# OpenTallas tools/mem_compiler/ucie_pma_gen.py: HBM host UCIe analog PMA ABSTRACT ot_ucie_pma_txm (assumed footprint/timing)
VERSION 5.7 ;
BUSBITCHARS "[]" ;
DIVIDERCHAR "/" ;
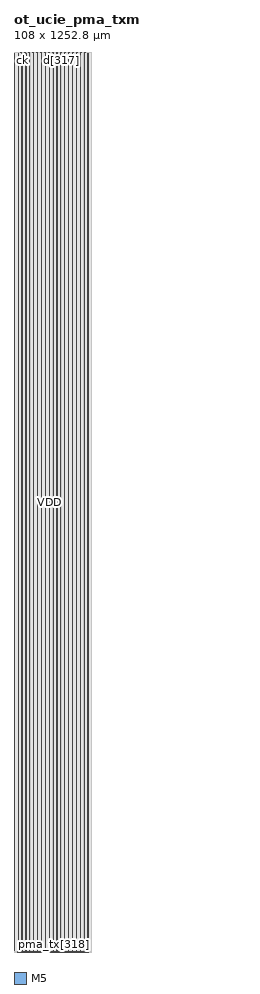
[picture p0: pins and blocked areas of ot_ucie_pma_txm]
MACRO ot_ucie_pma_txm
  FOREIGN ot_ucie_pma_txm 0 0 ;
  SYMMETRY X Y ;
  SIZE 108.000 BY 1252.800 ;
  CLASS BLOCK ;
  PIN ck
    DIRECTION INPUT ;
    USE CLOCK ;
    SHAPE ABUTMENT ;
    PORT
      LAYER M5 ;
      RECT 4.740 1252.608 4.764 1252.800 ;
    END
  END ck
  PIN d[0]
    DIRECTION INPUT ;
    USE SIGNAL ;
    SHAPE ABUTMENT ;
    PORT
      LAYER M5 ;
      RECT 4.932 1252.608 4.956 1252.800 ;
    END
  END d[0]
  PIN d[1]
    DIRECTION INPUT ;
    USE SIGNAL ;
    SHAPE ABUTMENT ;
    PORT
      LAYER M5 ;
      RECT 5.124 1252.608 5.148 1252.800 ;
    END
  END d[1]
  PIN d[2]
    DIRECTION INPUT ;
    USE SIGNAL ;
    SHAPE ABUTMENT ;
    PORT
      LAYER M5 ;
      RECT 5.316 1252.608 5.340 1252.800 ;
    END
  END d[2]
  PIN d[3]
    DIRECTION INPUT ;
    USE SIGNAL ;
    SHAPE ABUTMENT ;
    PORT
      LAYER M5 ;
      RECT 5.508 1252.608 5.532 1252.800 ;
    END
  END d[3]
  PIN d[4]
    DIRECTION INPUT ;
    USE SIGNAL ;
    SHAPE ABUTMENT ;
    PORT
      LAYER M5 ;
      RECT 5.700 1252.608 5.724 1252.800 ;
    END
  END d[4]
  PIN d[5]
    DIRECTION INPUT ;
    USE SIGNAL ;
    SHAPE ABUTMENT ;
    PORT
      LAYER M5 ;
      RECT 5.892 1252.608 5.916 1252.800 ;
    END
  END d[5]
  PIN d[6]
    DIRECTION INPUT ;
    USE SIGNAL ;
    SHAPE ABUTMENT ;
    PORT
      LAYER M5 ;
      RECT 6.084 1252.608 6.108 1252.800 ;
    END
  END d[6]
  PIN d[7]
    DIRECTION INPUT ;
    USE SIGNAL ;
    SHAPE ABUTMENT ;
    PORT
      LAYER M5 ;
      RECT 6.276 1252.608 6.300 1252.800 ;
    END
  END d[7]
  PIN d[8]
    DIRECTION INPUT ;
    USE SIGNAL ;
    SHAPE ABUTMENT ;
    PORT
      LAYER M5 ;
      RECT 6.468 1252.608 6.492 1252.800 ;
    END
  END d[8]
  PIN d[9]
    DIRECTION INPUT ;
    USE SIGNAL ;
    SHAPE ABUTMENT ;
    PORT
      LAYER M5 ;
      RECT 6.660 1252.608 6.684 1252.800 ;
    END
  END d[9]
  PIN d[10]
    DIRECTION INPUT ;
    USE SIGNAL ;
    SHAPE ABUTMENT ;
    PORT
      LAYER M5 ;
      RECT 6.852 1252.608 6.876 1252.800 ;
    END
  END d[10]
  PIN d[11]
    DIRECTION INPUT ;
    USE SIGNAL ;
    SHAPE ABUTMENT ;
    PORT
      LAYER M5 ;
      RECT 7.044 1252.608 7.068 1252.800 ;
    END
  END d[11]
  PIN d[12]
    DIRECTION INPUT ;
    USE SIGNAL ;
    SHAPE ABUTMENT ;
    PORT
      LAYER M5 ;
      RECT 7.236 1252.608 7.260 1252.800 ;
    END
  END d[12]
  PIN d[13]
    DIRECTION INPUT ;
    USE SIGNAL ;
    SHAPE ABUTMENT ;
    PORT
      LAYER M5 ;
      RECT 7.428 1252.608 7.452 1252.800 ;
    END
  END d[13]
  PIN d[14]
    DIRECTION INPUT ;
    USE SIGNAL ;
    SHAPE ABUTMENT ;
    PORT
      LAYER M5 ;
      RECT 7.620 1252.608 7.644 1252.800 ;
    END
  END d[14]
  PIN d[15]
    DIRECTION INPUT ;
    USE SIGNAL ;
    SHAPE ABUTMENT ;
    PORT
      LAYER M5 ;
      RECT 7.812 1252.608 7.836 1252.800 ;
    END
  END d[15]
  PIN d[16]
    DIRECTION INPUT ;
    USE SIGNAL ;
    SHAPE ABUTMENT ;
    PORT
      LAYER M5 ;
      RECT 8.004 1252.608 8.028 1252.800 ;
    END
  END d[16]
  PIN d[17]
    DIRECTION INPUT ;
    USE SIGNAL ;
    SHAPE ABUTMENT ;
    PORT
      LAYER M5 ;
      RECT 8.196 1252.608 8.220 1252.800 ;
    END
  END d[17]
  PIN d[18]
    DIRECTION INPUT ;
    USE SIGNAL ;
    SHAPE ABUTMENT ;
    PORT
      LAYER M5 ;
      RECT 8.388 1252.608 8.412 1252.800 ;
    END
  END d[18]
  PIN d[19]
    DIRECTION INPUT ;
    USE SIGNAL ;
    SHAPE ABUTMENT ;
    PORT
      LAYER M5 ;
      RECT 8.580 1252.608 8.604 1252.800 ;
    END
  END d[19]
  PIN d[20]
    DIRECTION INPUT ;
    USE SIGNAL ;
    SHAPE ABUTMENT ;
    PORT
      LAYER M5 ;
      RECT 8.772 1252.608 8.796 1252.800 ;
    END
  END d[20]
  PIN d[21]
    DIRECTION INPUT ;
    USE SIGNAL ;
    SHAPE ABUTMENT ;
    PORT
      LAYER M5 ;
      RECT 8.964 1252.608 8.988 1252.800 ;
    END
  END d[21]
  PIN d[22]
    DIRECTION INPUT ;
    USE SIGNAL ;
    SHAPE ABUTMENT ;
    PORT
      LAYER M5 ;
      RECT 9.156 1252.608 9.180 1252.800 ;
    END
  END d[22]
  PIN d[23]
    DIRECTION INPUT ;
    USE SIGNAL ;
    SHAPE ABUTMENT ;
    PORT
      LAYER M5 ;
      RECT 9.348 1252.608 9.372 1252.800 ;
    END
  END d[23]
  PIN d[24]
    DIRECTION INPUT ;
    USE SIGNAL ;
    SHAPE ABUTMENT ;
    PORT
      LAYER M5 ;
      RECT 9.540 1252.608 9.564 1252.800 ;
    END
  END d[24]
  PIN d[25]
    DIRECTION INPUT ;
    USE SIGNAL ;
    SHAPE ABUTMENT ;
    PORT
      LAYER M5 ;
      RECT 9.732 1252.608 9.756 1252.800 ;
    END
  END d[25]
  PIN d[26]
    DIRECTION INPUT ;
    USE SIGNAL ;
    SHAPE ABUTMENT ;
    PORT
      LAYER M5 ;
      RECT 9.924 1252.608 9.948 1252.800 ;
    END
  END d[26]
  PIN d[27]
    DIRECTION INPUT ;
    USE SIGNAL ;
    SHAPE ABUTMENT ;
    PORT
      LAYER M5 ;
      RECT 10.116 1252.608 10.140 1252.800 ;
    END
  END d[27]
  PIN d[28]
    DIRECTION INPUT ;
    USE SIGNAL ;
    SHAPE ABUTMENT ;
    PORT
      LAYER M5 ;
      RECT 10.308 1252.608 10.332 1252.800 ;
    END
  END d[28]
  PIN d[29]
    DIRECTION INPUT ;
    USE SIGNAL ;
    SHAPE ABUTMENT ;
    PORT
      LAYER M5 ;
      RECT 10.500 1252.608 10.524 1252.800 ;
    END
  END d[29]
  PIN d[30]
    DIRECTION INPUT ;
    USE SIGNAL ;
    SHAPE ABUTMENT ;
    PORT
      LAYER M5 ;
      RECT 10.692 1252.608 10.716 1252.800 ;
    END
  END d[30]
  PIN d[31]
    DIRECTION INPUT ;
    USE SIGNAL ;
    SHAPE ABUTMENT ;
    PORT
      LAYER M5 ;
      RECT 10.884 1252.608 10.908 1252.800 ;
    END
  END d[31]
  PIN d[32]
    DIRECTION INPUT ;
    USE SIGNAL ;
    SHAPE ABUTMENT ;
    PORT
      LAYER M5 ;
      RECT 11.076 1252.608 11.100 1252.800 ;
    END
  END d[32]
  PIN d[33]
    DIRECTION INPUT ;
    USE SIGNAL ;
    SHAPE ABUTMENT ;
    PORT
      LAYER M5 ;
      RECT 11.268 1252.608 11.292 1252.800 ;
    END
  END d[33]
  PIN d[34]
    DIRECTION INPUT ;
    USE SIGNAL ;
    SHAPE ABUTMENT ;
    PORT
      LAYER M5 ;
      RECT 11.460 1252.608 11.484 1252.800 ;
    END
  END d[34]
  PIN d[35]
    DIRECTION INPUT ;
    USE SIGNAL ;
    SHAPE ABUTMENT ;
    PORT
      LAYER M5 ;
      RECT 11.652 1252.608 11.676 1252.800 ;
    END
  END d[35]
  PIN d[36]
    DIRECTION INPUT ;
    USE SIGNAL ;
    SHAPE ABUTMENT ;
    PORT
      LAYER M5 ;
      RECT 11.844 1252.608 11.868 1252.800 ;
    END
  END d[36]
  PIN d[37]
    DIRECTION INPUT ;
    USE SIGNAL ;
    SHAPE ABUTMENT ;
    PORT
      LAYER M5 ;
      RECT 12.036 1252.608 12.060 1252.800 ;
    END
  END d[37]
  PIN d[38]
    DIRECTION INPUT ;
    USE SIGNAL ;
    SHAPE ABUTMENT ;
    PORT
      LAYER M5 ;
      RECT 12.228 1252.608 12.252 1252.800 ;
    END
  END d[38]
  PIN d[39]
    DIRECTION INPUT ;
    USE SIGNAL ;
    SHAPE ABUTMENT ;
    PORT
      LAYER M5 ;
      RECT 12.420 1252.608 12.444 1252.800 ;
    END
  END d[39]
  PIN d[40]
    DIRECTION INPUT ;
    USE SIGNAL ;
    SHAPE ABUTMENT ;
    PORT
      LAYER M5 ;
      RECT 12.612 1252.608 12.636 1252.800 ;
    END
  END d[40]
  PIN d[41]
    DIRECTION INPUT ;
    USE SIGNAL ;
    SHAPE ABUTMENT ;
    PORT
      LAYER M5 ;
      RECT 12.804 1252.608 12.828 1252.800 ;
    END
  END d[41]
  PIN d[42]
    DIRECTION INPUT ;
    USE SIGNAL ;
    SHAPE ABUTMENT ;
    PORT
      LAYER M5 ;
      RECT 12.996 1252.608 13.020 1252.800 ;
    END
  END d[42]
  PIN d[43]
    DIRECTION INPUT ;
    USE SIGNAL ;
    SHAPE ABUTMENT ;
    PORT
      LAYER M5 ;
      RECT 13.188 1252.608 13.212 1252.800 ;
    END
  END d[43]
  PIN d[44]
    DIRECTION INPUT ;
    USE SIGNAL ;
    SHAPE ABUTMENT ;
    PORT
      LAYER M5 ;
      RECT 13.380 1252.608 13.404 1252.800 ;
    END
  END d[44]
  PIN d[45]
    DIRECTION INPUT ;
    USE SIGNAL ;
    SHAPE ABUTMENT ;
    PORT
      LAYER M5 ;
      RECT 13.572 1252.608 13.596 1252.800 ;
    END
  END d[45]
  PIN d[46]
    DIRECTION INPUT ;
    USE SIGNAL ;
    SHAPE ABUTMENT ;
    PORT
      LAYER M5 ;
      RECT 13.764 1252.608 13.788 1252.800 ;
    END
  END d[46]
  PIN d[47]
    DIRECTION INPUT ;
    USE SIGNAL ;
    SHAPE ABUTMENT ;
    PORT
      LAYER M5 ;
      RECT 13.956 1252.608 13.980 1252.800 ;
    END
  END d[47]
  PIN d[48]
    DIRECTION INPUT ;
    USE SIGNAL ;
    SHAPE ABUTMENT ;
    PORT
      LAYER M5 ;
      RECT 14.148 1252.608 14.172 1252.800 ;
    END
  END d[48]
  PIN d[49]
    DIRECTION INPUT ;
    USE SIGNAL ;
    SHAPE ABUTMENT ;
    PORT
      LAYER M5 ;
      RECT 14.340 1252.608 14.364 1252.800 ;
    END
  END d[49]
  PIN d[50]
    DIRECTION INPUT ;
    USE SIGNAL ;
    SHAPE ABUTMENT ;
    PORT
      LAYER M5 ;
      RECT 14.532 1252.608 14.556 1252.800 ;
    END
  END d[50]
  PIN d[51]
    DIRECTION INPUT ;
    USE SIGNAL ;
    SHAPE ABUTMENT ;
    PORT
      LAYER M5 ;
      RECT 14.724 1252.608 14.748 1252.800 ;
    END
  END d[51]
  PIN d[52]
    DIRECTION INPUT ;
    USE SIGNAL ;
    SHAPE ABUTMENT ;
    PORT
      LAYER M5 ;
      RECT 14.916 1252.608 14.940 1252.800 ;
    END
  END d[52]
  PIN d[53]
    DIRECTION INPUT ;
    USE SIGNAL ;
    SHAPE ABUTMENT ;
    PORT
      LAYER M5 ;
      RECT 15.108 1252.608 15.132 1252.800 ;
    END
  END d[53]
  PIN d[54]
    DIRECTION INPUT ;
    USE SIGNAL ;
    SHAPE ABUTMENT ;
    PORT
      LAYER M5 ;
      RECT 15.300 1252.608 15.324 1252.800 ;
    END
  END d[54]
  PIN d[55]
    DIRECTION INPUT ;
    USE SIGNAL ;
    SHAPE ABUTMENT ;
    PORT
      LAYER M5 ;
      RECT 15.492 1252.608 15.516 1252.800 ;
    END
  END d[55]
  PIN d[56]
    DIRECTION INPUT ;
    USE SIGNAL ;
    SHAPE ABUTMENT ;
    PORT
      LAYER M5 ;
      RECT 15.684 1252.608 15.708 1252.800 ;
    END
  END d[56]
  PIN d[57]
    DIRECTION INPUT ;
    USE SIGNAL ;
    SHAPE ABUTMENT ;
    PORT
      LAYER M5 ;
      RECT 15.876 1252.608 15.900 1252.800 ;
    END
  END d[57]
  PIN d[58]
    DIRECTION INPUT ;
    USE SIGNAL ;
    SHAPE ABUTMENT ;
    PORT
      LAYER M5 ;
      RECT 16.068 1252.608 16.092 1252.800 ;
    END
  END d[58]
  PIN d[59]
    DIRECTION INPUT ;
    USE SIGNAL ;
    SHAPE ABUTMENT ;
    PORT
      LAYER M5 ;
      RECT 16.260 1252.608 16.284 1252.800 ;
    END
  END d[59]
  PIN d[60]
    DIRECTION INPUT ;
    USE SIGNAL ;
    SHAPE ABUTMENT ;
    PORT
      LAYER M5 ;
      RECT 16.452 1252.608 16.476 1252.800 ;
    END
  END d[60]
  PIN d[61]
    DIRECTION INPUT ;
    USE SIGNAL ;
    SHAPE ABUTMENT ;
    PORT
      LAYER M5 ;
      RECT 16.644 1252.608 16.668 1252.800 ;
    END
  END d[61]
  PIN d[62]
    DIRECTION INPUT ;
    USE SIGNAL ;
    SHAPE ABUTMENT ;
    PORT
      LAYER M5 ;
      RECT 16.836 1252.608 16.860 1252.800 ;
    END
  END d[62]
  PIN d[63]
    DIRECTION INPUT ;
    USE SIGNAL ;
    SHAPE ABUTMENT ;
    PORT
      LAYER M5 ;
      RECT 17.028 1252.608 17.052 1252.800 ;
    END
  END d[63]
  PIN d[64]
    DIRECTION INPUT ;
    USE SIGNAL ;
    SHAPE ABUTMENT ;
    PORT
      LAYER M5 ;
      RECT 17.220 1252.608 17.244 1252.800 ;
    END
  END d[64]
  PIN d[65]
    DIRECTION INPUT ;
    USE SIGNAL ;
    SHAPE ABUTMENT ;
    PORT
      LAYER M5 ;
      RECT 17.412 1252.608 17.436 1252.800 ;
    END
  END d[65]
  PIN d[66]
    DIRECTION INPUT ;
    USE SIGNAL ;
    SHAPE ABUTMENT ;
    PORT
      LAYER M5 ;
      RECT 17.604 1252.608 17.628 1252.800 ;
    END
  END d[66]
  PIN d[67]
    DIRECTION INPUT ;
    USE SIGNAL ;
    SHAPE ABUTMENT ;
    PORT
      LAYER M5 ;
      RECT 17.796 1252.608 17.820 1252.800 ;
    END
  END d[67]
  PIN d[68]
    DIRECTION INPUT ;
    USE SIGNAL ;
    SHAPE ABUTMENT ;
    PORT
      LAYER M5 ;
      RECT 17.988 1252.608 18.012 1252.800 ;
    END
  END d[68]
  PIN d[69]
    DIRECTION INPUT ;
    USE SIGNAL ;
    SHAPE ABUTMENT ;
    PORT
      LAYER M5 ;
      RECT 18.180 1252.608 18.204 1252.800 ;
    END
  END d[69]
  PIN d[70]
    DIRECTION INPUT ;
    USE SIGNAL ;
    SHAPE ABUTMENT ;
    PORT
      LAYER M5 ;
      RECT 18.372 1252.608 18.396 1252.800 ;
    END
  END d[70]
  PIN d[71]
    DIRECTION INPUT ;
    USE SIGNAL ;
    SHAPE ABUTMENT ;
    PORT
      LAYER M5 ;
      RECT 18.564 1252.608 18.588 1252.800 ;
    END
  END d[71]
  PIN d[72]
    DIRECTION INPUT ;
    USE SIGNAL ;
    SHAPE ABUTMENT ;
    PORT
      LAYER M5 ;
      RECT 18.756 1252.608 18.780 1252.800 ;
    END
  END d[72]
  PIN d[73]
    DIRECTION INPUT ;
    USE SIGNAL ;
    SHAPE ABUTMENT ;
    PORT
      LAYER M5 ;
      RECT 18.948 1252.608 18.972 1252.800 ;
    END
  END d[73]
  PIN d[74]
    DIRECTION INPUT ;
    USE SIGNAL ;
    SHAPE ABUTMENT ;
    PORT
      LAYER M5 ;
      RECT 19.140 1252.608 19.164 1252.800 ;
    END
  END d[74]
  PIN d[75]
    DIRECTION INPUT ;
    USE SIGNAL ;
    SHAPE ABUTMENT ;
    PORT
      LAYER M5 ;
      RECT 19.332 1252.608 19.356 1252.800 ;
    END
  END d[75]
  PIN d[76]
    DIRECTION INPUT ;
    USE SIGNAL ;
    SHAPE ABUTMENT ;
    PORT
      LAYER M5 ;
      RECT 19.524 1252.608 19.548 1252.800 ;
    END
  END d[76]
  PIN d[77]
    DIRECTION INPUT ;
    USE SIGNAL ;
    SHAPE ABUTMENT ;
    PORT
      LAYER M5 ;
      RECT 19.716 1252.608 19.740 1252.800 ;
    END
  END d[77]
  PIN d[78]
    DIRECTION INPUT ;
    USE SIGNAL ;
    SHAPE ABUTMENT ;
    PORT
      LAYER M5 ;
      RECT 19.908 1252.608 19.932 1252.800 ;
    END
  END d[78]
  PIN d[79]
    DIRECTION INPUT ;
    USE SIGNAL ;
    SHAPE ABUTMENT ;
    PORT
      LAYER M5 ;
      RECT 20.100 1252.608 20.124 1252.800 ;
    END
  END d[79]
  PIN d[80]
    DIRECTION INPUT ;
    USE SIGNAL ;
    SHAPE ABUTMENT ;
    PORT
      LAYER M5 ;
      RECT 20.292 1252.608 20.316 1252.800 ;
    END
  END d[80]
  PIN d[81]
    DIRECTION INPUT ;
    USE SIGNAL ;
    SHAPE ABUTMENT ;
    PORT
      LAYER M5 ;
      RECT 20.484 1252.608 20.508 1252.800 ;
    END
  END d[81]
  PIN d[82]
    DIRECTION INPUT ;
    USE SIGNAL ;
    SHAPE ABUTMENT ;
    PORT
      LAYER M5 ;
      RECT 20.676 1252.608 20.700 1252.800 ;
    END
  END d[82]
  PIN d[83]
    DIRECTION INPUT ;
    USE SIGNAL ;
    SHAPE ABUTMENT ;
    PORT
      LAYER M5 ;
      RECT 20.868 1252.608 20.892 1252.800 ;
    END
  END d[83]
  PIN d[84]
    DIRECTION INPUT ;
    USE SIGNAL ;
    SHAPE ABUTMENT ;
    PORT
      LAYER M5 ;
      RECT 21.060 1252.608 21.084 1252.800 ;
    END
  END d[84]
  PIN d[85]
    DIRECTION INPUT ;
    USE SIGNAL ;
    SHAPE ABUTMENT ;
    PORT
      LAYER M5 ;
      RECT 21.252 1252.608 21.276 1252.800 ;
    END
  END d[85]
  PIN d[86]
    DIRECTION INPUT ;
    USE SIGNAL ;
    SHAPE ABUTMENT ;
    PORT
      LAYER M5 ;
      RECT 21.444 1252.608 21.468 1252.800 ;
    END
  END d[86]
  PIN d[87]
    DIRECTION INPUT ;
    USE SIGNAL ;
    SHAPE ABUTMENT ;
    PORT
      LAYER M5 ;
      RECT 21.636 1252.608 21.660 1252.800 ;
    END
  END d[87]
  PIN d[88]
    DIRECTION INPUT ;
    USE SIGNAL ;
    SHAPE ABUTMENT ;
    PORT
      LAYER M5 ;
      RECT 21.828 1252.608 21.852 1252.800 ;
    END
  END d[88]
  PIN d[89]
    DIRECTION INPUT ;
    USE SIGNAL ;
    SHAPE ABUTMENT ;
    PORT
      LAYER M5 ;
      RECT 22.020 1252.608 22.044 1252.800 ;
    END
  END d[89]
  PIN d[90]
    DIRECTION INPUT ;
    USE SIGNAL ;
    SHAPE ABUTMENT ;
    PORT
      LAYER M5 ;
      RECT 22.212 1252.608 22.236 1252.800 ;
    END
  END d[90]
  PIN d[91]
    DIRECTION INPUT ;
    USE SIGNAL ;
    SHAPE ABUTMENT ;
    PORT
      LAYER M5 ;
      RECT 22.404 1252.608 22.428 1252.800 ;
    END
  END d[91]
  PIN d[92]
    DIRECTION INPUT ;
    USE SIGNAL ;
    SHAPE ABUTMENT ;
    PORT
      LAYER M5 ;
      RECT 22.596 1252.608 22.620 1252.800 ;
    END
  END d[92]
  PIN d[93]
    DIRECTION INPUT ;
    USE SIGNAL ;
    SHAPE ABUTMENT ;
    PORT
      LAYER M5 ;
      RECT 22.788 1252.608 22.812 1252.800 ;
    END
  END d[93]
  PIN d[94]
    DIRECTION INPUT ;
    USE SIGNAL ;
    SHAPE ABUTMENT ;
    PORT
      LAYER M5 ;
      RECT 22.980 1252.608 23.004 1252.800 ;
    END
  END d[94]
  PIN d[95]
    DIRECTION INPUT ;
    USE SIGNAL ;
    SHAPE ABUTMENT ;
    PORT
      LAYER M5 ;
      RECT 23.172 1252.608 23.196 1252.800 ;
    END
  END d[95]
  PIN d[96]
    DIRECTION INPUT ;
    USE SIGNAL ;
    SHAPE ABUTMENT ;
    PORT
      LAYER M5 ;
      RECT 23.364 1252.608 23.388 1252.800 ;
    END
  END d[96]
  PIN d[97]
    DIRECTION INPUT ;
    USE SIGNAL ;
    SHAPE ABUTMENT ;
    PORT
      LAYER M5 ;
      RECT 23.556 1252.608 23.580 1252.800 ;
    END
  END d[97]
  PIN d[98]
    DIRECTION INPUT ;
    USE SIGNAL ;
    SHAPE ABUTMENT ;
    PORT
      LAYER M5 ;
      RECT 23.748 1252.608 23.772 1252.800 ;
    END
  END d[98]
  PIN d[99]
    DIRECTION INPUT ;
    USE SIGNAL ;
    SHAPE ABUTMENT ;
    PORT
      LAYER M5 ;
      RECT 23.940 1252.608 23.964 1252.800 ;
    END
  END d[99]
  PIN d[100]
    DIRECTION INPUT ;
    USE SIGNAL ;
    SHAPE ABUTMENT ;
    PORT
      LAYER M5 ;
      RECT 24.132 1252.608 24.156 1252.800 ;
    END
  END d[100]
  PIN d[101]
    DIRECTION INPUT ;
    USE SIGNAL ;
    SHAPE ABUTMENT ;
    PORT
      LAYER M5 ;
      RECT 24.324 1252.608 24.348 1252.800 ;
    END
  END d[101]
  PIN d[102]
    DIRECTION INPUT ;
    USE SIGNAL ;
    SHAPE ABUTMENT ;
    PORT
      LAYER M5 ;
      RECT 24.516 1252.608 24.540 1252.800 ;
    END
  END d[102]
  PIN d[103]
    DIRECTION INPUT ;
    USE SIGNAL ;
    SHAPE ABUTMENT ;
    PORT
      LAYER M5 ;
      RECT 24.708 1252.608 24.732 1252.800 ;
    END
  END d[103]
  PIN d[104]
    DIRECTION INPUT ;
    USE SIGNAL ;
    SHAPE ABUTMENT ;
    PORT
      LAYER M5 ;
      RECT 24.900 1252.608 24.924 1252.800 ;
    END
  END d[104]
  PIN d[105]
    DIRECTION INPUT ;
    USE SIGNAL ;
    SHAPE ABUTMENT ;
    PORT
      LAYER M5 ;
      RECT 25.092 1252.608 25.116 1252.800 ;
    END
  END d[105]
  PIN d[106]
    DIRECTION INPUT ;
    USE SIGNAL ;
    SHAPE ABUTMENT ;
    PORT
      LAYER M5 ;
      RECT 25.284 1252.608 25.308 1252.800 ;
    END
  END d[106]
  PIN d[107]
    DIRECTION INPUT ;
    USE SIGNAL ;
    SHAPE ABUTMENT ;
    PORT
      LAYER M5 ;
      RECT 25.476 1252.608 25.500 1252.800 ;
    END
  END d[107]
  PIN d[108]
    DIRECTION INPUT ;
    USE SIGNAL ;
    SHAPE ABUTMENT ;
    PORT
      LAYER M5 ;
      RECT 25.668 1252.608 25.692 1252.800 ;
    END
  END d[108]
  PIN d[109]
    DIRECTION INPUT ;
    USE SIGNAL ;
    SHAPE ABUTMENT ;
    PORT
      LAYER M5 ;
      RECT 25.860 1252.608 25.884 1252.800 ;
    END
  END d[109]
  PIN d[110]
    DIRECTION INPUT ;
    USE SIGNAL ;
    SHAPE ABUTMENT ;
    PORT
      LAYER M5 ;
      RECT 26.052 1252.608 26.076 1252.800 ;
    END
  END d[110]
  PIN d[111]
    DIRECTION INPUT ;
    USE SIGNAL ;
    SHAPE ABUTMENT ;
    PORT
      LAYER M5 ;
      RECT 26.244 1252.608 26.268 1252.800 ;
    END
  END d[111]
  PIN d[112]
    DIRECTION INPUT ;
    USE SIGNAL ;
    SHAPE ABUTMENT ;
    PORT
      LAYER M5 ;
      RECT 26.436 1252.608 26.460 1252.800 ;
    END
  END d[112]
  PIN d[113]
    DIRECTION INPUT ;
    USE SIGNAL ;
    SHAPE ABUTMENT ;
    PORT
      LAYER M5 ;
      RECT 26.628 1252.608 26.652 1252.800 ;
    END
  END d[113]
  PIN d[114]
    DIRECTION INPUT ;
    USE SIGNAL ;
    SHAPE ABUTMENT ;
    PORT
      LAYER M5 ;
      RECT 26.820 1252.608 26.844 1252.800 ;
    END
  END d[114]
  PIN d[115]
    DIRECTION INPUT ;
    USE SIGNAL ;
    SHAPE ABUTMENT ;
    PORT
      LAYER M5 ;
      RECT 27.012 1252.608 27.036 1252.800 ;
    END
  END d[115]
  PIN d[116]
    DIRECTION INPUT ;
    USE SIGNAL ;
    SHAPE ABUTMENT ;
    PORT
      LAYER M5 ;
      RECT 27.204 1252.608 27.228 1252.800 ;
    END
  END d[116]
  PIN d[117]
    DIRECTION INPUT ;
    USE SIGNAL ;
    SHAPE ABUTMENT ;
    PORT
      LAYER M5 ;
      RECT 27.396 1252.608 27.420 1252.800 ;
    END
  END d[117]
  PIN d[118]
    DIRECTION INPUT ;
    USE SIGNAL ;
    SHAPE ABUTMENT ;
    PORT
      LAYER M5 ;
      RECT 27.588 1252.608 27.612 1252.800 ;
    END
  END d[118]
  PIN d[119]
    DIRECTION INPUT ;
    USE SIGNAL ;
    SHAPE ABUTMENT ;
    PORT
      LAYER M5 ;
      RECT 27.780 1252.608 27.804 1252.800 ;
    END
  END d[119]
  PIN d[120]
    DIRECTION INPUT ;
    USE SIGNAL ;
    SHAPE ABUTMENT ;
    PORT
      LAYER M5 ;
      RECT 27.972 1252.608 27.996 1252.800 ;
    END
  END d[120]
  PIN d[121]
    DIRECTION INPUT ;
    USE SIGNAL ;
    SHAPE ABUTMENT ;
    PORT
      LAYER M5 ;
      RECT 28.164 1252.608 28.188 1252.800 ;
    END
  END d[121]
  PIN d[122]
    DIRECTION INPUT ;
    USE SIGNAL ;
    SHAPE ABUTMENT ;
    PORT
      LAYER M5 ;
      RECT 28.356 1252.608 28.380 1252.800 ;
    END
  END d[122]
  PIN d[123]
    DIRECTION INPUT ;
    USE SIGNAL ;
    SHAPE ABUTMENT ;
    PORT
      LAYER M5 ;
      RECT 28.548 1252.608 28.572 1252.800 ;
    END
  END d[123]
  PIN d[124]
    DIRECTION INPUT ;
    USE SIGNAL ;
    SHAPE ABUTMENT ;
    PORT
      LAYER M5 ;
      RECT 28.740 1252.608 28.764 1252.800 ;
    END
  END d[124]
  PIN d[125]
    DIRECTION INPUT ;
    USE SIGNAL ;
    SHAPE ABUTMENT ;
    PORT
      LAYER M5 ;
      RECT 28.932 1252.608 28.956 1252.800 ;
    END
  END d[125]
  PIN d[126]
    DIRECTION INPUT ;
    USE SIGNAL ;
    SHAPE ABUTMENT ;
    PORT
      LAYER M5 ;
      RECT 29.124 1252.608 29.148 1252.800 ;
    END
  END d[126]
  PIN d[127]
    DIRECTION INPUT ;
    USE SIGNAL ;
    SHAPE ABUTMENT ;
    PORT
      LAYER M5 ;
      RECT 29.316 1252.608 29.340 1252.800 ;
    END
  END d[127]
  PIN d[128]
    DIRECTION INPUT ;
    USE SIGNAL ;
    SHAPE ABUTMENT ;
    PORT
      LAYER M5 ;
      RECT 29.508 1252.608 29.532 1252.800 ;
    END
  END d[128]
  PIN d[129]
    DIRECTION INPUT ;
    USE SIGNAL ;
    SHAPE ABUTMENT ;
    PORT
      LAYER M5 ;
      RECT 29.700 1252.608 29.724 1252.800 ;
    END
  END d[129]
  PIN d[130]
    DIRECTION INPUT ;
    USE SIGNAL ;
    SHAPE ABUTMENT ;
    PORT
      LAYER M5 ;
      RECT 29.892 1252.608 29.916 1252.800 ;
    END
  END d[130]
  PIN d[131]
    DIRECTION INPUT ;
    USE SIGNAL ;
    SHAPE ABUTMENT ;
    PORT
      LAYER M5 ;
      RECT 30.084 1252.608 30.108 1252.800 ;
    END
  END d[131]
  PIN d[132]
    DIRECTION INPUT ;
    USE SIGNAL ;
    SHAPE ABUTMENT ;
    PORT
      LAYER M5 ;
      RECT 30.276 1252.608 30.300 1252.800 ;
    END
  END d[132]
  PIN d[133]
    DIRECTION INPUT ;
    USE SIGNAL ;
    SHAPE ABUTMENT ;
    PORT
      LAYER M5 ;
      RECT 30.468 1252.608 30.492 1252.800 ;
    END
  END d[133]
  PIN d[134]
    DIRECTION INPUT ;
    USE SIGNAL ;
    SHAPE ABUTMENT ;
    PORT
      LAYER M5 ;
      RECT 30.660 1252.608 30.684 1252.800 ;
    END
  END d[134]
  PIN d[135]
    DIRECTION INPUT ;
    USE SIGNAL ;
    SHAPE ABUTMENT ;
    PORT
      LAYER M5 ;
      RECT 30.852 1252.608 30.876 1252.800 ;
    END
  END d[135]
  PIN d[136]
    DIRECTION INPUT ;
    USE SIGNAL ;
    SHAPE ABUTMENT ;
    PORT
      LAYER M5 ;
      RECT 31.044 1252.608 31.068 1252.800 ;
    END
  END d[136]
  PIN d[137]
    DIRECTION INPUT ;
    USE SIGNAL ;
    SHAPE ABUTMENT ;
    PORT
      LAYER M5 ;
      RECT 31.236 1252.608 31.260 1252.800 ;
    END
  END d[137]
  PIN d[138]
    DIRECTION INPUT ;
    USE SIGNAL ;
    SHAPE ABUTMENT ;
    PORT
      LAYER M5 ;
      RECT 31.428 1252.608 31.452 1252.800 ;
    END
  END d[138]
  PIN d[139]
    DIRECTION INPUT ;
    USE SIGNAL ;
    SHAPE ABUTMENT ;
    PORT
      LAYER M5 ;
      RECT 31.620 1252.608 31.644 1252.800 ;
    END
  END d[139]
  PIN d[140]
    DIRECTION INPUT ;
    USE SIGNAL ;
    SHAPE ABUTMENT ;
    PORT
      LAYER M5 ;
      RECT 31.812 1252.608 31.836 1252.800 ;
    END
  END d[140]
  PIN d[141]
    DIRECTION INPUT ;
    USE SIGNAL ;
    SHAPE ABUTMENT ;
    PORT
      LAYER M5 ;
      RECT 32.004 1252.608 32.028 1252.800 ;
    END
  END d[141]
  PIN d[142]
    DIRECTION INPUT ;
    USE SIGNAL ;
    SHAPE ABUTMENT ;
    PORT
      LAYER M5 ;
      RECT 32.196 1252.608 32.220 1252.800 ;
    END
  END d[142]
  PIN d[143]
    DIRECTION INPUT ;
    USE SIGNAL ;
    SHAPE ABUTMENT ;
    PORT
      LAYER M5 ;
      RECT 32.388 1252.608 32.412 1252.800 ;
    END
  END d[143]
  PIN d[144]
    DIRECTION INPUT ;
    USE SIGNAL ;
    SHAPE ABUTMENT ;
    PORT
      LAYER M5 ;
      RECT 32.580 1252.608 32.604 1252.800 ;
    END
  END d[144]
  PIN d[145]
    DIRECTION INPUT ;
    USE SIGNAL ;
    SHAPE ABUTMENT ;
    PORT
      LAYER M5 ;
      RECT 32.772 1252.608 32.796 1252.800 ;
    END
  END d[145]
  PIN d[146]
    DIRECTION INPUT ;
    USE SIGNAL ;
    SHAPE ABUTMENT ;
    PORT
      LAYER M5 ;
      RECT 32.964 1252.608 32.988 1252.800 ;
    END
  END d[146]
  PIN d[147]
    DIRECTION INPUT ;
    USE SIGNAL ;
    SHAPE ABUTMENT ;
    PORT
      LAYER M5 ;
      RECT 33.156 1252.608 33.180 1252.800 ;
    END
  END d[147]
  PIN d[148]
    DIRECTION INPUT ;
    USE SIGNAL ;
    SHAPE ABUTMENT ;
    PORT
      LAYER M5 ;
      RECT 33.348 1252.608 33.372 1252.800 ;
    END
  END d[148]
  PIN d[149]
    DIRECTION INPUT ;
    USE SIGNAL ;
    SHAPE ABUTMENT ;
    PORT
      LAYER M5 ;
      RECT 33.540 1252.608 33.564 1252.800 ;
    END
  END d[149]
  PIN d[150]
    DIRECTION INPUT ;
    USE SIGNAL ;
    SHAPE ABUTMENT ;
    PORT
      LAYER M5 ;
      RECT 33.732 1252.608 33.756 1252.800 ;
    END
  END d[150]
  PIN d[151]
    DIRECTION INPUT ;
    USE SIGNAL ;
    SHAPE ABUTMENT ;
    PORT
      LAYER M5 ;
      RECT 33.924 1252.608 33.948 1252.800 ;
    END
  END d[151]
  PIN d[152]
    DIRECTION INPUT ;
    USE SIGNAL ;
    SHAPE ABUTMENT ;
    PORT
      LAYER M5 ;
      RECT 34.116 1252.608 34.140 1252.800 ;
    END
  END d[152]
  PIN d[153]
    DIRECTION INPUT ;
    USE SIGNAL ;
    SHAPE ABUTMENT ;
    PORT
      LAYER M5 ;
      RECT 34.308 1252.608 34.332 1252.800 ;
    END
  END d[153]
  PIN d[154]
    DIRECTION INPUT ;
    USE SIGNAL ;
    SHAPE ABUTMENT ;
    PORT
      LAYER M5 ;
      RECT 34.500 1252.608 34.524 1252.800 ;
    END
  END d[154]
  PIN d[155]
    DIRECTION INPUT ;
    USE SIGNAL ;
    SHAPE ABUTMENT ;
    PORT
      LAYER M5 ;
      RECT 34.692 1252.608 34.716 1252.800 ;
    END
  END d[155]
  PIN d[156]
    DIRECTION INPUT ;
    USE SIGNAL ;
    SHAPE ABUTMENT ;
    PORT
      LAYER M5 ;
      RECT 34.884 1252.608 34.908 1252.800 ;
    END
  END d[156]
  PIN d[157]
    DIRECTION INPUT ;
    USE SIGNAL ;
    SHAPE ABUTMENT ;
    PORT
      LAYER M5 ;
      RECT 35.076 1252.608 35.100 1252.800 ;
    END
  END d[157]
  PIN d[158]
    DIRECTION INPUT ;
    USE SIGNAL ;
    SHAPE ABUTMENT ;
    PORT
      LAYER M5 ;
      RECT 35.268 1252.608 35.292 1252.800 ;
    END
  END d[158]
  PIN d[159]
    DIRECTION INPUT ;
    USE SIGNAL ;
    SHAPE ABUTMENT ;
    PORT
      LAYER M5 ;
      RECT 35.460 1252.608 35.484 1252.800 ;
    END
  END d[159]
  PIN d[160]
    DIRECTION INPUT ;
    USE SIGNAL ;
    SHAPE ABUTMENT ;
    PORT
      LAYER M5 ;
      RECT 35.652 1252.608 35.676 1252.800 ;
    END
  END d[160]
  PIN d[161]
    DIRECTION INPUT ;
    USE SIGNAL ;
    SHAPE ABUTMENT ;
    PORT
      LAYER M5 ;
      RECT 35.844 1252.608 35.868 1252.800 ;
    END
  END d[161]
  PIN d[162]
    DIRECTION INPUT ;
    USE SIGNAL ;
    SHAPE ABUTMENT ;
    PORT
      LAYER M5 ;
      RECT 36.036 1252.608 36.060 1252.800 ;
    END
  END d[162]
  PIN d[163]
    DIRECTION INPUT ;
    USE SIGNAL ;
    SHAPE ABUTMENT ;
    PORT
      LAYER M5 ;
      RECT 36.228 1252.608 36.252 1252.800 ;
    END
  END d[163]
  PIN d[164]
    DIRECTION INPUT ;
    USE SIGNAL ;
    SHAPE ABUTMENT ;
    PORT
      LAYER M5 ;
      RECT 36.420 1252.608 36.444 1252.800 ;
    END
  END d[164]
  PIN d[165]
    DIRECTION INPUT ;
    USE SIGNAL ;
    SHAPE ABUTMENT ;
    PORT
      LAYER M5 ;
      RECT 36.612 1252.608 36.636 1252.800 ;
    END
  END d[165]
  PIN d[166]
    DIRECTION INPUT ;
    USE SIGNAL ;
    SHAPE ABUTMENT ;
    PORT
      LAYER M5 ;
      RECT 36.804 1252.608 36.828 1252.800 ;
    END
  END d[166]
  PIN d[167]
    DIRECTION INPUT ;
    USE SIGNAL ;
    SHAPE ABUTMENT ;
    PORT
      LAYER M5 ;
      RECT 36.996 1252.608 37.020 1252.800 ;
    END
  END d[167]
  PIN d[168]
    DIRECTION INPUT ;
    USE SIGNAL ;
    SHAPE ABUTMENT ;
    PORT
      LAYER M5 ;
      RECT 37.188 1252.608 37.212 1252.800 ;
    END
  END d[168]
  PIN d[169]
    DIRECTION INPUT ;
    USE SIGNAL ;
    SHAPE ABUTMENT ;
    PORT
      LAYER M5 ;
      RECT 37.380 1252.608 37.404 1252.800 ;
    END
  END d[169]
  PIN d[170]
    DIRECTION INPUT ;
    USE SIGNAL ;
    SHAPE ABUTMENT ;
    PORT
      LAYER M5 ;
      RECT 37.572 1252.608 37.596 1252.800 ;
    END
  END d[170]
  PIN d[171]
    DIRECTION INPUT ;
    USE SIGNAL ;
    SHAPE ABUTMENT ;
    PORT
      LAYER M5 ;
      RECT 37.764 1252.608 37.788 1252.800 ;
    END
  END d[171]
  PIN d[172]
    DIRECTION INPUT ;
    USE SIGNAL ;
    SHAPE ABUTMENT ;
    PORT
      LAYER M5 ;
      RECT 37.956 1252.608 37.980 1252.800 ;
    END
  END d[172]
  PIN d[173]
    DIRECTION INPUT ;
    USE SIGNAL ;
    SHAPE ABUTMENT ;
    PORT
      LAYER M5 ;
      RECT 38.148 1252.608 38.172 1252.800 ;
    END
  END d[173]
  PIN d[174]
    DIRECTION INPUT ;
    USE SIGNAL ;
    SHAPE ABUTMENT ;
    PORT
      LAYER M5 ;
      RECT 38.340 1252.608 38.364 1252.800 ;
    END
  END d[174]
  PIN d[175]
    DIRECTION INPUT ;
    USE SIGNAL ;
    SHAPE ABUTMENT ;
    PORT
      LAYER M5 ;
      RECT 38.532 1252.608 38.556 1252.800 ;
    END
  END d[175]
  PIN d[176]
    DIRECTION INPUT ;
    USE SIGNAL ;
    SHAPE ABUTMENT ;
    PORT
      LAYER M5 ;
      RECT 38.724 1252.608 38.748 1252.800 ;
    END
  END d[176]
  PIN d[177]
    DIRECTION INPUT ;
    USE SIGNAL ;
    SHAPE ABUTMENT ;
    PORT
      LAYER M5 ;
      RECT 38.916 1252.608 38.940 1252.800 ;
    END
  END d[177]
  PIN d[178]
    DIRECTION INPUT ;
    USE SIGNAL ;
    SHAPE ABUTMENT ;
    PORT
      LAYER M5 ;
      RECT 39.108 1252.608 39.132 1252.800 ;
    END
  END d[178]
  PIN d[179]
    DIRECTION INPUT ;
    USE SIGNAL ;
    SHAPE ABUTMENT ;
    PORT
      LAYER M5 ;
      RECT 39.300 1252.608 39.324 1252.800 ;
    END
  END d[179]
  PIN d[180]
    DIRECTION INPUT ;
    USE SIGNAL ;
    SHAPE ABUTMENT ;
    PORT
      LAYER M5 ;
      RECT 39.492 1252.608 39.516 1252.800 ;
    END
  END d[180]
  PIN d[181]
    DIRECTION INPUT ;
    USE SIGNAL ;
    SHAPE ABUTMENT ;
    PORT
      LAYER M5 ;
      RECT 39.684 1252.608 39.708 1252.800 ;
    END
  END d[181]
  PIN d[182]
    DIRECTION INPUT ;
    USE SIGNAL ;
    SHAPE ABUTMENT ;
    PORT
      LAYER M5 ;
      RECT 39.876 1252.608 39.900 1252.800 ;
    END
  END d[182]
  PIN d[183]
    DIRECTION INPUT ;
    USE SIGNAL ;
    SHAPE ABUTMENT ;
    PORT
      LAYER M5 ;
      RECT 40.068 1252.608 40.092 1252.800 ;
    END
  END d[183]
  PIN d[184]
    DIRECTION INPUT ;
    USE SIGNAL ;
    SHAPE ABUTMENT ;
    PORT
      LAYER M5 ;
      RECT 40.260 1252.608 40.284 1252.800 ;
    END
  END d[184]
  PIN d[185]
    DIRECTION INPUT ;
    USE SIGNAL ;
    SHAPE ABUTMENT ;
    PORT
      LAYER M5 ;
      RECT 40.452 1252.608 40.476 1252.800 ;
    END
  END d[185]
  PIN d[186]
    DIRECTION INPUT ;
    USE SIGNAL ;
    SHAPE ABUTMENT ;
    PORT
      LAYER M5 ;
      RECT 40.644 1252.608 40.668 1252.800 ;
    END
  END d[186]
  PIN d[187]
    DIRECTION INPUT ;
    USE SIGNAL ;
    SHAPE ABUTMENT ;
    PORT
      LAYER M5 ;
      RECT 40.836 1252.608 40.860 1252.800 ;
    END
  END d[187]
  PIN d[188]
    DIRECTION INPUT ;
    USE SIGNAL ;
    SHAPE ABUTMENT ;
    PORT
      LAYER M5 ;
      RECT 41.028 1252.608 41.052 1252.800 ;
    END
  END d[188]
  PIN d[189]
    DIRECTION INPUT ;
    USE SIGNAL ;
    SHAPE ABUTMENT ;
    PORT
      LAYER M5 ;
      RECT 41.220 1252.608 41.244 1252.800 ;
    END
  END d[189]
  PIN d[190]
    DIRECTION INPUT ;
    USE SIGNAL ;
    SHAPE ABUTMENT ;
    PORT
      LAYER M5 ;
      RECT 41.412 1252.608 41.436 1252.800 ;
    END
  END d[190]
  PIN d[191]
    DIRECTION INPUT ;
    USE SIGNAL ;
    SHAPE ABUTMENT ;
    PORT
      LAYER M5 ;
      RECT 41.604 1252.608 41.628 1252.800 ;
    END
  END d[191]
  PIN d[192]
    DIRECTION INPUT ;
    USE SIGNAL ;
    SHAPE ABUTMENT ;
    PORT
      LAYER M5 ;
      RECT 41.796 1252.608 41.820 1252.800 ;
    END
  END d[192]
  PIN d[193]
    DIRECTION INPUT ;
    USE SIGNAL ;
    SHAPE ABUTMENT ;
    PORT
      LAYER M5 ;
      RECT 41.988 1252.608 42.012 1252.800 ;
    END
  END d[193]
  PIN d[194]
    DIRECTION INPUT ;
    USE SIGNAL ;
    SHAPE ABUTMENT ;
    PORT
      LAYER M5 ;
      RECT 42.180 1252.608 42.204 1252.800 ;
    END
  END d[194]
  PIN d[195]
    DIRECTION INPUT ;
    USE SIGNAL ;
    SHAPE ABUTMENT ;
    PORT
      LAYER M5 ;
      RECT 42.372 1252.608 42.396 1252.800 ;
    END
  END d[195]
  PIN d[196]
    DIRECTION INPUT ;
    USE SIGNAL ;
    SHAPE ABUTMENT ;
    PORT
      LAYER M5 ;
      RECT 42.564 1252.608 42.588 1252.800 ;
    END
  END d[196]
  PIN d[197]
    DIRECTION INPUT ;
    USE SIGNAL ;
    SHAPE ABUTMENT ;
    PORT
      LAYER M5 ;
      RECT 42.756 1252.608 42.780 1252.800 ;
    END
  END d[197]
  PIN d[198]
    DIRECTION INPUT ;
    USE SIGNAL ;
    SHAPE ABUTMENT ;
    PORT
      LAYER M5 ;
      RECT 42.948 1252.608 42.972 1252.800 ;
    END
  END d[198]
  PIN d[199]
    DIRECTION INPUT ;
    USE SIGNAL ;
    SHAPE ABUTMENT ;
    PORT
      LAYER M5 ;
      RECT 43.140 1252.608 43.164 1252.800 ;
    END
  END d[199]
  PIN d[200]
    DIRECTION INPUT ;
    USE SIGNAL ;
    SHAPE ABUTMENT ;
    PORT
      LAYER M5 ;
      RECT 43.332 1252.608 43.356 1252.800 ;
    END
  END d[200]
  PIN d[201]
    DIRECTION INPUT ;
    USE SIGNAL ;
    SHAPE ABUTMENT ;
    PORT
      LAYER M5 ;
      RECT 43.524 1252.608 43.548 1252.800 ;
    END
  END d[201]
  PIN d[202]
    DIRECTION INPUT ;
    USE SIGNAL ;
    SHAPE ABUTMENT ;
    PORT
      LAYER M5 ;
      RECT 43.716 1252.608 43.740 1252.800 ;
    END
  END d[202]
  PIN d[203]
    DIRECTION INPUT ;
    USE SIGNAL ;
    SHAPE ABUTMENT ;
    PORT
      LAYER M5 ;
      RECT 43.908 1252.608 43.932 1252.800 ;
    END
  END d[203]
  PIN d[204]
    DIRECTION INPUT ;
    USE SIGNAL ;
    SHAPE ABUTMENT ;
    PORT
      LAYER M5 ;
      RECT 44.100 1252.608 44.124 1252.800 ;
    END
  END d[204]
  PIN d[205]
    DIRECTION INPUT ;
    USE SIGNAL ;
    SHAPE ABUTMENT ;
    PORT
      LAYER M5 ;
      RECT 44.292 1252.608 44.316 1252.800 ;
    END
  END d[205]
  PIN d[206]
    DIRECTION INPUT ;
    USE SIGNAL ;
    SHAPE ABUTMENT ;
    PORT
      LAYER M5 ;
      RECT 44.484 1252.608 44.508 1252.800 ;
    END
  END d[206]
  PIN d[207]
    DIRECTION INPUT ;
    USE SIGNAL ;
    SHAPE ABUTMENT ;
    PORT
      LAYER M5 ;
      RECT 44.676 1252.608 44.700 1252.800 ;
    END
  END d[207]
  PIN d[208]
    DIRECTION INPUT ;
    USE SIGNAL ;
    SHAPE ABUTMENT ;
    PORT
      LAYER M5 ;
      RECT 44.868 1252.608 44.892 1252.800 ;
    END
  END d[208]
  PIN d[209]
    DIRECTION INPUT ;
    USE SIGNAL ;
    SHAPE ABUTMENT ;
    PORT
      LAYER M5 ;
      RECT 45.060 1252.608 45.084 1252.800 ;
    END
  END d[209]
  PIN d[210]
    DIRECTION INPUT ;
    USE SIGNAL ;
    SHAPE ABUTMENT ;
    PORT
      LAYER M5 ;
      RECT 45.252 1252.608 45.276 1252.800 ;
    END
  END d[210]
  PIN d[211]
    DIRECTION INPUT ;
    USE SIGNAL ;
    SHAPE ABUTMENT ;
    PORT
      LAYER M5 ;
      RECT 45.444 1252.608 45.468 1252.800 ;
    END
  END d[211]
  PIN d[212]
    DIRECTION INPUT ;
    USE SIGNAL ;
    SHAPE ABUTMENT ;
    PORT
      LAYER M5 ;
      RECT 45.636 1252.608 45.660 1252.800 ;
    END
  END d[212]
  PIN d[213]
    DIRECTION INPUT ;
    USE SIGNAL ;
    SHAPE ABUTMENT ;
    PORT
      LAYER M5 ;
      RECT 45.828 1252.608 45.852 1252.800 ;
    END
  END d[213]
  PIN d[214]
    DIRECTION INPUT ;
    USE SIGNAL ;
    SHAPE ABUTMENT ;
    PORT
      LAYER M5 ;
      RECT 46.020 1252.608 46.044 1252.800 ;
    END
  END d[214]
  PIN d[215]
    DIRECTION INPUT ;
    USE SIGNAL ;
    SHAPE ABUTMENT ;
    PORT
      LAYER M5 ;
      RECT 46.212 1252.608 46.236 1252.800 ;
    END
  END d[215]
  PIN d[216]
    DIRECTION INPUT ;
    USE SIGNAL ;
    SHAPE ABUTMENT ;
    PORT
      LAYER M5 ;
      RECT 46.404 1252.608 46.428 1252.800 ;
    END
  END d[216]
  PIN d[217]
    DIRECTION INPUT ;
    USE SIGNAL ;
    SHAPE ABUTMENT ;
    PORT
      LAYER M5 ;
      RECT 46.596 1252.608 46.620 1252.800 ;
    END
  END d[217]
  PIN d[218]
    DIRECTION INPUT ;
    USE SIGNAL ;
    SHAPE ABUTMENT ;
    PORT
      LAYER M5 ;
      RECT 46.788 1252.608 46.812 1252.800 ;
    END
  END d[218]
  PIN d[219]
    DIRECTION INPUT ;
    USE SIGNAL ;
    SHAPE ABUTMENT ;
    PORT
      LAYER M5 ;
      RECT 46.980 1252.608 47.004 1252.800 ;
    END
  END d[219]
  PIN d[220]
    DIRECTION INPUT ;
    USE SIGNAL ;
    SHAPE ABUTMENT ;
    PORT
      LAYER M5 ;
      RECT 47.172 1252.608 47.196 1252.800 ;
    END
  END d[220]
  PIN d[221]
    DIRECTION INPUT ;
    USE SIGNAL ;
    SHAPE ABUTMENT ;
    PORT
      LAYER M5 ;
      RECT 47.364 1252.608 47.388 1252.800 ;
    END
  END d[221]
  PIN d[222]
    DIRECTION INPUT ;
    USE SIGNAL ;
    SHAPE ABUTMENT ;
    PORT
      LAYER M5 ;
      RECT 47.556 1252.608 47.580 1252.800 ;
    END
  END d[222]
  PIN d[223]
    DIRECTION INPUT ;
    USE SIGNAL ;
    SHAPE ABUTMENT ;
    PORT
      LAYER M5 ;
      RECT 47.748 1252.608 47.772 1252.800 ;
    END
  END d[223]
  PIN d[224]
    DIRECTION INPUT ;
    USE SIGNAL ;
    SHAPE ABUTMENT ;
    PORT
      LAYER M5 ;
      RECT 47.940 1252.608 47.964 1252.800 ;
    END
  END d[224]
  PIN d[225]
    DIRECTION INPUT ;
    USE SIGNAL ;
    SHAPE ABUTMENT ;
    PORT
      LAYER M5 ;
      RECT 48.132 1252.608 48.156 1252.800 ;
    END
  END d[225]
  PIN d[226]
    DIRECTION INPUT ;
    USE SIGNAL ;
    SHAPE ABUTMENT ;
    PORT
      LAYER M5 ;
      RECT 48.324 1252.608 48.348 1252.800 ;
    END
  END d[226]
  PIN d[227]
    DIRECTION INPUT ;
    USE SIGNAL ;
    SHAPE ABUTMENT ;
    PORT
      LAYER M5 ;
      RECT 48.516 1252.608 48.540 1252.800 ;
    END
  END d[227]
  PIN d[228]
    DIRECTION INPUT ;
    USE SIGNAL ;
    SHAPE ABUTMENT ;
    PORT
      LAYER M5 ;
      RECT 48.708 1252.608 48.732 1252.800 ;
    END
  END d[228]
  PIN d[229]
    DIRECTION INPUT ;
    USE SIGNAL ;
    SHAPE ABUTMENT ;
    PORT
      LAYER M5 ;
      RECT 48.900 1252.608 48.924 1252.800 ;
    END
  END d[229]
  PIN d[230]
    DIRECTION INPUT ;
    USE SIGNAL ;
    SHAPE ABUTMENT ;
    PORT
      LAYER M5 ;
      RECT 49.092 1252.608 49.116 1252.800 ;
    END
  END d[230]
  PIN d[231]
    DIRECTION INPUT ;
    USE SIGNAL ;
    SHAPE ABUTMENT ;
    PORT
      LAYER M5 ;
      RECT 49.284 1252.608 49.308 1252.800 ;
    END
  END d[231]
  PIN d[232]
    DIRECTION INPUT ;
    USE SIGNAL ;
    SHAPE ABUTMENT ;
    PORT
      LAYER M5 ;
      RECT 49.476 1252.608 49.500 1252.800 ;
    END
  END d[232]
  PIN d[233]
    DIRECTION INPUT ;
    USE SIGNAL ;
    SHAPE ABUTMENT ;
    PORT
      LAYER M5 ;
      RECT 49.668 1252.608 49.692 1252.800 ;
    END
  END d[233]
  PIN d[234]
    DIRECTION INPUT ;
    USE SIGNAL ;
    SHAPE ABUTMENT ;
    PORT
      LAYER M5 ;
      RECT 49.860 1252.608 49.884 1252.800 ;
    END
  END d[234]
  PIN d[235]
    DIRECTION INPUT ;
    USE SIGNAL ;
    SHAPE ABUTMENT ;
    PORT
      LAYER M5 ;
      RECT 50.052 1252.608 50.076 1252.800 ;
    END
  END d[235]
  PIN d[236]
    DIRECTION INPUT ;
    USE SIGNAL ;
    SHAPE ABUTMENT ;
    PORT
      LAYER M5 ;
      RECT 50.244 1252.608 50.268 1252.800 ;
    END
  END d[236]
  PIN d[237]
    DIRECTION INPUT ;
    USE SIGNAL ;
    SHAPE ABUTMENT ;
    PORT
      LAYER M5 ;
      RECT 50.436 1252.608 50.460 1252.800 ;
    END
  END d[237]
  PIN d[238]
    DIRECTION INPUT ;
    USE SIGNAL ;
    SHAPE ABUTMENT ;
    PORT
      LAYER M5 ;
      RECT 50.628 1252.608 50.652 1252.800 ;
    END
  END d[238]
  PIN d[239]
    DIRECTION INPUT ;
    USE SIGNAL ;
    SHAPE ABUTMENT ;
    PORT
      LAYER M5 ;
      RECT 50.820 1252.608 50.844 1252.800 ;
    END
  END d[239]
  PIN d[240]
    DIRECTION INPUT ;
    USE SIGNAL ;
    SHAPE ABUTMENT ;
    PORT
      LAYER M5 ;
      RECT 51.012 1252.608 51.036 1252.800 ;
    END
  END d[240]
  PIN d[241]
    DIRECTION INPUT ;
    USE SIGNAL ;
    SHAPE ABUTMENT ;
    PORT
      LAYER M5 ;
      RECT 51.204 1252.608 51.228 1252.800 ;
    END
  END d[241]
  PIN d[242]
    DIRECTION INPUT ;
    USE SIGNAL ;
    SHAPE ABUTMENT ;
    PORT
      LAYER M5 ;
      RECT 51.396 1252.608 51.420 1252.800 ;
    END
  END d[242]
  PIN d[243]
    DIRECTION INPUT ;
    USE SIGNAL ;
    SHAPE ABUTMENT ;
    PORT
      LAYER M5 ;
      RECT 51.588 1252.608 51.612 1252.800 ;
    END
  END d[243]
  PIN d[244]
    DIRECTION INPUT ;
    USE SIGNAL ;
    SHAPE ABUTMENT ;
    PORT
      LAYER M5 ;
      RECT 51.780 1252.608 51.804 1252.800 ;
    END
  END d[244]
  PIN d[245]
    DIRECTION INPUT ;
    USE SIGNAL ;
    SHAPE ABUTMENT ;
    PORT
      LAYER M5 ;
      RECT 51.972 1252.608 51.996 1252.800 ;
    END
  END d[245]
  PIN d[246]
    DIRECTION INPUT ;
    USE SIGNAL ;
    SHAPE ABUTMENT ;
    PORT
      LAYER M5 ;
      RECT 52.164 1252.608 52.188 1252.800 ;
    END
  END d[246]
  PIN d[247]
    DIRECTION INPUT ;
    USE SIGNAL ;
    SHAPE ABUTMENT ;
    PORT
      LAYER M5 ;
      RECT 52.356 1252.608 52.380 1252.800 ;
    END
  END d[247]
  PIN d[248]
    DIRECTION INPUT ;
    USE SIGNAL ;
    SHAPE ABUTMENT ;
    PORT
      LAYER M5 ;
      RECT 52.548 1252.608 52.572 1252.800 ;
    END
  END d[248]
  PIN d[249]
    DIRECTION INPUT ;
    USE SIGNAL ;
    SHAPE ABUTMENT ;
    PORT
      LAYER M5 ;
      RECT 52.740 1252.608 52.764 1252.800 ;
    END
  END d[249]
  PIN d[250]
    DIRECTION INPUT ;
    USE SIGNAL ;
    SHAPE ABUTMENT ;
    PORT
      LAYER M5 ;
      RECT 52.932 1252.608 52.956 1252.800 ;
    END
  END d[250]
  PIN d[251]
    DIRECTION INPUT ;
    USE SIGNAL ;
    SHAPE ABUTMENT ;
    PORT
      LAYER M5 ;
      RECT 53.124 1252.608 53.148 1252.800 ;
    END
  END d[251]
  PIN d[252]
    DIRECTION INPUT ;
    USE SIGNAL ;
    SHAPE ABUTMENT ;
    PORT
      LAYER M5 ;
      RECT 53.316 1252.608 53.340 1252.800 ;
    END
  END d[252]
  PIN d[253]
    DIRECTION INPUT ;
    USE SIGNAL ;
    SHAPE ABUTMENT ;
    PORT
      LAYER M5 ;
      RECT 53.508 1252.608 53.532 1252.800 ;
    END
  END d[253]
  PIN d[254]
    DIRECTION INPUT ;
    USE SIGNAL ;
    SHAPE ABUTMENT ;
    PORT
      LAYER M5 ;
      RECT 53.700 1252.608 53.724 1252.800 ;
    END
  END d[254]
  PIN d[255]
    DIRECTION INPUT ;
    USE SIGNAL ;
    SHAPE ABUTMENT ;
    PORT
      LAYER M5 ;
      RECT 53.892 1252.608 53.916 1252.800 ;
    END
  END d[255]
  PIN d[256]
    DIRECTION INPUT ;
    USE SIGNAL ;
    SHAPE ABUTMENT ;
    PORT
      LAYER M5 ;
      RECT 54.084 1252.608 54.108 1252.800 ;
    END
  END d[256]
  PIN d[257]
    DIRECTION INPUT ;
    USE SIGNAL ;
    SHAPE ABUTMENT ;
    PORT
      LAYER M5 ;
      RECT 54.276 1252.608 54.300 1252.800 ;
    END
  END d[257]
  PIN d[258]
    DIRECTION INPUT ;
    USE SIGNAL ;
    SHAPE ABUTMENT ;
    PORT
      LAYER M5 ;
      RECT 54.468 1252.608 54.492 1252.800 ;
    END
  END d[258]
  PIN d[259]
    DIRECTION INPUT ;
    USE SIGNAL ;
    SHAPE ABUTMENT ;
    PORT
      LAYER M5 ;
      RECT 54.660 1252.608 54.684 1252.800 ;
    END
  END d[259]
  PIN d[260]
    DIRECTION INPUT ;
    USE SIGNAL ;
    SHAPE ABUTMENT ;
    PORT
      LAYER M5 ;
      RECT 54.852 1252.608 54.876 1252.800 ;
    END
  END d[260]
  PIN d[261]
    DIRECTION INPUT ;
    USE SIGNAL ;
    SHAPE ABUTMENT ;
    PORT
      LAYER M5 ;
      RECT 55.044 1252.608 55.068 1252.800 ;
    END
  END d[261]
  PIN d[262]
    DIRECTION INPUT ;
    USE SIGNAL ;
    SHAPE ABUTMENT ;
    PORT
      LAYER M5 ;
      RECT 55.236 1252.608 55.260 1252.800 ;
    END
  END d[262]
  PIN d[263]
    DIRECTION INPUT ;
    USE SIGNAL ;
    SHAPE ABUTMENT ;
    PORT
      LAYER M5 ;
      RECT 55.428 1252.608 55.452 1252.800 ;
    END
  END d[263]
  PIN d[264]
    DIRECTION INPUT ;
    USE SIGNAL ;
    SHAPE ABUTMENT ;
    PORT
      LAYER M5 ;
      RECT 55.620 1252.608 55.644 1252.800 ;
    END
  END d[264]
  PIN d[265]
    DIRECTION INPUT ;
    USE SIGNAL ;
    SHAPE ABUTMENT ;
    PORT
      LAYER M5 ;
      RECT 55.812 1252.608 55.836 1252.800 ;
    END
  END d[265]
  PIN d[266]
    DIRECTION INPUT ;
    USE SIGNAL ;
    SHAPE ABUTMENT ;
    PORT
      LAYER M5 ;
      RECT 56.004 1252.608 56.028 1252.800 ;
    END
  END d[266]
  PIN d[267]
    DIRECTION INPUT ;
    USE SIGNAL ;
    SHAPE ABUTMENT ;
    PORT
      LAYER M5 ;
      RECT 56.196 1252.608 56.220 1252.800 ;
    END
  END d[267]
  PIN d[268]
    DIRECTION INPUT ;
    USE SIGNAL ;
    SHAPE ABUTMENT ;
    PORT
      LAYER M5 ;
      RECT 56.388 1252.608 56.412 1252.800 ;
    END
  END d[268]
  PIN d[269]
    DIRECTION INPUT ;
    USE SIGNAL ;
    SHAPE ABUTMENT ;
    PORT
      LAYER M5 ;
      RECT 56.580 1252.608 56.604 1252.800 ;
    END
  END d[269]
  PIN d[270]
    DIRECTION INPUT ;
    USE SIGNAL ;
    SHAPE ABUTMENT ;
    PORT
      LAYER M5 ;
      RECT 56.772 1252.608 56.796 1252.800 ;
    END
  END d[270]
  PIN d[271]
    DIRECTION INPUT ;
    USE SIGNAL ;
    SHAPE ABUTMENT ;
    PORT
      LAYER M5 ;
      RECT 56.964 1252.608 56.988 1252.800 ;
    END
  END d[271]
  PIN d[272]
    DIRECTION INPUT ;
    USE SIGNAL ;
    SHAPE ABUTMENT ;
    PORT
      LAYER M5 ;
      RECT 57.156 1252.608 57.180 1252.800 ;
    END
  END d[272]
  PIN d[273]
    DIRECTION INPUT ;
    USE SIGNAL ;
    SHAPE ABUTMENT ;
    PORT
      LAYER M5 ;
      RECT 57.348 1252.608 57.372 1252.800 ;
    END
  END d[273]
  PIN d[274]
    DIRECTION INPUT ;
    USE SIGNAL ;
    SHAPE ABUTMENT ;
    PORT
      LAYER M5 ;
      RECT 57.540 1252.608 57.564 1252.800 ;
    END
  END d[274]
  PIN d[275]
    DIRECTION INPUT ;
    USE SIGNAL ;
    SHAPE ABUTMENT ;
    PORT
      LAYER M5 ;
      RECT 57.732 1252.608 57.756 1252.800 ;
    END
  END d[275]
  PIN d[276]
    DIRECTION INPUT ;
    USE SIGNAL ;
    SHAPE ABUTMENT ;
    PORT
      LAYER M5 ;
      RECT 57.924 1252.608 57.948 1252.800 ;
    END
  END d[276]
  PIN d[277]
    DIRECTION INPUT ;
    USE SIGNAL ;
    SHAPE ABUTMENT ;
    PORT
      LAYER M5 ;
      RECT 58.116 1252.608 58.140 1252.800 ;
    END
  END d[277]
  PIN d[278]
    DIRECTION INPUT ;
    USE SIGNAL ;
    SHAPE ABUTMENT ;
    PORT
      LAYER M5 ;
      RECT 58.308 1252.608 58.332 1252.800 ;
    END
  END d[278]
  PIN d[279]
    DIRECTION INPUT ;
    USE SIGNAL ;
    SHAPE ABUTMENT ;
    PORT
      LAYER M5 ;
      RECT 58.500 1252.608 58.524 1252.800 ;
    END
  END d[279]
  PIN d[280]
    DIRECTION INPUT ;
    USE SIGNAL ;
    SHAPE ABUTMENT ;
    PORT
      LAYER M5 ;
      RECT 58.692 1252.608 58.716 1252.800 ;
    END
  END d[280]
  PIN d[281]
    DIRECTION INPUT ;
    USE SIGNAL ;
    SHAPE ABUTMENT ;
    PORT
      LAYER M5 ;
      RECT 58.884 1252.608 58.908 1252.800 ;
    END
  END d[281]
  PIN d[282]
    DIRECTION INPUT ;
    USE SIGNAL ;
    SHAPE ABUTMENT ;
    PORT
      LAYER M5 ;
      RECT 59.076 1252.608 59.100 1252.800 ;
    END
  END d[282]
  PIN d[283]
    DIRECTION INPUT ;
    USE SIGNAL ;
    SHAPE ABUTMENT ;
    PORT
      LAYER M5 ;
      RECT 59.268 1252.608 59.292 1252.800 ;
    END
  END d[283]
  PIN d[284]
    DIRECTION INPUT ;
    USE SIGNAL ;
    SHAPE ABUTMENT ;
    PORT
      LAYER M5 ;
      RECT 59.460 1252.608 59.484 1252.800 ;
    END
  END d[284]
  PIN d[285]
    DIRECTION INPUT ;
    USE SIGNAL ;
    SHAPE ABUTMENT ;
    PORT
      LAYER M5 ;
      RECT 59.652 1252.608 59.676 1252.800 ;
    END
  END d[285]
  PIN d[286]
    DIRECTION INPUT ;
    USE SIGNAL ;
    SHAPE ABUTMENT ;
    PORT
      LAYER M5 ;
      RECT 59.844 1252.608 59.868 1252.800 ;
    END
  END d[286]
  PIN d[287]
    DIRECTION INPUT ;
    USE SIGNAL ;
    SHAPE ABUTMENT ;
    PORT
      LAYER M5 ;
      RECT 60.036 1252.608 60.060 1252.800 ;
    END
  END d[287]
  PIN d[288]
    DIRECTION INPUT ;
    USE SIGNAL ;
    SHAPE ABUTMENT ;
    PORT
      LAYER M5 ;
      RECT 60.228 1252.608 60.252 1252.800 ;
    END
  END d[288]
  PIN d[289]
    DIRECTION INPUT ;
    USE SIGNAL ;
    SHAPE ABUTMENT ;
    PORT
      LAYER M5 ;
      RECT 60.420 1252.608 60.444 1252.800 ;
    END
  END d[289]
  PIN d[290]
    DIRECTION INPUT ;
    USE SIGNAL ;
    SHAPE ABUTMENT ;
    PORT
      LAYER M5 ;
      RECT 60.612 1252.608 60.636 1252.800 ;
    END
  END d[290]
  PIN d[291]
    DIRECTION INPUT ;
    USE SIGNAL ;
    SHAPE ABUTMENT ;
    PORT
      LAYER M5 ;
      RECT 60.804 1252.608 60.828 1252.800 ;
    END
  END d[291]
  PIN d[292]
    DIRECTION INPUT ;
    USE SIGNAL ;
    SHAPE ABUTMENT ;
    PORT
      LAYER M5 ;
      RECT 60.996 1252.608 61.020 1252.800 ;
    END
  END d[292]
  PIN d[293]
    DIRECTION INPUT ;
    USE SIGNAL ;
    SHAPE ABUTMENT ;
    PORT
      LAYER M5 ;
      RECT 61.188 1252.608 61.212 1252.800 ;
    END
  END d[293]
  PIN d[294]
    DIRECTION INPUT ;
    USE SIGNAL ;
    SHAPE ABUTMENT ;
    PORT
      LAYER M5 ;
      RECT 61.380 1252.608 61.404 1252.800 ;
    END
  END d[294]
  PIN d[295]
    DIRECTION INPUT ;
    USE SIGNAL ;
    SHAPE ABUTMENT ;
    PORT
      LAYER M5 ;
      RECT 61.572 1252.608 61.596 1252.800 ;
    END
  END d[295]
  PIN d[296]
    DIRECTION INPUT ;
    USE SIGNAL ;
    SHAPE ABUTMENT ;
    PORT
      LAYER M5 ;
      RECT 61.764 1252.608 61.788 1252.800 ;
    END
  END d[296]
  PIN d[297]
    DIRECTION INPUT ;
    USE SIGNAL ;
    SHAPE ABUTMENT ;
    PORT
      LAYER M5 ;
      RECT 61.956 1252.608 61.980 1252.800 ;
    END
  END d[297]
  PIN d[298]
    DIRECTION INPUT ;
    USE SIGNAL ;
    SHAPE ABUTMENT ;
    PORT
      LAYER M5 ;
      RECT 62.148 1252.608 62.172 1252.800 ;
    END
  END d[298]
  PIN d[299]
    DIRECTION INPUT ;
    USE SIGNAL ;
    SHAPE ABUTMENT ;
    PORT
      LAYER M5 ;
      RECT 62.340 1252.608 62.364 1252.800 ;
    END
  END d[299]
  PIN d[300]
    DIRECTION INPUT ;
    USE SIGNAL ;
    SHAPE ABUTMENT ;
    PORT
      LAYER M5 ;
      RECT 62.532 1252.608 62.556 1252.800 ;
    END
  END d[300]
  PIN d[301]
    DIRECTION INPUT ;
    USE SIGNAL ;
    SHAPE ABUTMENT ;
    PORT
      LAYER M5 ;
      RECT 62.724 1252.608 62.748 1252.800 ;
    END
  END d[301]
  PIN d[302]
    DIRECTION INPUT ;
    USE SIGNAL ;
    SHAPE ABUTMENT ;
    PORT
      LAYER M5 ;
      RECT 62.916 1252.608 62.940 1252.800 ;
    END
  END d[302]
  PIN d[303]
    DIRECTION INPUT ;
    USE SIGNAL ;
    SHAPE ABUTMENT ;
    PORT
      LAYER M5 ;
      RECT 63.108 1252.608 63.132 1252.800 ;
    END
  END d[303]
  PIN d[304]
    DIRECTION INPUT ;
    USE SIGNAL ;
    SHAPE ABUTMENT ;
    PORT
      LAYER M5 ;
      RECT 63.300 1252.608 63.324 1252.800 ;
    END
  END d[304]
  PIN d[305]
    DIRECTION INPUT ;
    USE SIGNAL ;
    SHAPE ABUTMENT ;
    PORT
      LAYER M5 ;
      RECT 63.492 1252.608 63.516 1252.800 ;
    END
  END d[305]
  PIN d[306]
    DIRECTION INPUT ;
    USE SIGNAL ;
    SHAPE ABUTMENT ;
    PORT
      LAYER M5 ;
      RECT 63.684 1252.608 63.708 1252.800 ;
    END
  END d[306]
  PIN d[307]
    DIRECTION INPUT ;
    USE SIGNAL ;
    SHAPE ABUTMENT ;
    PORT
      LAYER M5 ;
      RECT 63.876 1252.608 63.900 1252.800 ;
    END
  END d[307]
  PIN d[308]
    DIRECTION INPUT ;
    USE SIGNAL ;
    SHAPE ABUTMENT ;
    PORT
      LAYER M5 ;
      RECT 64.068 1252.608 64.092 1252.800 ;
    END
  END d[308]
  PIN d[309]
    DIRECTION INPUT ;
    USE SIGNAL ;
    SHAPE ABUTMENT ;
    PORT
      LAYER M5 ;
      RECT 64.260 1252.608 64.284 1252.800 ;
    END
  END d[309]
  PIN d[310]
    DIRECTION INPUT ;
    USE SIGNAL ;
    SHAPE ABUTMENT ;
    PORT
      LAYER M5 ;
      RECT 64.452 1252.608 64.476 1252.800 ;
    END
  END d[310]
  PIN d[311]
    DIRECTION INPUT ;
    USE SIGNAL ;
    SHAPE ABUTMENT ;
    PORT
      LAYER M5 ;
      RECT 64.644 1252.608 64.668 1252.800 ;
    END
  END d[311]
  PIN d[312]
    DIRECTION INPUT ;
    USE SIGNAL ;
    SHAPE ABUTMENT ;
    PORT
      LAYER M5 ;
      RECT 64.836 1252.608 64.860 1252.800 ;
    END
  END d[312]
  PIN d[313]
    DIRECTION INPUT ;
    USE SIGNAL ;
    SHAPE ABUTMENT ;
    PORT
      LAYER M5 ;
      RECT 65.028 1252.608 65.052 1252.800 ;
    END
  END d[313]
  PIN d[314]
    DIRECTION INPUT ;
    USE SIGNAL ;
    SHAPE ABUTMENT ;
    PORT
      LAYER M5 ;
      RECT 65.220 1252.608 65.244 1252.800 ;
    END
  END d[314]
  PIN d[315]
    DIRECTION INPUT ;
    USE SIGNAL ;
    SHAPE ABUTMENT ;
    PORT
      LAYER M5 ;
      RECT 65.412 1252.608 65.436 1252.800 ;
    END
  END d[315]
  PIN d[316]
    DIRECTION INPUT ;
    USE SIGNAL ;
    SHAPE ABUTMENT ;
    PORT
      LAYER M5 ;
      RECT 65.604 1252.608 65.628 1252.800 ;
    END
  END d[316]
  PIN d[317]
    DIRECTION INPUT ;
    USE SIGNAL ;
    SHAPE ABUTMENT ;
    PORT
      LAYER M5 ;
      RECT 65.796 1252.608 65.820 1252.800 ;
    END
  END d[317]
  PIN d[318]
    DIRECTION INPUT ;
    USE SIGNAL ;
    SHAPE ABUTMENT ;
    PORT
      LAYER M5 ;
      RECT 65.988 1252.608 66.012 1252.800 ;
    END
  END d[318]
  PIN d[319]
    DIRECTION INPUT ;
    USE SIGNAL ;
    SHAPE ABUTMENT ;
    PORT
      LAYER M5 ;
      RECT 66.180 1252.608 66.204 1252.800 ;
    END
  END d[319]
  PIN d[320]
    DIRECTION INPUT ;
    USE SIGNAL ;
    SHAPE ABUTMENT ;
    PORT
      LAYER M5 ;
      RECT 66.372 1252.608 66.396 1252.800 ;
    END
  END d[320]
  PIN d[321]
    DIRECTION INPUT ;
    USE SIGNAL ;
    SHAPE ABUTMENT ;
    PORT
      LAYER M5 ;
      RECT 66.564 1252.608 66.588 1252.800 ;
    END
  END d[321]
  PIN d[322]
    DIRECTION INPUT ;
    USE SIGNAL ;
    SHAPE ABUTMENT ;
    PORT
      LAYER M5 ;
      RECT 66.756 1252.608 66.780 1252.800 ;
    END
  END d[322]
  PIN d[323]
    DIRECTION INPUT ;
    USE SIGNAL ;
    SHAPE ABUTMENT ;
    PORT
      LAYER M5 ;
      RECT 66.948 1252.608 66.972 1252.800 ;
    END
  END d[323]
  PIN d[324]
    DIRECTION INPUT ;
    USE SIGNAL ;
    SHAPE ABUTMENT ;
    PORT
      LAYER M5 ;
      RECT 67.140 1252.608 67.164 1252.800 ;
    END
  END d[324]
  PIN d[325]
    DIRECTION INPUT ;
    USE SIGNAL ;
    SHAPE ABUTMENT ;
    PORT
      LAYER M5 ;
      RECT 67.332 1252.608 67.356 1252.800 ;
    END
  END d[325]
  PIN d[326]
    DIRECTION INPUT ;
    USE SIGNAL ;
    SHAPE ABUTMENT ;
    PORT
      LAYER M5 ;
      RECT 67.524 1252.608 67.548 1252.800 ;
    END
  END d[326]
  PIN d[327]
    DIRECTION INPUT ;
    USE SIGNAL ;
    SHAPE ABUTMENT ;
    PORT
      LAYER M5 ;
      RECT 67.716 1252.608 67.740 1252.800 ;
    END
  END d[327]
  PIN d[328]
    DIRECTION INPUT ;
    USE SIGNAL ;
    SHAPE ABUTMENT ;
    PORT
      LAYER M5 ;
      RECT 67.908 1252.608 67.932 1252.800 ;
    END
  END d[328]
  PIN d[329]
    DIRECTION INPUT ;
    USE SIGNAL ;
    SHAPE ABUTMENT ;
    PORT
      LAYER M5 ;
      RECT 68.100 1252.608 68.124 1252.800 ;
    END
  END d[329]
  PIN d[330]
    DIRECTION INPUT ;
    USE SIGNAL ;
    SHAPE ABUTMENT ;
    PORT
      LAYER M5 ;
      RECT 68.292 1252.608 68.316 1252.800 ;
    END
  END d[330]
  PIN d[331]
    DIRECTION INPUT ;
    USE SIGNAL ;
    SHAPE ABUTMENT ;
    PORT
      LAYER M5 ;
      RECT 68.484 1252.608 68.508 1252.800 ;
    END
  END d[331]
  PIN d[332]
    DIRECTION INPUT ;
    USE SIGNAL ;
    SHAPE ABUTMENT ;
    PORT
      LAYER M5 ;
      RECT 68.676 1252.608 68.700 1252.800 ;
    END
  END d[332]
  PIN d[333]
    DIRECTION INPUT ;
    USE SIGNAL ;
    SHAPE ABUTMENT ;
    PORT
      LAYER M5 ;
      RECT 68.868 1252.608 68.892 1252.800 ;
    END
  END d[333]
  PIN d[334]
    DIRECTION INPUT ;
    USE SIGNAL ;
    SHAPE ABUTMENT ;
    PORT
      LAYER M5 ;
      RECT 69.060 1252.608 69.084 1252.800 ;
    END
  END d[334]
  PIN d[335]
    DIRECTION INPUT ;
    USE SIGNAL ;
    SHAPE ABUTMENT ;
    PORT
      LAYER M5 ;
      RECT 69.252 1252.608 69.276 1252.800 ;
    END
  END d[335]
  PIN d[336]
    DIRECTION INPUT ;
    USE SIGNAL ;
    SHAPE ABUTMENT ;
    PORT
      LAYER M5 ;
      RECT 69.444 1252.608 69.468 1252.800 ;
    END
  END d[336]
  PIN d[337]
    DIRECTION INPUT ;
    USE SIGNAL ;
    SHAPE ABUTMENT ;
    PORT
      LAYER M5 ;
      RECT 69.636 1252.608 69.660 1252.800 ;
    END
  END d[337]
  PIN d[338]
    DIRECTION INPUT ;
    USE SIGNAL ;
    SHAPE ABUTMENT ;
    PORT
      LAYER M5 ;
      RECT 69.828 1252.608 69.852 1252.800 ;
    END
  END d[338]
  PIN d[339]
    DIRECTION INPUT ;
    USE SIGNAL ;
    SHAPE ABUTMENT ;
    PORT
      LAYER M5 ;
      RECT 70.020 1252.608 70.044 1252.800 ;
    END
  END d[339]
  PIN d[340]
    DIRECTION INPUT ;
    USE SIGNAL ;
    SHAPE ABUTMENT ;
    PORT
      LAYER M5 ;
      RECT 70.212 1252.608 70.236 1252.800 ;
    END
  END d[340]
  PIN d[341]
    DIRECTION INPUT ;
    USE SIGNAL ;
    SHAPE ABUTMENT ;
    PORT
      LAYER M5 ;
      RECT 70.404 1252.608 70.428 1252.800 ;
    END
  END d[341]
  PIN d[342]
    DIRECTION INPUT ;
    USE SIGNAL ;
    SHAPE ABUTMENT ;
    PORT
      LAYER M5 ;
      RECT 70.596 1252.608 70.620 1252.800 ;
    END
  END d[342]
  PIN d[343]
    DIRECTION INPUT ;
    USE SIGNAL ;
    SHAPE ABUTMENT ;
    PORT
      LAYER M5 ;
      RECT 70.788 1252.608 70.812 1252.800 ;
    END
  END d[343]
  PIN d[344]
    DIRECTION INPUT ;
    USE SIGNAL ;
    SHAPE ABUTMENT ;
    PORT
      LAYER M5 ;
      RECT 70.980 1252.608 71.004 1252.800 ;
    END
  END d[344]
  PIN d[345]
    DIRECTION INPUT ;
    USE SIGNAL ;
    SHAPE ABUTMENT ;
    PORT
      LAYER M5 ;
      RECT 71.172 1252.608 71.196 1252.800 ;
    END
  END d[345]
  PIN d[346]
    DIRECTION INPUT ;
    USE SIGNAL ;
    SHAPE ABUTMENT ;
    PORT
      LAYER M5 ;
      RECT 71.364 1252.608 71.388 1252.800 ;
    END
  END d[346]
  PIN d[347]
    DIRECTION INPUT ;
    USE SIGNAL ;
    SHAPE ABUTMENT ;
    PORT
      LAYER M5 ;
      RECT 71.556 1252.608 71.580 1252.800 ;
    END
  END d[347]
  PIN d[348]
    DIRECTION INPUT ;
    USE SIGNAL ;
    SHAPE ABUTMENT ;
    PORT
      LAYER M5 ;
      RECT 71.748 1252.608 71.772 1252.800 ;
    END
  END d[348]
  PIN d[349]
    DIRECTION INPUT ;
    USE SIGNAL ;
    SHAPE ABUTMENT ;
    PORT
      LAYER M5 ;
      RECT 71.940 1252.608 71.964 1252.800 ;
    END
  END d[349]
  PIN d[350]
    DIRECTION INPUT ;
    USE SIGNAL ;
    SHAPE ABUTMENT ;
    PORT
      LAYER M5 ;
      RECT 72.132 1252.608 72.156 1252.800 ;
    END
  END d[350]
  PIN d[351]
    DIRECTION INPUT ;
    USE SIGNAL ;
    SHAPE ABUTMENT ;
    PORT
      LAYER M5 ;
      RECT 72.324 1252.608 72.348 1252.800 ;
    END
  END d[351]
  PIN d[352]
    DIRECTION INPUT ;
    USE SIGNAL ;
    SHAPE ABUTMENT ;
    PORT
      LAYER M5 ;
      RECT 72.516 1252.608 72.540 1252.800 ;
    END
  END d[352]
  PIN d[353]
    DIRECTION INPUT ;
    USE SIGNAL ;
    SHAPE ABUTMENT ;
    PORT
      LAYER M5 ;
      RECT 72.708 1252.608 72.732 1252.800 ;
    END
  END d[353]
  PIN d[354]
    DIRECTION INPUT ;
    USE SIGNAL ;
    SHAPE ABUTMENT ;
    PORT
      LAYER M5 ;
      RECT 72.900 1252.608 72.924 1252.800 ;
    END
  END d[354]
  PIN d[355]
    DIRECTION INPUT ;
    USE SIGNAL ;
    SHAPE ABUTMENT ;
    PORT
      LAYER M5 ;
      RECT 73.092 1252.608 73.116 1252.800 ;
    END
  END d[355]
  PIN d[356]
    DIRECTION INPUT ;
    USE SIGNAL ;
    SHAPE ABUTMENT ;
    PORT
      LAYER M5 ;
      RECT 73.284 1252.608 73.308 1252.800 ;
    END
  END d[356]
  PIN d[357]
    DIRECTION INPUT ;
    USE SIGNAL ;
    SHAPE ABUTMENT ;
    PORT
      LAYER M5 ;
      RECT 73.476 1252.608 73.500 1252.800 ;
    END
  END d[357]
  PIN d[358]
    DIRECTION INPUT ;
    USE SIGNAL ;
    SHAPE ABUTMENT ;
    PORT
      LAYER M5 ;
      RECT 73.668 1252.608 73.692 1252.800 ;
    END
  END d[358]
  PIN d[359]
    DIRECTION INPUT ;
    USE SIGNAL ;
    SHAPE ABUTMENT ;
    PORT
      LAYER M5 ;
      RECT 73.860 1252.608 73.884 1252.800 ;
    END
  END d[359]
  PIN d[360]
    DIRECTION INPUT ;
    USE SIGNAL ;
    SHAPE ABUTMENT ;
    PORT
      LAYER M5 ;
      RECT 74.052 1252.608 74.076 1252.800 ;
    END
  END d[360]
  PIN d[361]
    DIRECTION INPUT ;
    USE SIGNAL ;
    SHAPE ABUTMENT ;
    PORT
      LAYER M5 ;
      RECT 74.244 1252.608 74.268 1252.800 ;
    END
  END d[361]
  PIN d[362]
    DIRECTION INPUT ;
    USE SIGNAL ;
    SHAPE ABUTMENT ;
    PORT
      LAYER M5 ;
      RECT 74.436 1252.608 74.460 1252.800 ;
    END
  END d[362]
  PIN d[363]
    DIRECTION INPUT ;
    USE SIGNAL ;
    SHAPE ABUTMENT ;
    PORT
      LAYER M5 ;
      RECT 74.628 1252.608 74.652 1252.800 ;
    END
  END d[363]
  PIN d[364]
    DIRECTION INPUT ;
    USE SIGNAL ;
    SHAPE ABUTMENT ;
    PORT
      LAYER M5 ;
      RECT 74.820 1252.608 74.844 1252.800 ;
    END
  END d[364]
  PIN d[365]
    DIRECTION INPUT ;
    USE SIGNAL ;
    SHAPE ABUTMENT ;
    PORT
      LAYER M5 ;
      RECT 75.012 1252.608 75.036 1252.800 ;
    END
  END d[365]
  PIN d[366]
    DIRECTION INPUT ;
    USE SIGNAL ;
    SHAPE ABUTMENT ;
    PORT
      LAYER M5 ;
      RECT 75.204 1252.608 75.228 1252.800 ;
    END
  END d[366]
  PIN d[367]
    DIRECTION INPUT ;
    USE SIGNAL ;
    SHAPE ABUTMENT ;
    PORT
      LAYER M5 ;
      RECT 75.396 1252.608 75.420 1252.800 ;
    END
  END d[367]
  PIN d[368]
    DIRECTION INPUT ;
    USE SIGNAL ;
    SHAPE ABUTMENT ;
    PORT
      LAYER M5 ;
      RECT 75.588 1252.608 75.612 1252.800 ;
    END
  END d[368]
  PIN d[369]
    DIRECTION INPUT ;
    USE SIGNAL ;
    SHAPE ABUTMENT ;
    PORT
      LAYER M5 ;
      RECT 75.780 1252.608 75.804 1252.800 ;
    END
  END d[369]
  PIN d[370]
    DIRECTION INPUT ;
    USE SIGNAL ;
    SHAPE ABUTMENT ;
    PORT
      LAYER M5 ;
      RECT 75.972 1252.608 75.996 1252.800 ;
    END
  END d[370]
  PIN d[371]
    DIRECTION INPUT ;
    USE SIGNAL ;
    SHAPE ABUTMENT ;
    PORT
      LAYER M5 ;
      RECT 76.164 1252.608 76.188 1252.800 ;
    END
  END d[371]
  PIN d[372]
    DIRECTION INPUT ;
    USE SIGNAL ;
    SHAPE ABUTMENT ;
    PORT
      LAYER M5 ;
      RECT 76.356 1252.608 76.380 1252.800 ;
    END
  END d[372]
  PIN d[373]
    DIRECTION INPUT ;
    USE SIGNAL ;
    SHAPE ABUTMENT ;
    PORT
      LAYER M5 ;
      RECT 76.548 1252.608 76.572 1252.800 ;
    END
  END d[373]
  PIN d[374]
    DIRECTION INPUT ;
    USE SIGNAL ;
    SHAPE ABUTMENT ;
    PORT
      LAYER M5 ;
      RECT 76.740 1252.608 76.764 1252.800 ;
    END
  END d[374]
  PIN d[375]
    DIRECTION INPUT ;
    USE SIGNAL ;
    SHAPE ABUTMENT ;
    PORT
      LAYER M5 ;
      RECT 76.932 1252.608 76.956 1252.800 ;
    END
  END d[375]
  PIN d[376]
    DIRECTION INPUT ;
    USE SIGNAL ;
    SHAPE ABUTMENT ;
    PORT
      LAYER M5 ;
      RECT 77.124 1252.608 77.148 1252.800 ;
    END
  END d[376]
  PIN d[377]
    DIRECTION INPUT ;
    USE SIGNAL ;
    SHAPE ABUTMENT ;
    PORT
      LAYER M5 ;
      RECT 77.316 1252.608 77.340 1252.800 ;
    END
  END d[377]
  PIN d[378]
    DIRECTION INPUT ;
    USE SIGNAL ;
    SHAPE ABUTMENT ;
    PORT
      LAYER M5 ;
      RECT 77.508 1252.608 77.532 1252.800 ;
    END
  END d[378]
  PIN d[379]
    DIRECTION INPUT ;
    USE SIGNAL ;
    SHAPE ABUTMENT ;
    PORT
      LAYER M5 ;
      RECT 77.700 1252.608 77.724 1252.800 ;
    END
  END d[379]
  PIN d[380]
    DIRECTION INPUT ;
    USE SIGNAL ;
    SHAPE ABUTMENT ;
    PORT
      LAYER M5 ;
      RECT 77.892 1252.608 77.916 1252.800 ;
    END
  END d[380]
  PIN d[381]
    DIRECTION INPUT ;
    USE SIGNAL ;
    SHAPE ABUTMENT ;
    PORT
      LAYER M5 ;
      RECT 78.084 1252.608 78.108 1252.800 ;
    END
  END d[381]
  PIN d[382]
    DIRECTION INPUT ;
    USE SIGNAL ;
    SHAPE ABUTMENT ;
    PORT
      LAYER M5 ;
      RECT 78.276 1252.608 78.300 1252.800 ;
    END
  END d[382]
  PIN d[383]
    DIRECTION INPUT ;
    USE SIGNAL ;
    SHAPE ABUTMENT ;
    PORT
      LAYER M5 ;
      RECT 78.468 1252.608 78.492 1252.800 ;
    END
  END d[383]
  PIN d[384]
    DIRECTION INPUT ;
    USE SIGNAL ;
    SHAPE ABUTMENT ;
    PORT
      LAYER M5 ;
      RECT 78.660 1252.608 78.684 1252.800 ;
    END
  END d[384]
  PIN d[385]
    DIRECTION INPUT ;
    USE SIGNAL ;
    SHAPE ABUTMENT ;
    PORT
      LAYER M5 ;
      RECT 78.852 1252.608 78.876 1252.800 ;
    END
  END d[385]
  PIN d[386]
    DIRECTION INPUT ;
    USE SIGNAL ;
    SHAPE ABUTMENT ;
    PORT
      LAYER M5 ;
      RECT 79.044 1252.608 79.068 1252.800 ;
    END
  END d[386]
  PIN d[387]
    DIRECTION INPUT ;
    USE SIGNAL ;
    SHAPE ABUTMENT ;
    PORT
      LAYER M5 ;
      RECT 79.236 1252.608 79.260 1252.800 ;
    END
  END d[387]
  PIN d[388]
    DIRECTION INPUT ;
    USE SIGNAL ;
    SHAPE ABUTMENT ;
    PORT
      LAYER M5 ;
      RECT 79.428 1252.608 79.452 1252.800 ;
    END
  END d[388]
  PIN d[389]
    DIRECTION INPUT ;
    USE SIGNAL ;
    SHAPE ABUTMENT ;
    PORT
      LAYER M5 ;
      RECT 79.620 1252.608 79.644 1252.800 ;
    END
  END d[389]
  PIN d[390]
    DIRECTION INPUT ;
    USE SIGNAL ;
    SHAPE ABUTMENT ;
    PORT
      LAYER M5 ;
      RECT 79.812 1252.608 79.836 1252.800 ;
    END
  END d[390]
  PIN d[391]
    DIRECTION INPUT ;
    USE SIGNAL ;
    SHAPE ABUTMENT ;
    PORT
      LAYER M5 ;
      RECT 80.004 1252.608 80.028 1252.800 ;
    END
  END d[391]
  PIN d[392]
    DIRECTION INPUT ;
    USE SIGNAL ;
    SHAPE ABUTMENT ;
    PORT
      LAYER M5 ;
      RECT 80.196 1252.608 80.220 1252.800 ;
    END
  END d[392]
  PIN d[393]
    DIRECTION INPUT ;
    USE SIGNAL ;
    SHAPE ABUTMENT ;
    PORT
      LAYER M5 ;
      RECT 80.388 1252.608 80.412 1252.800 ;
    END
  END d[393]
  PIN d[394]
    DIRECTION INPUT ;
    USE SIGNAL ;
    SHAPE ABUTMENT ;
    PORT
      LAYER M5 ;
      RECT 80.580 1252.608 80.604 1252.800 ;
    END
  END d[394]
  PIN d[395]
    DIRECTION INPUT ;
    USE SIGNAL ;
    SHAPE ABUTMENT ;
    PORT
      LAYER M5 ;
      RECT 80.772 1252.608 80.796 1252.800 ;
    END
  END d[395]
  PIN d[396]
    DIRECTION INPUT ;
    USE SIGNAL ;
    SHAPE ABUTMENT ;
    PORT
      LAYER M5 ;
      RECT 80.964 1252.608 80.988 1252.800 ;
    END
  END d[396]
  PIN d[397]
    DIRECTION INPUT ;
    USE SIGNAL ;
    SHAPE ABUTMENT ;
    PORT
      LAYER M5 ;
      RECT 81.156 1252.608 81.180 1252.800 ;
    END
  END d[397]
  PIN d[398]
    DIRECTION INPUT ;
    USE SIGNAL ;
    SHAPE ABUTMENT ;
    PORT
      LAYER M5 ;
      RECT 81.348 1252.608 81.372 1252.800 ;
    END
  END d[398]
  PIN d[399]
    DIRECTION INPUT ;
    USE SIGNAL ;
    SHAPE ABUTMENT ;
    PORT
      LAYER M5 ;
      RECT 81.540 1252.608 81.564 1252.800 ;
    END
  END d[399]
  PIN d[400]
    DIRECTION INPUT ;
    USE SIGNAL ;
    SHAPE ABUTMENT ;
    PORT
      LAYER M5 ;
      RECT 81.732 1252.608 81.756 1252.800 ;
    END
  END d[400]
  PIN d[401]
    DIRECTION INPUT ;
    USE SIGNAL ;
    SHAPE ABUTMENT ;
    PORT
      LAYER M5 ;
      RECT 81.924 1252.608 81.948 1252.800 ;
    END
  END d[401]
  PIN d[402]
    DIRECTION INPUT ;
    USE SIGNAL ;
    SHAPE ABUTMENT ;
    PORT
      LAYER M5 ;
      RECT 82.116 1252.608 82.140 1252.800 ;
    END
  END d[402]
  PIN d[403]
    DIRECTION INPUT ;
    USE SIGNAL ;
    SHAPE ABUTMENT ;
    PORT
      LAYER M5 ;
      RECT 82.308 1252.608 82.332 1252.800 ;
    END
  END d[403]
  PIN d[404]
    DIRECTION INPUT ;
    USE SIGNAL ;
    SHAPE ABUTMENT ;
    PORT
      LAYER M5 ;
      RECT 82.500 1252.608 82.524 1252.800 ;
    END
  END d[404]
  PIN d[405]
    DIRECTION INPUT ;
    USE SIGNAL ;
    SHAPE ABUTMENT ;
    PORT
      LAYER M5 ;
      RECT 82.692 1252.608 82.716 1252.800 ;
    END
  END d[405]
  PIN d[406]
    DIRECTION INPUT ;
    USE SIGNAL ;
    SHAPE ABUTMENT ;
    PORT
      LAYER M5 ;
      RECT 82.884 1252.608 82.908 1252.800 ;
    END
  END d[406]
  PIN d[407]
    DIRECTION INPUT ;
    USE SIGNAL ;
    SHAPE ABUTMENT ;
    PORT
      LAYER M5 ;
      RECT 83.076 1252.608 83.100 1252.800 ;
    END
  END d[407]
  PIN d[408]
    DIRECTION INPUT ;
    USE SIGNAL ;
    SHAPE ABUTMENT ;
    PORT
      LAYER M5 ;
      RECT 83.268 1252.608 83.292 1252.800 ;
    END
  END d[408]
  PIN d[409]
    DIRECTION INPUT ;
    USE SIGNAL ;
    SHAPE ABUTMENT ;
    PORT
      LAYER M5 ;
      RECT 83.460 1252.608 83.484 1252.800 ;
    END
  END d[409]
  PIN d[410]
    DIRECTION INPUT ;
    USE SIGNAL ;
    SHAPE ABUTMENT ;
    PORT
      LAYER M5 ;
      RECT 83.652 1252.608 83.676 1252.800 ;
    END
  END d[410]
  PIN d[411]
    DIRECTION INPUT ;
    USE SIGNAL ;
    SHAPE ABUTMENT ;
    PORT
      LAYER M5 ;
      RECT 83.844 1252.608 83.868 1252.800 ;
    END
  END d[411]
  PIN d[412]
    DIRECTION INPUT ;
    USE SIGNAL ;
    SHAPE ABUTMENT ;
    PORT
      LAYER M5 ;
      RECT 84.036 1252.608 84.060 1252.800 ;
    END
  END d[412]
  PIN d[413]
    DIRECTION INPUT ;
    USE SIGNAL ;
    SHAPE ABUTMENT ;
    PORT
      LAYER M5 ;
      RECT 84.228 1252.608 84.252 1252.800 ;
    END
  END d[413]
  PIN d[414]
    DIRECTION INPUT ;
    USE SIGNAL ;
    SHAPE ABUTMENT ;
    PORT
      LAYER M5 ;
      RECT 84.420 1252.608 84.444 1252.800 ;
    END
  END d[414]
  PIN d[415]
    DIRECTION INPUT ;
    USE SIGNAL ;
    SHAPE ABUTMENT ;
    PORT
      LAYER M5 ;
      RECT 84.612 1252.608 84.636 1252.800 ;
    END
  END d[415]
  PIN d[416]
    DIRECTION INPUT ;
    USE SIGNAL ;
    SHAPE ABUTMENT ;
    PORT
      LAYER M5 ;
      RECT 84.804 1252.608 84.828 1252.800 ;
    END
  END d[416]
  PIN d[417]
    DIRECTION INPUT ;
    USE SIGNAL ;
    SHAPE ABUTMENT ;
    PORT
      LAYER M5 ;
      RECT 84.996 1252.608 85.020 1252.800 ;
    END
  END d[417]
  PIN d[418]
    DIRECTION INPUT ;
    USE SIGNAL ;
    SHAPE ABUTMENT ;
    PORT
      LAYER M5 ;
      RECT 85.188 1252.608 85.212 1252.800 ;
    END
  END d[418]
  PIN d[419]
    DIRECTION INPUT ;
    USE SIGNAL ;
    SHAPE ABUTMENT ;
    PORT
      LAYER M5 ;
      RECT 85.380 1252.608 85.404 1252.800 ;
    END
  END d[419]
  PIN d[420]
    DIRECTION INPUT ;
    USE SIGNAL ;
    SHAPE ABUTMENT ;
    PORT
      LAYER M5 ;
      RECT 85.572 1252.608 85.596 1252.800 ;
    END
  END d[420]
  PIN d[421]
    DIRECTION INPUT ;
    USE SIGNAL ;
    SHAPE ABUTMENT ;
    PORT
      LAYER M5 ;
      RECT 85.764 1252.608 85.788 1252.800 ;
    END
  END d[421]
  PIN d[422]
    DIRECTION INPUT ;
    USE SIGNAL ;
    SHAPE ABUTMENT ;
    PORT
      LAYER M5 ;
      RECT 85.956 1252.608 85.980 1252.800 ;
    END
  END d[422]
  PIN d[423]
    DIRECTION INPUT ;
    USE SIGNAL ;
    SHAPE ABUTMENT ;
    PORT
      LAYER M5 ;
      RECT 86.148 1252.608 86.172 1252.800 ;
    END
  END d[423]
  PIN d[424]
    DIRECTION INPUT ;
    USE SIGNAL ;
    SHAPE ABUTMENT ;
    PORT
      LAYER M5 ;
      RECT 86.340 1252.608 86.364 1252.800 ;
    END
  END d[424]
  PIN d[425]
    DIRECTION INPUT ;
    USE SIGNAL ;
    SHAPE ABUTMENT ;
    PORT
      LAYER M5 ;
      RECT 86.532 1252.608 86.556 1252.800 ;
    END
  END d[425]
  PIN d[426]
    DIRECTION INPUT ;
    USE SIGNAL ;
    SHAPE ABUTMENT ;
    PORT
      LAYER M5 ;
      RECT 86.724 1252.608 86.748 1252.800 ;
    END
  END d[426]
  PIN d[427]
    DIRECTION INPUT ;
    USE SIGNAL ;
    SHAPE ABUTMENT ;
    PORT
      LAYER M5 ;
      RECT 86.916 1252.608 86.940 1252.800 ;
    END
  END d[427]
  PIN d[428]
    DIRECTION INPUT ;
    USE SIGNAL ;
    SHAPE ABUTMENT ;
    PORT
      LAYER M5 ;
      RECT 87.108 1252.608 87.132 1252.800 ;
    END
  END d[428]
  PIN d[429]
    DIRECTION INPUT ;
    USE SIGNAL ;
    SHAPE ABUTMENT ;
    PORT
      LAYER M5 ;
      RECT 87.300 1252.608 87.324 1252.800 ;
    END
  END d[429]
  PIN d[430]
    DIRECTION INPUT ;
    USE SIGNAL ;
    SHAPE ABUTMENT ;
    PORT
      LAYER M5 ;
      RECT 87.492 1252.608 87.516 1252.800 ;
    END
  END d[430]
  PIN d[431]
    DIRECTION INPUT ;
    USE SIGNAL ;
    SHAPE ABUTMENT ;
    PORT
      LAYER M5 ;
      RECT 87.684 1252.608 87.708 1252.800 ;
    END
  END d[431]
  PIN d[432]
    DIRECTION INPUT ;
    USE SIGNAL ;
    SHAPE ABUTMENT ;
    PORT
      LAYER M5 ;
      RECT 87.876 1252.608 87.900 1252.800 ;
    END
  END d[432]
  PIN d[433]
    DIRECTION INPUT ;
    USE SIGNAL ;
    SHAPE ABUTMENT ;
    PORT
      LAYER M5 ;
      RECT 88.068 1252.608 88.092 1252.800 ;
    END
  END d[433]
  PIN d[434]
    DIRECTION INPUT ;
    USE SIGNAL ;
    SHAPE ABUTMENT ;
    PORT
      LAYER M5 ;
      RECT 88.260 1252.608 88.284 1252.800 ;
    END
  END d[434]
  PIN d[435]
    DIRECTION INPUT ;
    USE SIGNAL ;
    SHAPE ABUTMENT ;
    PORT
      LAYER M5 ;
      RECT 88.452 1252.608 88.476 1252.800 ;
    END
  END d[435]
  PIN d[436]
    DIRECTION INPUT ;
    USE SIGNAL ;
    SHAPE ABUTMENT ;
    PORT
      LAYER M5 ;
      RECT 88.644 1252.608 88.668 1252.800 ;
    END
  END d[436]
  PIN d[437]
    DIRECTION INPUT ;
    USE SIGNAL ;
    SHAPE ABUTMENT ;
    PORT
      LAYER M5 ;
      RECT 88.836 1252.608 88.860 1252.800 ;
    END
  END d[437]
  PIN d[438]
    DIRECTION INPUT ;
    USE SIGNAL ;
    SHAPE ABUTMENT ;
    PORT
      LAYER M5 ;
      RECT 89.028 1252.608 89.052 1252.800 ;
    END
  END d[438]
  PIN d[439]
    DIRECTION INPUT ;
    USE SIGNAL ;
    SHAPE ABUTMENT ;
    PORT
      LAYER M5 ;
      RECT 89.220 1252.608 89.244 1252.800 ;
    END
  END d[439]
  PIN d[440]
    DIRECTION INPUT ;
    USE SIGNAL ;
    SHAPE ABUTMENT ;
    PORT
      LAYER M5 ;
      RECT 89.412 1252.608 89.436 1252.800 ;
    END
  END d[440]
  PIN d[441]
    DIRECTION INPUT ;
    USE SIGNAL ;
    SHAPE ABUTMENT ;
    PORT
      LAYER M5 ;
      RECT 89.604 1252.608 89.628 1252.800 ;
    END
  END d[441]
  PIN d[442]
    DIRECTION INPUT ;
    USE SIGNAL ;
    SHAPE ABUTMENT ;
    PORT
      LAYER M5 ;
      RECT 89.796 1252.608 89.820 1252.800 ;
    END
  END d[442]
  PIN d[443]
    DIRECTION INPUT ;
    USE SIGNAL ;
    SHAPE ABUTMENT ;
    PORT
      LAYER M5 ;
      RECT 89.988 1252.608 90.012 1252.800 ;
    END
  END d[443]
  PIN d[444]
    DIRECTION INPUT ;
    USE SIGNAL ;
    SHAPE ABUTMENT ;
    PORT
      LAYER M5 ;
      RECT 90.180 1252.608 90.204 1252.800 ;
    END
  END d[444]
  PIN d[445]
    DIRECTION INPUT ;
    USE SIGNAL ;
    SHAPE ABUTMENT ;
    PORT
      LAYER M5 ;
      RECT 90.372 1252.608 90.396 1252.800 ;
    END
  END d[445]
  PIN d[446]
    DIRECTION INPUT ;
    USE SIGNAL ;
    SHAPE ABUTMENT ;
    PORT
      LAYER M5 ;
      RECT 90.564 1252.608 90.588 1252.800 ;
    END
  END d[446]
  PIN d[447]
    DIRECTION INPUT ;
    USE SIGNAL ;
    SHAPE ABUTMENT ;
    PORT
      LAYER M5 ;
      RECT 90.756 1252.608 90.780 1252.800 ;
    END
  END d[447]
  PIN d[448]
    DIRECTION INPUT ;
    USE SIGNAL ;
    SHAPE ABUTMENT ;
    PORT
      LAYER M5 ;
      RECT 90.948 1252.608 90.972 1252.800 ;
    END
  END d[448]
  PIN d[449]
    DIRECTION INPUT ;
    USE SIGNAL ;
    SHAPE ABUTMENT ;
    PORT
      LAYER M5 ;
      RECT 91.140 1252.608 91.164 1252.800 ;
    END
  END d[449]
  PIN d[450]
    DIRECTION INPUT ;
    USE SIGNAL ;
    SHAPE ABUTMENT ;
    PORT
      LAYER M5 ;
      RECT 91.332 1252.608 91.356 1252.800 ;
    END
  END d[450]
  PIN d[451]
    DIRECTION INPUT ;
    USE SIGNAL ;
    SHAPE ABUTMENT ;
    PORT
      LAYER M5 ;
      RECT 91.524 1252.608 91.548 1252.800 ;
    END
  END d[451]
  PIN d[452]
    DIRECTION INPUT ;
    USE SIGNAL ;
    SHAPE ABUTMENT ;
    PORT
      LAYER M5 ;
      RECT 91.716 1252.608 91.740 1252.800 ;
    END
  END d[452]
  PIN d[453]
    DIRECTION INPUT ;
    USE SIGNAL ;
    SHAPE ABUTMENT ;
    PORT
      LAYER M5 ;
      RECT 91.908 1252.608 91.932 1252.800 ;
    END
  END d[453]
  PIN d[454]
    DIRECTION INPUT ;
    USE SIGNAL ;
    SHAPE ABUTMENT ;
    PORT
      LAYER M5 ;
      RECT 92.100 1252.608 92.124 1252.800 ;
    END
  END d[454]
  PIN d[455]
    DIRECTION INPUT ;
    USE SIGNAL ;
    SHAPE ABUTMENT ;
    PORT
      LAYER M5 ;
      RECT 92.292 1252.608 92.316 1252.800 ;
    END
  END d[455]
  PIN d[456]
    DIRECTION INPUT ;
    USE SIGNAL ;
    SHAPE ABUTMENT ;
    PORT
      LAYER M5 ;
      RECT 92.484 1252.608 92.508 1252.800 ;
    END
  END d[456]
  PIN d[457]
    DIRECTION INPUT ;
    USE SIGNAL ;
    SHAPE ABUTMENT ;
    PORT
      LAYER M5 ;
      RECT 92.676 1252.608 92.700 1252.800 ;
    END
  END d[457]
  PIN d[458]
    DIRECTION INPUT ;
    USE SIGNAL ;
    SHAPE ABUTMENT ;
    PORT
      LAYER M5 ;
      RECT 92.868 1252.608 92.892 1252.800 ;
    END
  END d[458]
  PIN d[459]
    DIRECTION INPUT ;
    USE SIGNAL ;
    SHAPE ABUTMENT ;
    PORT
      LAYER M5 ;
      RECT 93.060 1252.608 93.084 1252.800 ;
    END
  END d[459]
  PIN d[460]
    DIRECTION INPUT ;
    USE SIGNAL ;
    SHAPE ABUTMENT ;
    PORT
      LAYER M5 ;
      RECT 93.252 1252.608 93.276 1252.800 ;
    END
  END d[460]
  PIN d[461]
    DIRECTION INPUT ;
    USE SIGNAL ;
    SHAPE ABUTMENT ;
    PORT
      LAYER M5 ;
      RECT 93.444 1252.608 93.468 1252.800 ;
    END
  END d[461]
  PIN d[462]
    DIRECTION INPUT ;
    USE SIGNAL ;
    SHAPE ABUTMENT ;
    PORT
      LAYER M5 ;
      RECT 93.636 1252.608 93.660 1252.800 ;
    END
  END d[462]
  PIN d[463]
    DIRECTION INPUT ;
    USE SIGNAL ;
    SHAPE ABUTMENT ;
    PORT
      LAYER M5 ;
      RECT 93.828 1252.608 93.852 1252.800 ;
    END
  END d[463]
  PIN d[464]
    DIRECTION INPUT ;
    USE SIGNAL ;
    SHAPE ABUTMENT ;
    PORT
      LAYER M5 ;
      RECT 94.020 1252.608 94.044 1252.800 ;
    END
  END d[464]
  PIN d[465]
    DIRECTION INPUT ;
    USE SIGNAL ;
    SHAPE ABUTMENT ;
    PORT
      LAYER M5 ;
      RECT 94.212 1252.608 94.236 1252.800 ;
    END
  END d[465]
  PIN d[466]
    DIRECTION INPUT ;
    USE SIGNAL ;
    SHAPE ABUTMENT ;
    PORT
      LAYER M5 ;
      RECT 94.404 1252.608 94.428 1252.800 ;
    END
  END d[466]
  PIN d[467]
    DIRECTION INPUT ;
    USE SIGNAL ;
    SHAPE ABUTMENT ;
    PORT
      LAYER M5 ;
      RECT 94.596 1252.608 94.620 1252.800 ;
    END
  END d[467]
  PIN d[468]
    DIRECTION INPUT ;
    USE SIGNAL ;
    SHAPE ABUTMENT ;
    PORT
      LAYER M5 ;
      RECT 94.788 1252.608 94.812 1252.800 ;
    END
  END d[468]
  PIN d[469]
    DIRECTION INPUT ;
    USE SIGNAL ;
    SHAPE ABUTMENT ;
    PORT
      LAYER M5 ;
      RECT 94.980 1252.608 95.004 1252.800 ;
    END
  END d[469]
  PIN d[470]
    DIRECTION INPUT ;
    USE SIGNAL ;
    SHAPE ABUTMENT ;
    PORT
      LAYER M5 ;
      RECT 95.172 1252.608 95.196 1252.800 ;
    END
  END d[470]
  PIN d[471]
    DIRECTION INPUT ;
    USE SIGNAL ;
    SHAPE ABUTMENT ;
    PORT
      LAYER M5 ;
      RECT 95.364 1252.608 95.388 1252.800 ;
    END
  END d[471]
  PIN d[472]
    DIRECTION INPUT ;
    USE SIGNAL ;
    SHAPE ABUTMENT ;
    PORT
      LAYER M5 ;
      RECT 95.556 1252.608 95.580 1252.800 ;
    END
  END d[472]
  PIN d[473]
    DIRECTION INPUT ;
    USE SIGNAL ;
    SHAPE ABUTMENT ;
    PORT
      LAYER M5 ;
      RECT 95.748 1252.608 95.772 1252.800 ;
    END
  END d[473]
  PIN d[474]
    DIRECTION INPUT ;
    USE SIGNAL ;
    SHAPE ABUTMENT ;
    PORT
      LAYER M5 ;
      RECT 95.940 1252.608 95.964 1252.800 ;
    END
  END d[474]
  PIN d[475]
    DIRECTION INPUT ;
    USE SIGNAL ;
    SHAPE ABUTMENT ;
    PORT
      LAYER M5 ;
      RECT 96.132 1252.608 96.156 1252.800 ;
    END
  END d[475]
  PIN d[476]
    DIRECTION INPUT ;
    USE SIGNAL ;
    SHAPE ABUTMENT ;
    PORT
      LAYER M5 ;
      RECT 96.324 1252.608 96.348 1252.800 ;
    END
  END d[476]
  PIN d[477]
    DIRECTION INPUT ;
    USE SIGNAL ;
    SHAPE ABUTMENT ;
    PORT
      LAYER M5 ;
      RECT 96.516 1252.608 96.540 1252.800 ;
    END
  END d[477]
  PIN d[478]
    DIRECTION INPUT ;
    USE SIGNAL ;
    SHAPE ABUTMENT ;
    PORT
      LAYER M5 ;
      RECT 96.708 1252.608 96.732 1252.800 ;
    END
  END d[478]
  PIN d[479]
    DIRECTION INPUT ;
    USE SIGNAL ;
    SHAPE ABUTMENT ;
    PORT
      LAYER M5 ;
      RECT 96.900 1252.608 96.924 1252.800 ;
    END
  END d[479]
  PIN d[480]
    DIRECTION INPUT ;
    USE SIGNAL ;
    SHAPE ABUTMENT ;
    PORT
      LAYER M5 ;
      RECT 97.092 1252.608 97.116 1252.800 ;
    END
  END d[480]
  PIN d[481]
    DIRECTION INPUT ;
    USE SIGNAL ;
    SHAPE ABUTMENT ;
    PORT
      LAYER M5 ;
      RECT 97.284 1252.608 97.308 1252.800 ;
    END
  END d[481]
  PIN d[482]
    DIRECTION INPUT ;
    USE SIGNAL ;
    SHAPE ABUTMENT ;
    PORT
      LAYER M5 ;
      RECT 97.476 1252.608 97.500 1252.800 ;
    END
  END d[482]
  PIN d[483]
    DIRECTION INPUT ;
    USE SIGNAL ;
    SHAPE ABUTMENT ;
    PORT
      LAYER M5 ;
      RECT 97.668 1252.608 97.692 1252.800 ;
    END
  END d[483]
  PIN d[484]
    DIRECTION INPUT ;
    USE SIGNAL ;
    SHAPE ABUTMENT ;
    PORT
      LAYER M5 ;
      RECT 97.860 1252.608 97.884 1252.800 ;
    END
  END d[484]
  PIN d[485]
    DIRECTION INPUT ;
    USE SIGNAL ;
    SHAPE ABUTMENT ;
    PORT
      LAYER M5 ;
      RECT 98.052 1252.608 98.076 1252.800 ;
    END
  END d[485]
  PIN d[486]
    DIRECTION INPUT ;
    USE SIGNAL ;
    SHAPE ABUTMENT ;
    PORT
      LAYER M5 ;
      RECT 98.244 1252.608 98.268 1252.800 ;
    END
  END d[486]
  PIN d[487]
    DIRECTION INPUT ;
    USE SIGNAL ;
    SHAPE ABUTMENT ;
    PORT
      LAYER M5 ;
      RECT 98.436 1252.608 98.460 1252.800 ;
    END
  END d[487]
  PIN d[488]
    DIRECTION INPUT ;
    USE SIGNAL ;
    SHAPE ABUTMENT ;
    PORT
      LAYER M5 ;
      RECT 98.628 1252.608 98.652 1252.800 ;
    END
  END d[488]
  PIN d[489]
    DIRECTION INPUT ;
    USE SIGNAL ;
    SHAPE ABUTMENT ;
    PORT
      LAYER M5 ;
      RECT 98.820 1252.608 98.844 1252.800 ;
    END
  END d[489]
  PIN d[490]
    DIRECTION INPUT ;
    USE SIGNAL ;
    SHAPE ABUTMENT ;
    PORT
      LAYER M5 ;
      RECT 99.012 1252.608 99.036 1252.800 ;
    END
  END d[490]
  PIN d[491]
    DIRECTION INPUT ;
    USE SIGNAL ;
    SHAPE ABUTMENT ;
    PORT
      LAYER M5 ;
      RECT 99.204 1252.608 99.228 1252.800 ;
    END
  END d[491]
  PIN d[492]
    DIRECTION INPUT ;
    USE SIGNAL ;
    SHAPE ABUTMENT ;
    PORT
      LAYER M5 ;
      RECT 99.396 1252.608 99.420 1252.800 ;
    END
  END d[492]
  PIN d[493]
    DIRECTION INPUT ;
    USE SIGNAL ;
    SHAPE ABUTMENT ;
    PORT
      LAYER M5 ;
      RECT 99.588 1252.608 99.612 1252.800 ;
    END
  END d[493]
  PIN d[494]
    DIRECTION INPUT ;
    USE SIGNAL ;
    SHAPE ABUTMENT ;
    PORT
      LAYER M5 ;
      RECT 99.780 1252.608 99.804 1252.800 ;
    END
  END d[494]
  PIN d[495]
    DIRECTION INPUT ;
    USE SIGNAL ;
    SHAPE ABUTMENT ;
    PORT
      LAYER M5 ;
      RECT 99.972 1252.608 99.996 1252.800 ;
    END
  END d[495]
  PIN d[496]
    DIRECTION INPUT ;
    USE SIGNAL ;
    SHAPE ABUTMENT ;
    PORT
      LAYER M5 ;
      RECT 100.164 1252.608 100.188 1252.800 ;
    END
  END d[496]
  PIN d[497]
    DIRECTION INPUT ;
    USE SIGNAL ;
    SHAPE ABUTMENT ;
    PORT
      LAYER M5 ;
      RECT 100.356 1252.608 100.380 1252.800 ;
    END
  END d[497]
  PIN d[498]
    DIRECTION INPUT ;
    USE SIGNAL ;
    SHAPE ABUTMENT ;
    PORT
      LAYER M5 ;
      RECT 100.548 1252.608 100.572 1252.800 ;
    END
  END d[498]
  PIN d[499]
    DIRECTION INPUT ;
    USE SIGNAL ;
    SHAPE ABUTMENT ;
    PORT
      LAYER M5 ;
      RECT 100.740 1252.608 100.764 1252.800 ;
    END
  END d[499]
  PIN d[500]
    DIRECTION INPUT ;
    USE SIGNAL ;
    SHAPE ABUTMENT ;
    PORT
      LAYER M5 ;
      RECT 100.932 1252.608 100.956 1252.800 ;
    END
  END d[500]
  PIN d[501]
    DIRECTION INPUT ;
    USE SIGNAL ;
    SHAPE ABUTMENT ;
    PORT
      LAYER M5 ;
      RECT 101.124 1252.608 101.148 1252.800 ;
    END
  END d[501]
  PIN d[502]
    DIRECTION INPUT ;
    USE SIGNAL ;
    SHAPE ABUTMENT ;
    PORT
      LAYER M5 ;
      RECT 101.316 1252.608 101.340 1252.800 ;
    END
  END d[502]
  PIN d[503]
    DIRECTION INPUT ;
    USE SIGNAL ;
    SHAPE ABUTMENT ;
    PORT
      LAYER M5 ;
      RECT 101.508 1252.608 101.532 1252.800 ;
    END
  END d[503]
  PIN d[504]
    DIRECTION INPUT ;
    USE SIGNAL ;
    SHAPE ABUTMENT ;
    PORT
      LAYER M5 ;
      RECT 101.700 1252.608 101.724 1252.800 ;
    END
  END d[504]
  PIN d[505]
    DIRECTION INPUT ;
    USE SIGNAL ;
    SHAPE ABUTMENT ;
    PORT
      LAYER M5 ;
      RECT 101.892 1252.608 101.916 1252.800 ;
    END
  END d[505]
  PIN d[506]
    DIRECTION INPUT ;
    USE SIGNAL ;
    SHAPE ABUTMENT ;
    PORT
      LAYER M5 ;
      RECT 102.084 1252.608 102.108 1252.800 ;
    END
  END d[506]
  PIN d[507]
    DIRECTION INPUT ;
    USE SIGNAL ;
    SHAPE ABUTMENT ;
    PORT
      LAYER M5 ;
      RECT 102.276 1252.608 102.300 1252.800 ;
    END
  END d[507]
  PIN d[508]
    DIRECTION INPUT ;
    USE SIGNAL ;
    SHAPE ABUTMENT ;
    PORT
      LAYER M5 ;
      RECT 102.468 1252.608 102.492 1252.800 ;
    END
  END d[508]
  PIN d[509]
    DIRECTION INPUT ;
    USE SIGNAL ;
    SHAPE ABUTMENT ;
    PORT
      LAYER M5 ;
      RECT 102.660 1252.608 102.684 1252.800 ;
    END
  END d[509]
  PIN d[510]
    DIRECTION INPUT ;
    USE SIGNAL ;
    SHAPE ABUTMENT ;
    PORT
      LAYER M5 ;
      RECT 102.852 1252.608 102.876 1252.800 ;
    END
  END d[510]
  PIN d[511]
    DIRECTION INPUT ;
    USE SIGNAL ;
    SHAPE ABUTMENT ;
    PORT
      LAYER M5 ;
      RECT 103.044 1252.608 103.068 1252.800 ;
    END
  END d[511]
  PIN d[512]
    DIRECTION INPUT ;
    USE SIGNAL ;
    SHAPE ABUTMENT ;
    PORT
      LAYER M5 ;
      RECT 103.236 1252.608 103.260 1252.800 ;
    END
  END d[512]
  PIN pma_tx[0]
    DIRECTION OUTPUT ;
    USE SIGNAL ;
    SHAPE ABUTMENT ;
    PORT
      LAYER M5 ;
      RECT 4.740 0.000 4.764 0.192 ;
    END
  END pma_tx[0]
  PIN pma_tx[1]
    DIRECTION OUTPUT ;
    USE SIGNAL ;
    SHAPE ABUTMENT ;
    PORT
      LAYER M5 ;
      RECT 4.932 0.000 4.956 0.192 ;
    END
  END pma_tx[1]
  PIN pma_tx[2]
    DIRECTION OUTPUT ;
    USE SIGNAL ;
    SHAPE ABUTMENT ;
    PORT
      LAYER M5 ;
      RECT 5.124 0.000 5.148 0.192 ;
    END
  END pma_tx[2]
  PIN pma_tx[3]
    DIRECTION OUTPUT ;
    USE SIGNAL ;
    SHAPE ABUTMENT ;
    PORT
      LAYER M5 ;
      RECT 5.316 0.000 5.340 0.192 ;
    END
  END pma_tx[3]
  PIN pma_tx[4]
    DIRECTION OUTPUT ;
    USE SIGNAL ;
    SHAPE ABUTMENT ;
    PORT
      LAYER M5 ;
      RECT 5.508 0.000 5.532 0.192 ;
    END
  END pma_tx[4]
  PIN pma_tx[5]
    DIRECTION OUTPUT ;
    USE SIGNAL ;
    SHAPE ABUTMENT ;
    PORT
      LAYER M5 ;
      RECT 5.700 0.000 5.724 0.192 ;
    END
  END pma_tx[5]
  PIN pma_tx[6]
    DIRECTION OUTPUT ;
    USE SIGNAL ;
    SHAPE ABUTMENT ;
    PORT
      LAYER M5 ;
      RECT 5.892 0.000 5.916 0.192 ;
    END
  END pma_tx[6]
  PIN pma_tx[7]
    DIRECTION OUTPUT ;
    USE SIGNAL ;
    SHAPE ABUTMENT ;
    PORT
      LAYER M5 ;
      RECT 6.084 0.000 6.108 0.192 ;
    END
  END pma_tx[7]
  PIN pma_tx[8]
    DIRECTION OUTPUT ;
    USE SIGNAL ;
    SHAPE ABUTMENT ;
    PORT
      LAYER M5 ;
      RECT 6.276 0.000 6.300 0.192 ;
    END
  END pma_tx[8]
  PIN pma_tx[9]
    DIRECTION OUTPUT ;
    USE SIGNAL ;
    SHAPE ABUTMENT ;
    PORT
      LAYER M5 ;
      RECT 6.468 0.000 6.492 0.192 ;
    END
  END pma_tx[9]
  PIN pma_tx[10]
    DIRECTION OUTPUT ;
    USE SIGNAL ;
    SHAPE ABUTMENT ;
    PORT
      LAYER M5 ;
      RECT 6.660 0.000 6.684 0.192 ;
    END
  END pma_tx[10]
  PIN pma_tx[11]
    DIRECTION OUTPUT ;
    USE SIGNAL ;
    SHAPE ABUTMENT ;
    PORT
      LAYER M5 ;
      RECT 6.852 0.000 6.876 0.192 ;
    END
  END pma_tx[11]
  PIN pma_tx[12]
    DIRECTION OUTPUT ;
    USE SIGNAL ;
    SHAPE ABUTMENT ;
    PORT
      LAYER M5 ;
      RECT 7.044 0.000 7.068 0.192 ;
    END
  END pma_tx[12]
  PIN pma_tx[13]
    DIRECTION OUTPUT ;
    USE SIGNAL ;
    SHAPE ABUTMENT ;
    PORT
      LAYER M5 ;
      RECT 7.236 0.000 7.260 0.192 ;
    END
  END pma_tx[13]
  PIN pma_tx[14]
    DIRECTION OUTPUT ;
    USE SIGNAL ;
    SHAPE ABUTMENT ;
    PORT
      LAYER M5 ;
      RECT 7.428 0.000 7.452 0.192 ;
    END
  END pma_tx[14]
  PIN pma_tx[15]
    DIRECTION OUTPUT ;
    USE SIGNAL ;
    SHAPE ABUTMENT ;
    PORT
      LAYER M5 ;
      RECT 7.620 0.000 7.644 0.192 ;
    END
  END pma_tx[15]
  PIN pma_tx[16]
    DIRECTION OUTPUT ;
    USE SIGNAL ;
    SHAPE ABUTMENT ;
    PORT
      LAYER M5 ;
      RECT 7.812 0.000 7.836 0.192 ;
    END
  END pma_tx[16]
  PIN pma_tx[17]
    DIRECTION OUTPUT ;
    USE SIGNAL ;
    SHAPE ABUTMENT ;
    PORT
      LAYER M5 ;
      RECT 8.004 0.000 8.028 0.192 ;
    END
  END pma_tx[17]
  PIN pma_tx[18]
    DIRECTION OUTPUT ;
    USE SIGNAL ;
    SHAPE ABUTMENT ;
    PORT
      LAYER M5 ;
      RECT 8.196 0.000 8.220 0.192 ;
    END
  END pma_tx[18]
  PIN pma_tx[19]
    DIRECTION OUTPUT ;
    USE SIGNAL ;
    SHAPE ABUTMENT ;
    PORT
      LAYER M5 ;
      RECT 8.388 0.000 8.412 0.192 ;
    END
  END pma_tx[19]
  PIN pma_tx[20]
    DIRECTION OUTPUT ;
    USE SIGNAL ;
    SHAPE ABUTMENT ;
    PORT
      LAYER M5 ;
      RECT 8.580 0.000 8.604 0.192 ;
    END
  END pma_tx[20]
  PIN pma_tx[21]
    DIRECTION OUTPUT ;
    USE SIGNAL ;
    SHAPE ABUTMENT ;
    PORT
      LAYER M5 ;
      RECT 8.772 0.000 8.796 0.192 ;
    END
  END pma_tx[21]
  PIN pma_tx[22]
    DIRECTION OUTPUT ;
    USE SIGNAL ;
    SHAPE ABUTMENT ;
    PORT
      LAYER M5 ;
      RECT 8.964 0.000 8.988 0.192 ;
    END
  END pma_tx[22]
  PIN pma_tx[23]
    DIRECTION OUTPUT ;
    USE SIGNAL ;
    SHAPE ABUTMENT ;
    PORT
      LAYER M5 ;
      RECT 9.156 0.000 9.180 0.192 ;
    END
  END pma_tx[23]
  PIN pma_tx[24]
    DIRECTION OUTPUT ;
    USE SIGNAL ;
    SHAPE ABUTMENT ;
    PORT
      LAYER M5 ;
      RECT 9.348 0.000 9.372 0.192 ;
    END
  END pma_tx[24]
  PIN pma_tx[25]
    DIRECTION OUTPUT ;
    USE SIGNAL ;
    SHAPE ABUTMENT ;
    PORT
      LAYER M5 ;
      RECT 9.540 0.000 9.564 0.192 ;
    END
  END pma_tx[25]
  PIN pma_tx[26]
    DIRECTION OUTPUT ;
    USE SIGNAL ;
    SHAPE ABUTMENT ;
    PORT
      LAYER M5 ;
      RECT 9.732 0.000 9.756 0.192 ;
    END
  END pma_tx[26]
  PIN pma_tx[27]
    DIRECTION OUTPUT ;
    USE SIGNAL ;
    SHAPE ABUTMENT ;
    PORT
      LAYER M5 ;
      RECT 9.924 0.000 9.948 0.192 ;
    END
  END pma_tx[27]
  PIN pma_tx[28]
    DIRECTION OUTPUT ;
    USE SIGNAL ;
    SHAPE ABUTMENT ;
    PORT
      LAYER M5 ;
      RECT 10.116 0.000 10.140 0.192 ;
    END
  END pma_tx[28]
  PIN pma_tx[29]
    DIRECTION OUTPUT ;
    USE SIGNAL ;
    SHAPE ABUTMENT ;
    PORT
      LAYER M5 ;
      RECT 10.308 0.000 10.332 0.192 ;
    END
  END pma_tx[29]
  PIN pma_tx[30]
    DIRECTION OUTPUT ;
    USE SIGNAL ;
    SHAPE ABUTMENT ;
    PORT
      LAYER M5 ;
      RECT 10.500 0.000 10.524 0.192 ;
    END
  END pma_tx[30]
  PIN pma_tx[31]
    DIRECTION OUTPUT ;
    USE SIGNAL ;
    SHAPE ABUTMENT ;
    PORT
      LAYER M5 ;
      RECT 10.692 0.000 10.716 0.192 ;
    END
  END pma_tx[31]
  PIN pma_tx[32]
    DIRECTION OUTPUT ;
    USE SIGNAL ;
    SHAPE ABUTMENT ;
    PORT
      LAYER M5 ;
      RECT 10.884 0.000 10.908 0.192 ;
    END
  END pma_tx[32]
  PIN pma_tx[33]
    DIRECTION OUTPUT ;
    USE SIGNAL ;
    SHAPE ABUTMENT ;
    PORT
      LAYER M5 ;
      RECT 11.076 0.000 11.100 0.192 ;
    END
  END pma_tx[33]
  PIN pma_tx[34]
    DIRECTION OUTPUT ;
    USE SIGNAL ;
    SHAPE ABUTMENT ;
    PORT
      LAYER M5 ;
      RECT 11.268 0.000 11.292 0.192 ;
    END
  END pma_tx[34]
  PIN pma_tx[35]
    DIRECTION OUTPUT ;
    USE SIGNAL ;
    SHAPE ABUTMENT ;
    PORT
      LAYER M5 ;
      RECT 11.460 0.000 11.484 0.192 ;
    END
  END pma_tx[35]
  PIN pma_tx[36]
    DIRECTION OUTPUT ;
    USE SIGNAL ;
    SHAPE ABUTMENT ;
    PORT
      LAYER M5 ;
      RECT 11.652 0.000 11.676 0.192 ;
    END
  END pma_tx[36]
  PIN pma_tx[37]
    DIRECTION OUTPUT ;
    USE SIGNAL ;
    SHAPE ABUTMENT ;
    PORT
      LAYER M5 ;
      RECT 11.844 0.000 11.868 0.192 ;
    END
  END pma_tx[37]
  PIN pma_tx[38]
    DIRECTION OUTPUT ;
    USE SIGNAL ;
    SHAPE ABUTMENT ;
    PORT
      LAYER M5 ;
      RECT 12.036 0.000 12.060 0.192 ;
    END
  END pma_tx[38]
  PIN pma_tx[39]
    DIRECTION OUTPUT ;
    USE SIGNAL ;
    SHAPE ABUTMENT ;
    PORT
      LAYER M5 ;
      RECT 12.228 0.000 12.252 0.192 ;
    END
  END pma_tx[39]
  PIN pma_tx[40]
    DIRECTION OUTPUT ;
    USE SIGNAL ;
    SHAPE ABUTMENT ;
    PORT
      LAYER M5 ;
      RECT 12.420 0.000 12.444 0.192 ;
    END
  END pma_tx[40]
  PIN pma_tx[41]
    DIRECTION OUTPUT ;
    USE SIGNAL ;
    SHAPE ABUTMENT ;
    PORT
      LAYER M5 ;
      RECT 12.612 0.000 12.636 0.192 ;
    END
  END pma_tx[41]
  PIN pma_tx[42]
    DIRECTION OUTPUT ;
    USE SIGNAL ;
    SHAPE ABUTMENT ;
    PORT
      LAYER M5 ;
      RECT 12.804 0.000 12.828 0.192 ;
    END
  END pma_tx[42]
  PIN pma_tx[43]
    DIRECTION OUTPUT ;
    USE SIGNAL ;
    SHAPE ABUTMENT ;
    PORT
      LAYER M5 ;
      RECT 12.996 0.000 13.020 0.192 ;
    END
  END pma_tx[43]
  PIN pma_tx[44]
    DIRECTION OUTPUT ;
    USE SIGNAL ;
    SHAPE ABUTMENT ;
    PORT
      LAYER M5 ;
      RECT 13.188 0.000 13.212 0.192 ;
    END
  END pma_tx[44]
  PIN pma_tx[45]
    DIRECTION OUTPUT ;
    USE SIGNAL ;
    SHAPE ABUTMENT ;
    PORT
      LAYER M5 ;
      RECT 13.380 0.000 13.404 0.192 ;
    END
  END pma_tx[45]
  PIN pma_tx[46]
    DIRECTION OUTPUT ;
    USE SIGNAL ;
    SHAPE ABUTMENT ;
    PORT
      LAYER M5 ;
      RECT 13.572 0.000 13.596 0.192 ;
    END
  END pma_tx[46]
  PIN pma_tx[47]
    DIRECTION OUTPUT ;
    USE SIGNAL ;
    SHAPE ABUTMENT ;
    PORT
      LAYER M5 ;
      RECT 13.764 0.000 13.788 0.192 ;
    END
  END pma_tx[47]
  PIN pma_tx[48]
    DIRECTION OUTPUT ;
    USE SIGNAL ;
    SHAPE ABUTMENT ;
    PORT
      LAYER M5 ;
      RECT 13.956 0.000 13.980 0.192 ;
    END
  END pma_tx[48]
  PIN pma_tx[49]
    DIRECTION OUTPUT ;
    USE SIGNAL ;
    SHAPE ABUTMENT ;
    PORT
      LAYER M5 ;
      RECT 14.148 0.000 14.172 0.192 ;
    END
  END pma_tx[49]
  PIN pma_tx[50]
    DIRECTION OUTPUT ;
    USE SIGNAL ;
    SHAPE ABUTMENT ;
    PORT
      LAYER M5 ;
      RECT 14.340 0.000 14.364 0.192 ;
    END
  END pma_tx[50]
  PIN pma_tx[51]
    DIRECTION OUTPUT ;
    USE SIGNAL ;
    SHAPE ABUTMENT ;
    PORT
      LAYER M5 ;
      RECT 14.532 0.000 14.556 0.192 ;
    END
  END pma_tx[51]
  PIN pma_tx[52]
    DIRECTION OUTPUT ;
    USE SIGNAL ;
    SHAPE ABUTMENT ;
    PORT
      LAYER M5 ;
      RECT 14.724 0.000 14.748 0.192 ;
    END
  END pma_tx[52]
  PIN pma_tx[53]
    DIRECTION OUTPUT ;
    USE SIGNAL ;
    SHAPE ABUTMENT ;
    PORT
      LAYER M5 ;
      RECT 14.916 0.000 14.940 0.192 ;
    END
  END pma_tx[53]
  PIN pma_tx[54]
    DIRECTION OUTPUT ;
    USE SIGNAL ;
    SHAPE ABUTMENT ;
    PORT
      LAYER M5 ;
      RECT 15.108 0.000 15.132 0.192 ;
    END
  END pma_tx[54]
  PIN pma_tx[55]
    DIRECTION OUTPUT ;
    USE SIGNAL ;
    SHAPE ABUTMENT ;
    PORT
      LAYER M5 ;
      RECT 15.300 0.000 15.324 0.192 ;
    END
  END pma_tx[55]
  PIN pma_tx[56]
    DIRECTION OUTPUT ;
    USE SIGNAL ;
    SHAPE ABUTMENT ;
    PORT
      LAYER M5 ;
      RECT 15.492 0.000 15.516 0.192 ;
    END
  END pma_tx[56]
  PIN pma_tx[57]
    DIRECTION OUTPUT ;
    USE SIGNAL ;
    SHAPE ABUTMENT ;
    PORT
      LAYER M5 ;
      RECT 15.684 0.000 15.708 0.192 ;
    END
  END pma_tx[57]
  PIN pma_tx[58]
    DIRECTION OUTPUT ;
    USE SIGNAL ;
    SHAPE ABUTMENT ;
    PORT
      LAYER M5 ;
      RECT 15.876 0.000 15.900 0.192 ;
    END
  END pma_tx[58]
  PIN pma_tx[59]
    DIRECTION OUTPUT ;
    USE SIGNAL ;
    SHAPE ABUTMENT ;
    PORT
      LAYER M5 ;
      RECT 16.068 0.000 16.092 0.192 ;
    END
  END pma_tx[59]
  PIN pma_tx[60]
    DIRECTION OUTPUT ;
    USE SIGNAL ;
    SHAPE ABUTMENT ;
    PORT
      LAYER M5 ;
      RECT 16.260 0.000 16.284 0.192 ;
    END
  END pma_tx[60]
  PIN pma_tx[61]
    DIRECTION OUTPUT ;
    USE SIGNAL ;
    SHAPE ABUTMENT ;
    PORT
      LAYER M5 ;
      RECT 16.452 0.000 16.476 0.192 ;
    END
  END pma_tx[61]
  PIN pma_tx[62]
    DIRECTION OUTPUT ;
    USE SIGNAL ;
    SHAPE ABUTMENT ;
    PORT
      LAYER M5 ;
      RECT 16.644 0.000 16.668 0.192 ;
    END
  END pma_tx[62]
  PIN pma_tx[63]
    DIRECTION OUTPUT ;
    USE SIGNAL ;
    SHAPE ABUTMENT ;
    PORT
      LAYER M5 ;
      RECT 16.836 0.000 16.860 0.192 ;
    END
  END pma_tx[63]
  PIN pma_tx[64]
    DIRECTION OUTPUT ;
    USE SIGNAL ;
    SHAPE ABUTMENT ;
    PORT
      LAYER M5 ;
      RECT 17.028 0.000 17.052 0.192 ;
    END
  END pma_tx[64]
  PIN pma_tx[65]
    DIRECTION OUTPUT ;
    USE SIGNAL ;
    SHAPE ABUTMENT ;
    PORT
      LAYER M5 ;
      RECT 17.220 0.000 17.244 0.192 ;
    END
  END pma_tx[65]
  PIN pma_tx[66]
    DIRECTION OUTPUT ;
    USE SIGNAL ;
    SHAPE ABUTMENT ;
    PORT
      LAYER M5 ;
      RECT 17.412 0.000 17.436 0.192 ;
    END
  END pma_tx[66]
  PIN pma_tx[67]
    DIRECTION OUTPUT ;
    USE SIGNAL ;
    SHAPE ABUTMENT ;
    PORT
      LAYER M5 ;
      RECT 17.604 0.000 17.628 0.192 ;
    END
  END pma_tx[67]
  PIN pma_tx[68]
    DIRECTION OUTPUT ;
    USE SIGNAL ;
    SHAPE ABUTMENT ;
    PORT
      LAYER M5 ;
      RECT 17.796 0.000 17.820 0.192 ;
    END
  END pma_tx[68]
  PIN pma_tx[69]
    DIRECTION OUTPUT ;
    USE SIGNAL ;
    SHAPE ABUTMENT ;
    PORT
      LAYER M5 ;
      RECT 17.988 0.000 18.012 0.192 ;
    END
  END pma_tx[69]
  PIN pma_tx[70]
    DIRECTION OUTPUT ;
    USE SIGNAL ;
    SHAPE ABUTMENT ;
    PORT
      LAYER M5 ;
      RECT 18.180 0.000 18.204 0.192 ;
    END
  END pma_tx[70]
  PIN pma_tx[71]
    DIRECTION OUTPUT ;
    USE SIGNAL ;
    SHAPE ABUTMENT ;
    PORT
      LAYER M5 ;
      RECT 18.372 0.000 18.396 0.192 ;
    END
  END pma_tx[71]
  PIN pma_tx[72]
    DIRECTION OUTPUT ;
    USE SIGNAL ;
    SHAPE ABUTMENT ;
    PORT
      LAYER M5 ;
      RECT 18.564 0.000 18.588 0.192 ;
    END
  END pma_tx[72]
  PIN pma_tx[73]
    DIRECTION OUTPUT ;
    USE SIGNAL ;
    SHAPE ABUTMENT ;
    PORT
      LAYER M5 ;
      RECT 18.756 0.000 18.780 0.192 ;
    END
  END pma_tx[73]
  PIN pma_tx[74]
    DIRECTION OUTPUT ;
    USE SIGNAL ;
    SHAPE ABUTMENT ;
    PORT
      LAYER M5 ;
      RECT 18.948 0.000 18.972 0.192 ;
    END
  END pma_tx[74]
  PIN pma_tx[75]
    DIRECTION OUTPUT ;
    USE SIGNAL ;
    SHAPE ABUTMENT ;
    PORT
      LAYER M5 ;
      RECT 19.140 0.000 19.164 0.192 ;
    END
  END pma_tx[75]
  PIN pma_tx[76]
    DIRECTION OUTPUT ;
    USE SIGNAL ;
    SHAPE ABUTMENT ;
    PORT
      LAYER M5 ;
      RECT 19.332 0.000 19.356 0.192 ;
    END
  END pma_tx[76]
  PIN pma_tx[77]
    DIRECTION OUTPUT ;
    USE SIGNAL ;
    SHAPE ABUTMENT ;
    PORT
      LAYER M5 ;
      RECT 19.524 0.000 19.548 0.192 ;
    END
  END pma_tx[77]
  PIN pma_tx[78]
    DIRECTION OUTPUT ;
    USE SIGNAL ;
    SHAPE ABUTMENT ;
    PORT
      LAYER M5 ;
      RECT 19.716 0.000 19.740 0.192 ;
    END
  END pma_tx[78]
  PIN pma_tx[79]
    DIRECTION OUTPUT ;
    USE SIGNAL ;
    SHAPE ABUTMENT ;
    PORT
      LAYER M5 ;
      RECT 19.908 0.000 19.932 0.192 ;
    END
  END pma_tx[79]
  PIN pma_tx[80]
    DIRECTION OUTPUT ;
    USE SIGNAL ;
    SHAPE ABUTMENT ;
    PORT
      LAYER M5 ;
      RECT 20.100 0.000 20.124 0.192 ;
    END
  END pma_tx[80]
  PIN pma_tx[81]
    DIRECTION OUTPUT ;
    USE SIGNAL ;
    SHAPE ABUTMENT ;
    PORT
      LAYER M5 ;
      RECT 20.292 0.000 20.316 0.192 ;
    END
  END pma_tx[81]
  PIN pma_tx[82]
    DIRECTION OUTPUT ;
    USE SIGNAL ;
    SHAPE ABUTMENT ;
    PORT
      LAYER M5 ;
      RECT 20.484 0.000 20.508 0.192 ;
    END
  END pma_tx[82]
  PIN pma_tx[83]
    DIRECTION OUTPUT ;
    USE SIGNAL ;
    SHAPE ABUTMENT ;
    PORT
      LAYER M5 ;
      RECT 20.676 0.000 20.700 0.192 ;
    END
  END pma_tx[83]
  PIN pma_tx[84]
    DIRECTION OUTPUT ;
    USE SIGNAL ;
    SHAPE ABUTMENT ;
    PORT
      LAYER M5 ;
      RECT 20.868 0.000 20.892 0.192 ;
    END
  END pma_tx[84]
  PIN pma_tx[85]
    DIRECTION OUTPUT ;
    USE SIGNAL ;
    SHAPE ABUTMENT ;
    PORT
      LAYER M5 ;
      RECT 21.060 0.000 21.084 0.192 ;
    END
  END pma_tx[85]
  PIN pma_tx[86]
    DIRECTION OUTPUT ;
    USE SIGNAL ;
    SHAPE ABUTMENT ;
    PORT
      LAYER M5 ;
      RECT 21.252 0.000 21.276 0.192 ;
    END
  END pma_tx[86]
  PIN pma_tx[87]
    DIRECTION OUTPUT ;
    USE SIGNAL ;
    SHAPE ABUTMENT ;
    PORT
      LAYER M5 ;
      RECT 21.444 0.000 21.468 0.192 ;
    END
  END pma_tx[87]
  PIN pma_tx[88]
    DIRECTION OUTPUT ;
    USE SIGNAL ;
    SHAPE ABUTMENT ;
    PORT
      LAYER M5 ;
      RECT 21.636 0.000 21.660 0.192 ;
    END
  END pma_tx[88]
  PIN pma_tx[89]
    DIRECTION OUTPUT ;
    USE SIGNAL ;
    SHAPE ABUTMENT ;
    PORT
      LAYER M5 ;
      RECT 21.828 0.000 21.852 0.192 ;
    END
  END pma_tx[89]
  PIN pma_tx[90]
    DIRECTION OUTPUT ;
    USE SIGNAL ;
    SHAPE ABUTMENT ;
    PORT
      LAYER M5 ;
      RECT 22.020 0.000 22.044 0.192 ;
    END
  END pma_tx[90]
  PIN pma_tx[91]
    DIRECTION OUTPUT ;
    USE SIGNAL ;
    SHAPE ABUTMENT ;
    PORT
      LAYER M5 ;
      RECT 22.212 0.000 22.236 0.192 ;
    END
  END pma_tx[91]
  PIN pma_tx[92]
    DIRECTION OUTPUT ;
    USE SIGNAL ;
    SHAPE ABUTMENT ;
    PORT
      LAYER M5 ;
      RECT 22.404 0.000 22.428 0.192 ;
    END
  END pma_tx[92]
  PIN pma_tx[93]
    DIRECTION OUTPUT ;
    USE SIGNAL ;
    SHAPE ABUTMENT ;
    PORT
      LAYER M5 ;
      RECT 22.596 0.000 22.620 0.192 ;
    END
  END pma_tx[93]
  PIN pma_tx[94]
    DIRECTION OUTPUT ;
    USE SIGNAL ;
    SHAPE ABUTMENT ;
    PORT
      LAYER M5 ;
      RECT 22.788 0.000 22.812 0.192 ;
    END
  END pma_tx[94]
  PIN pma_tx[95]
    DIRECTION OUTPUT ;
    USE SIGNAL ;
    SHAPE ABUTMENT ;
    PORT
      LAYER M5 ;
      RECT 22.980 0.000 23.004 0.192 ;
    END
  END pma_tx[95]
  PIN pma_tx[96]
    DIRECTION OUTPUT ;
    USE SIGNAL ;
    SHAPE ABUTMENT ;
    PORT
      LAYER M5 ;
      RECT 23.172 0.000 23.196 0.192 ;
    END
  END pma_tx[96]
  PIN pma_tx[97]
    DIRECTION OUTPUT ;
    USE SIGNAL ;
    SHAPE ABUTMENT ;
    PORT
      LAYER M5 ;
      RECT 23.364 0.000 23.388 0.192 ;
    END
  END pma_tx[97]
  PIN pma_tx[98]
    DIRECTION OUTPUT ;
    USE SIGNAL ;
    SHAPE ABUTMENT ;
    PORT
      LAYER M5 ;
      RECT 23.556 0.000 23.580 0.192 ;
    END
  END pma_tx[98]
  PIN pma_tx[99]
    DIRECTION OUTPUT ;
    USE SIGNAL ;
    SHAPE ABUTMENT ;
    PORT
      LAYER M5 ;
      RECT 23.748 0.000 23.772 0.192 ;
    END
  END pma_tx[99]
  PIN pma_tx[100]
    DIRECTION OUTPUT ;
    USE SIGNAL ;
    SHAPE ABUTMENT ;
    PORT
      LAYER M5 ;
      RECT 23.940 0.000 23.964 0.192 ;
    END
  END pma_tx[100]
  PIN pma_tx[101]
    DIRECTION OUTPUT ;
    USE SIGNAL ;
    SHAPE ABUTMENT ;
    PORT
      LAYER M5 ;
      RECT 24.132 0.000 24.156 0.192 ;
    END
  END pma_tx[101]
  PIN pma_tx[102]
    DIRECTION OUTPUT ;
    USE SIGNAL ;
    SHAPE ABUTMENT ;
    PORT
      LAYER M5 ;
      RECT 24.324 0.000 24.348 0.192 ;
    END
  END pma_tx[102]
  PIN pma_tx[103]
    DIRECTION OUTPUT ;
    USE SIGNAL ;
    SHAPE ABUTMENT ;
    PORT
      LAYER M5 ;
      RECT 24.516 0.000 24.540 0.192 ;
    END
  END pma_tx[103]
  PIN pma_tx[104]
    DIRECTION OUTPUT ;
    USE SIGNAL ;
    SHAPE ABUTMENT ;
    PORT
      LAYER M5 ;
      RECT 24.708 0.000 24.732 0.192 ;
    END
  END pma_tx[104]
  PIN pma_tx[105]
    DIRECTION OUTPUT ;
    USE SIGNAL ;
    SHAPE ABUTMENT ;
    PORT
      LAYER M5 ;
      RECT 24.900 0.000 24.924 0.192 ;
    END
  END pma_tx[105]
  PIN pma_tx[106]
    DIRECTION OUTPUT ;
    USE SIGNAL ;
    SHAPE ABUTMENT ;
    PORT
      LAYER M5 ;
      RECT 25.092 0.000 25.116 0.192 ;
    END
  END pma_tx[106]
  PIN pma_tx[107]
    DIRECTION OUTPUT ;
    USE SIGNAL ;
    SHAPE ABUTMENT ;
    PORT
      LAYER M5 ;
      RECT 25.284 0.000 25.308 0.192 ;
    END
  END pma_tx[107]
  PIN pma_tx[108]
    DIRECTION OUTPUT ;
    USE SIGNAL ;
    SHAPE ABUTMENT ;
    PORT
      LAYER M5 ;
      RECT 25.476 0.000 25.500 0.192 ;
    END
  END pma_tx[108]
  PIN pma_tx[109]
    DIRECTION OUTPUT ;
    USE SIGNAL ;
    SHAPE ABUTMENT ;
    PORT
      LAYER M5 ;
      RECT 25.668 0.000 25.692 0.192 ;
    END
  END pma_tx[109]
  PIN pma_tx[110]
    DIRECTION OUTPUT ;
    USE SIGNAL ;
    SHAPE ABUTMENT ;
    PORT
      LAYER M5 ;
      RECT 25.860 0.000 25.884 0.192 ;
    END
  END pma_tx[110]
  PIN pma_tx[111]
    DIRECTION OUTPUT ;
    USE SIGNAL ;
    SHAPE ABUTMENT ;
    PORT
      LAYER M5 ;
      RECT 26.052 0.000 26.076 0.192 ;
    END
  END pma_tx[111]
  PIN pma_tx[112]
    DIRECTION OUTPUT ;
    USE SIGNAL ;
    SHAPE ABUTMENT ;
    PORT
      LAYER M5 ;
      RECT 26.244 0.000 26.268 0.192 ;
    END
  END pma_tx[112]
  PIN pma_tx[113]
    DIRECTION OUTPUT ;
    USE SIGNAL ;
    SHAPE ABUTMENT ;
    PORT
      LAYER M5 ;
      RECT 26.436 0.000 26.460 0.192 ;
    END
  END pma_tx[113]
  PIN pma_tx[114]
    DIRECTION OUTPUT ;
    USE SIGNAL ;
    SHAPE ABUTMENT ;
    PORT
      LAYER M5 ;
      RECT 26.628 0.000 26.652 0.192 ;
    END
  END pma_tx[114]
  PIN pma_tx[115]
    DIRECTION OUTPUT ;
    USE SIGNAL ;
    SHAPE ABUTMENT ;
    PORT
      LAYER M5 ;
      RECT 26.820 0.000 26.844 0.192 ;
    END
  END pma_tx[115]
  PIN pma_tx[116]
    DIRECTION OUTPUT ;
    USE SIGNAL ;
    SHAPE ABUTMENT ;
    PORT
      LAYER M5 ;
      RECT 27.012 0.000 27.036 0.192 ;
    END
  END pma_tx[116]
  PIN pma_tx[117]
    DIRECTION OUTPUT ;
    USE SIGNAL ;
    SHAPE ABUTMENT ;
    PORT
      LAYER M5 ;
      RECT 27.204 0.000 27.228 0.192 ;
    END
  END pma_tx[117]
  PIN pma_tx[118]
    DIRECTION OUTPUT ;
    USE SIGNAL ;
    SHAPE ABUTMENT ;
    PORT
      LAYER M5 ;
      RECT 27.396 0.000 27.420 0.192 ;
    END
  END pma_tx[118]
  PIN pma_tx[119]
    DIRECTION OUTPUT ;
    USE SIGNAL ;
    SHAPE ABUTMENT ;
    PORT
      LAYER M5 ;
      RECT 27.588 0.000 27.612 0.192 ;
    END
  END pma_tx[119]
  PIN pma_tx[120]
    DIRECTION OUTPUT ;
    USE SIGNAL ;
    SHAPE ABUTMENT ;
    PORT
      LAYER M5 ;
      RECT 27.780 0.000 27.804 0.192 ;
    END
  END pma_tx[120]
  PIN pma_tx[121]
    DIRECTION OUTPUT ;
    USE SIGNAL ;
    SHAPE ABUTMENT ;
    PORT
      LAYER M5 ;
      RECT 27.972 0.000 27.996 0.192 ;
    END
  END pma_tx[121]
  PIN pma_tx[122]
    DIRECTION OUTPUT ;
    USE SIGNAL ;
    SHAPE ABUTMENT ;
    PORT
      LAYER M5 ;
      RECT 28.164 0.000 28.188 0.192 ;
    END
  END pma_tx[122]
  PIN pma_tx[123]
    DIRECTION OUTPUT ;
    USE SIGNAL ;
    SHAPE ABUTMENT ;
    PORT
      LAYER M5 ;
      RECT 28.356 0.000 28.380 0.192 ;
    END
  END pma_tx[123]
  PIN pma_tx[124]
    DIRECTION OUTPUT ;
    USE SIGNAL ;
    SHAPE ABUTMENT ;
    PORT
      LAYER M5 ;
      RECT 28.548 0.000 28.572 0.192 ;
    END
  END pma_tx[124]
  PIN pma_tx[125]
    DIRECTION OUTPUT ;
    USE SIGNAL ;
    SHAPE ABUTMENT ;
    PORT
      LAYER M5 ;
      RECT 28.740 0.000 28.764 0.192 ;
    END
  END pma_tx[125]
  PIN pma_tx[126]
    DIRECTION OUTPUT ;
    USE SIGNAL ;
    SHAPE ABUTMENT ;
    PORT
      LAYER M5 ;
      RECT 28.932 0.000 28.956 0.192 ;
    END
  END pma_tx[126]
  PIN pma_tx[127]
    DIRECTION OUTPUT ;
    USE SIGNAL ;
    SHAPE ABUTMENT ;
    PORT
      LAYER M5 ;
      RECT 29.124 0.000 29.148 0.192 ;
    END
  END pma_tx[127]
  PIN pma_tx[128]
    DIRECTION OUTPUT ;
    USE SIGNAL ;
    SHAPE ABUTMENT ;
    PORT
      LAYER M5 ;
      RECT 29.316 0.000 29.340 0.192 ;
    END
  END pma_tx[128]
  PIN pma_tx[129]
    DIRECTION OUTPUT ;
    USE SIGNAL ;
    SHAPE ABUTMENT ;
    PORT
      LAYER M5 ;
      RECT 29.508 0.000 29.532 0.192 ;
    END
  END pma_tx[129]
  PIN pma_tx[130]
    DIRECTION OUTPUT ;
    USE SIGNAL ;
    SHAPE ABUTMENT ;
    PORT
      LAYER M5 ;
      RECT 29.700 0.000 29.724 0.192 ;
    END
  END pma_tx[130]
  PIN pma_tx[131]
    DIRECTION OUTPUT ;
    USE SIGNAL ;
    SHAPE ABUTMENT ;
    PORT
      LAYER M5 ;
      RECT 29.892 0.000 29.916 0.192 ;
    END
  END pma_tx[131]
  PIN pma_tx[132]
    DIRECTION OUTPUT ;
    USE SIGNAL ;
    SHAPE ABUTMENT ;
    PORT
      LAYER M5 ;
      RECT 30.084 0.000 30.108 0.192 ;
    END
  END pma_tx[132]
  PIN pma_tx[133]
    DIRECTION OUTPUT ;
    USE SIGNAL ;
    SHAPE ABUTMENT ;
    PORT
      LAYER M5 ;
      RECT 30.276 0.000 30.300 0.192 ;
    END
  END pma_tx[133]
  PIN pma_tx[134]
    DIRECTION OUTPUT ;
    USE SIGNAL ;
    SHAPE ABUTMENT ;
    PORT
      LAYER M5 ;
      RECT 30.468 0.000 30.492 0.192 ;
    END
  END pma_tx[134]
  PIN pma_tx[135]
    DIRECTION OUTPUT ;
    USE SIGNAL ;
    SHAPE ABUTMENT ;
    PORT
      LAYER M5 ;
      RECT 30.660 0.000 30.684 0.192 ;
    END
  END pma_tx[135]
  PIN pma_tx[136]
    DIRECTION OUTPUT ;
    USE SIGNAL ;
    SHAPE ABUTMENT ;
    PORT
      LAYER M5 ;
      RECT 30.852 0.000 30.876 0.192 ;
    END
  END pma_tx[136]
  PIN pma_tx[137]
    DIRECTION OUTPUT ;
    USE SIGNAL ;
    SHAPE ABUTMENT ;
    PORT
      LAYER M5 ;
      RECT 31.044 0.000 31.068 0.192 ;
    END
  END pma_tx[137]
  PIN pma_tx[138]
    DIRECTION OUTPUT ;
    USE SIGNAL ;
    SHAPE ABUTMENT ;
    PORT
      LAYER M5 ;
      RECT 31.236 0.000 31.260 0.192 ;
    END
  END pma_tx[138]
  PIN pma_tx[139]
    DIRECTION OUTPUT ;
    USE SIGNAL ;
    SHAPE ABUTMENT ;
    PORT
      LAYER M5 ;
      RECT 31.428 0.000 31.452 0.192 ;
    END
  END pma_tx[139]
  PIN pma_tx[140]
    DIRECTION OUTPUT ;
    USE SIGNAL ;
    SHAPE ABUTMENT ;
    PORT
      LAYER M5 ;
      RECT 31.620 0.000 31.644 0.192 ;
    END
  END pma_tx[140]
  PIN pma_tx[141]
    DIRECTION OUTPUT ;
    USE SIGNAL ;
    SHAPE ABUTMENT ;
    PORT
      LAYER M5 ;
      RECT 31.812 0.000 31.836 0.192 ;
    END
  END pma_tx[141]
  PIN pma_tx[142]
    DIRECTION OUTPUT ;
    USE SIGNAL ;
    SHAPE ABUTMENT ;
    PORT
      LAYER M5 ;
      RECT 32.004 0.000 32.028 0.192 ;
    END
  END pma_tx[142]
  PIN pma_tx[143]
    DIRECTION OUTPUT ;
    USE SIGNAL ;
    SHAPE ABUTMENT ;
    PORT
      LAYER M5 ;
      RECT 32.196 0.000 32.220 0.192 ;
    END
  END pma_tx[143]
  PIN pma_tx[144]
    DIRECTION OUTPUT ;
    USE SIGNAL ;
    SHAPE ABUTMENT ;
    PORT
      LAYER M5 ;
      RECT 32.388 0.000 32.412 0.192 ;
    END
  END pma_tx[144]
  PIN pma_tx[145]
    DIRECTION OUTPUT ;
    USE SIGNAL ;
    SHAPE ABUTMENT ;
    PORT
      LAYER M5 ;
      RECT 32.580 0.000 32.604 0.192 ;
    END
  END pma_tx[145]
  PIN pma_tx[146]
    DIRECTION OUTPUT ;
    USE SIGNAL ;
    SHAPE ABUTMENT ;
    PORT
      LAYER M5 ;
      RECT 32.772 0.000 32.796 0.192 ;
    END
  END pma_tx[146]
  PIN pma_tx[147]
    DIRECTION OUTPUT ;
    USE SIGNAL ;
    SHAPE ABUTMENT ;
    PORT
      LAYER M5 ;
      RECT 32.964 0.000 32.988 0.192 ;
    END
  END pma_tx[147]
  PIN pma_tx[148]
    DIRECTION OUTPUT ;
    USE SIGNAL ;
    SHAPE ABUTMENT ;
    PORT
      LAYER M5 ;
      RECT 33.156 0.000 33.180 0.192 ;
    END
  END pma_tx[148]
  PIN pma_tx[149]
    DIRECTION OUTPUT ;
    USE SIGNAL ;
    SHAPE ABUTMENT ;
    PORT
      LAYER M5 ;
      RECT 33.348 0.000 33.372 0.192 ;
    END
  END pma_tx[149]
  PIN pma_tx[150]
    DIRECTION OUTPUT ;
    USE SIGNAL ;
    SHAPE ABUTMENT ;
    PORT
      LAYER M5 ;
      RECT 33.540 0.000 33.564 0.192 ;
    END
  END pma_tx[150]
  PIN pma_tx[151]
    DIRECTION OUTPUT ;
    USE SIGNAL ;
    SHAPE ABUTMENT ;
    PORT
      LAYER M5 ;
      RECT 33.732 0.000 33.756 0.192 ;
    END
  END pma_tx[151]
  PIN pma_tx[152]
    DIRECTION OUTPUT ;
    USE SIGNAL ;
    SHAPE ABUTMENT ;
    PORT
      LAYER M5 ;
      RECT 33.924 0.000 33.948 0.192 ;
    END
  END pma_tx[152]
  PIN pma_tx[153]
    DIRECTION OUTPUT ;
    USE SIGNAL ;
    SHAPE ABUTMENT ;
    PORT
      LAYER M5 ;
      RECT 34.116 0.000 34.140 0.192 ;
    END
  END pma_tx[153]
  PIN pma_tx[154]
    DIRECTION OUTPUT ;
    USE SIGNAL ;
    SHAPE ABUTMENT ;
    PORT
      LAYER M5 ;
      RECT 34.308 0.000 34.332 0.192 ;
    END
  END pma_tx[154]
  PIN pma_tx[155]
    DIRECTION OUTPUT ;
    USE SIGNAL ;
    SHAPE ABUTMENT ;
    PORT
      LAYER M5 ;
      RECT 34.500 0.000 34.524 0.192 ;
    END
  END pma_tx[155]
  PIN pma_tx[156]
    DIRECTION OUTPUT ;
    USE SIGNAL ;
    SHAPE ABUTMENT ;
    PORT
      LAYER M5 ;
      RECT 34.692 0.000 34.716 0.192 ;
    END
  END pma_tx[156]
  PIN pma_tx[157]
    DIRECTION OUTPUT ;
    USE SIGNAL ;
    SHAPE ABUTMENT ;
    PORT
      LAYER M5 ;
      RECT 34.884 0.000 34.908 0.192 ;
    END
  END pma_tx[157]
  PIN pma_tx[158]
    DIRECTION OUTPUT ;
    USE SIGNAL ;
    SHAPE ABUTMENT ;
    PORT
      LAYER M5 ;
      RECT 35.076 0.000 35.100 0.192 ;
    END
  END pma_tx[158]
  PIN pma_tx[159]
    DIRECTION OUTPUT ;
    USE SIGNAL ;
    SHAPE ABUTMENT ;
    PORT
      LAYER M5 ;
      RECT 35.268 0.000 35.292 0.192 ;
    END
  END pma_tx[159]
  PIN pma_tx[160]
    DIRECTION OUTPUT ;
    USE SIGNAL ;
    SHAPE ABUTMENT ;
    PORT
      LAYER M5 ;
      RECT 35.460 0.000 35.484 0.192 ;
    END
  END pma_tx[160]
  PIN pma_tx[161]
    DIRECTION OUTPUT ;
    USE SIGNAL ;
    SHAPE ABUTMENT ;
    PORT
      LAYER M5 ;
      RECT 35.652 0.000 35.676 0.192 ;
    END
  END pma_tx[161]
  PIN pma_tx[162]
    DIRECTION OUTPUT ;
    USE SIGNAL ;
    SHAPE ABUTMENT ;
    PORT
      LAYER M5 ;
      RECT 35.844 0.000 35.868 0.192 ;
    END
  END pma_tx[162]
  PIN pma_tx[163]
    DIRECTION OUTPUT ;
    USE SIGNAL ;
    SHAPE ABUTMENT ;
    PORT
      LAYER M5 ;
      RECT 36.036 0.000 36.060 0.192 ;
    END
  END pma_tx[163]
  PIN pma_tx[164]
    DIRECTION OUTPUT ;
    USE SIGNAL ;
    SHAPE ABUTMENT ;
    PORT
      LAYER M5 ;
      RECT 36.228 0.000 36.252 0.192 ;
    END
  END pma_tx[164]
  PIN pma_tx[165]
    DIRECTION OUTPUT ;
    USE SIGNAL ;
    SHAPE ABUTMENT ;
    PORT
      LAYER M5 ;
      RECT 36.420 0.000 36.444 0.192 ;
    END
  END pma_tx[165]
  PIN pma_tx[166]
    DIRECTION OUTPUT ;
    USE SIGNAL ;
    SHAPE ABUTMENT ;
    PORT
      LAYER M5 ;
      RECT 36.612 0.000 36.636 0.192 ;
    END
  END pma_tx[166]
  PIN pma_tx[167]
    DIRECTION OUTPUT ;
    USE SIGNAL ;
    SHAPE ABUTMENT ;
    PORT
      LAYER M5 ;
      RECT 36.804 0.000 36.828 0.192 ;
    END
  END pma_tx[167]
  PIN pma_tx[168]
    DIRECTION OUTPUT ;
    USE SIGNAL ;
    SHAPE ABUTMENT ;
    PORT
      LAYER M5 ;
      RECT 36.996 0.000 37.020 0.192 ;
    END
  END pma_tx[168]
  PIN pma_tx[169]
    DIRECTION OUTPUT ;
    USE SIGNAL ;
    SHAPE ABUTMENT ;
    PORT
      LAYER M5 ;
      RECT 37.188 0.000 37.212 0.192 ;
    END
  END pma_tx[169]
  PIN pma_tx[170]
    DIRECTION OUTPUT ;
    USE SIGNAL ;
    SHAPE ABUTMENT ;
    PORT
      LAYER M5 ;
      RECT 37.380 0.000 37.404 0.192 ;
    END
  END pma_tx[170]
  PIN pma_tx[171]
    DIRECTION OUTPUT ;
    USE SIGNAL ;
    SHAPE ABUTMENT ;
    PORT
      LAYER M5 ;
      RECT 37.572 0.000 37.596 0.192 ;
    END
  END pma_tx[171]
  PIN pma_tx[172]
    DIRECTION OUTPUT ;
    USE SIGNAL ;
    SHAPE ABUTMENT ;
    PORT
      LAYER M5 ;
      RECT 37.764 0.000 37.788 0.192 ;
    END
  END pma_tx[172]
  PIN pma_tx[173]
    DIRECTION OUTPUT ;
    USE SIGNAL ;
    SHAPE ABUTMENT ;
    PORT
      LAYER M5 ;
      RECT 37.956 0.000 37.980 0.192 ;
    END
  END pma_tx[173]
  PIN pma_tx[174]
    DIRECTION OUTPUT ;
    USE SIGNAL ;
    SHAPE ABUTMENT ;
    PORT
      LAYER M5 ;
      RECT 38.148 0.000 38.172 0.192 ;
    END
  END pma_tx[174]
  PIN pma_tx[175]
    DIRECTION OUTPUT ;
    USE SIGNAL ;
    SHAPE ABUTMENT ;
    PORT
      LAYER M5 ;
      RECT 38.340 0.000 38.364 0.192 ;
    END
  END pma_tx[175]
  PIN pma_tx[176]
    DIRECTION OUTPUT ;
    USE SIGNAL ;
    SHAPE ABUTMENT ;
    PORT
      LAYER M5 ;
      RECT 38.532 0.000 38.556 0.192 ;
    END
  END pma_tx[176]
  PIN pma_tx[177]
    DIRECTION OUTPUT ;
    USE SIGNAL ;
    SHAPE ABUTMENT ;
    PORT
      LAYER M5 ;
      RECT 38.724 0.000 38.748 0.192 ;
    END
  END pma_tx[177]
  PIN pma_tx[178]
    DIRECTION OUTPUT ;
    USE SIGNAL ;
    SHAPE ABUTMENT ;
    PORT
      LAYER M5 ;
      RECT 38.916 0.000 38.940 0.192 ;
    END
  END pma_tx[178]
  PIN pma_tx[179]
    DIRECTION OUTPUT ;
    USE SIGNAL ;
    SHAPE ABUTMENT ;
    PORT
      LAYER M5 ;
      RECT 39.108 0.000 39.132 0.192 ;
    END
  END pma_tx[179]
  PIN pma_tx[180]
    DIRECTION OUTPUT ;
    USE SIGNAL ;
    SHAPE ABUTMENT ;
    PORT
      LAYER M5 ;
      RECT 39.300 0.000 39.324 0.192 ;
    END
  END pma_tx[180]
  PIN pma_tx[181]
    DIRECTION OUTPUT ;
    USE SIGNAL ;
    SHAPE ABUTMENT ;
    PORT
      LAYER M5 ;
      RECT 39.492 0.000 39.516 0.192 ;
    END
  END pma_tx[181]
  PIN pma_tx[182]
    DIRECTION OUTPUT ;
    USE SIGNAL ;
    SHAPE ABUTMENT ;
    PORT
      LAYER M5 ;
      RECT 39.684 0.000 39.708 0.192 ;
    END
  END pma_tx[182]
  PIN pma_tx[183]
    DIRECTION OUTPUT ;
    USE SIGNAL ;
    SHAPE ABUTMENT ;
    PORT
      LAYER M5 ;
      RECT 39.876 0.000 39.900 0.192 ;
    END
  END pma_tx[183]
  PIN pma_tx[184]
    DIRECTION OUTPUT ;
    USE SIGNAL ;
    SHAPE ABUTMENT ;
    PORT
      LAYER M5 ;
      RECT 40.068 0.000 40.092 0.192 ;
    END
  END pma_tx[184]
  PIN pma_tx[185]
    DIRECTION OUTPUT ;
    USE SIGNAL ;
    SHAPE ABUTMENT ;
    PORT
      LAYER M5 ;
      RECT 40.260 0.000 40.284 0.192 ;
    END
  END pma_tx[185]
  PIN pma_tx[186]
    DIRECTION OUTPUT ;
    USE SIGNAL ;
    SHAPE ABUTMENT ;
    PORT
      LAYER M5 ;
      RECT 40.452 0.000 40.476 0.192 ;
    END
  END pma_tx[186]
  PIN pma_tx[187]
    DIRECTION OUTPUT ;
    USE SIGNAL ;
    SHAPE ABUTMENT ;
    PORT
      LAYER M5 ;
      RECT 40.644 0.000 40.668 0.192 ;
    END
  END pma_tx[187]
  PIN pma_tx[188]
    DIRECTION OUTPUT ;
    USE SIGNAL ;
    SHAPE ABUTMENT ;
    PORT
      LAYER M5 ;
      RECT 40.836 0.000 40.860 0.192 ;
    END
  END pma_tx[188]
  PIN pma_tx[189]
    DIRECTION OUTPUT ;
    USE SIGNAL ;
    SHAPE ABUTMENT ;
    PORT
      LAYER M5 ;
      RECT 41.028 0.000 41.052 0.192 ;
    END
  END pma_tx[189]
  PIN pma_tx[190]
    DIRECTION OUTPUT ;
    USE SIGNAL ;
    SHAPE ABUTMENT ;
    PORT
      LAYER M5 ;
      RECT 41.220 0.000 41.244 0.192 ;
    END
  END pma_tx[190]
  PIN pma_tx[191]
    DIRECTION OUTPUT ;
    USE SIGNAL ;
    SHAPE ABUTMENT ;
    PORT
      LAYER M5 ;
      RECT 41.412 0.000 41.436 0.192 ;
    END
  END pma_tx[191]
  PIN pma_tx[192]
    DIRECTION OUTPUT ;
    USE SIGNAL ;
    SHAPE ABUTMENT ;
    PORT
      LAYER M5 ;
      RECT 41.604 0.000 41.628 0.192 ;
    END
  END pma_tx[192]
  PIN pma_tx[193]
    DIRECTION OUTPUT ;
    USE SIGNAL ;
    SHAPE ABUTMENT ;
    PORT
      LAYER M5 ;
      RECT 41.796 0.000 41.820 0.192 ;
    END
  END pma_tx[193]
  PIN pma_tx[194]
    DIRECTION OUTPUT ;
    USE SIGNAL ;
    SHAPE ABUTMENT ;
    PORT
      LAYER M5 ;
      RECT 41.988 0.000 42.012 0.192 ;
    END
  END pma_tx[194]
  PIN pma_tx[195]
    DIRECTION OUTPUT ;
    USE SIGNAL ;
    SHAPE ABUTMENT ;
    PORT
      LAYER M5 ;
      RECT 42.180 0.000 42.204 0.192 ;
    END
  END pma_tx[195]
  PIN pma_tx[196]
    DIRECTION OUTPUT ;
    USE SIGNAL ;
    SHAPE ABUTMENT ;
    PORT
      LAYER M5 ;
      RECT 42.372 0.000 42.396 0.192 ;
    END
  END pma_tx[196]
  PIN pma_tx[197]
    DIRECTION OUTPUT ;
    USE SIGNAL ;
    SHAPE ABUTMENT ;
    PORT
      LAYER M5 ;
      RECT 42.564 0.000 42.588 0.192 ;
    END
  END pma_tx[197]
  PIN pma_tx[198]
    DIRECTION OUTPUT ;
    USE SIGNAL ;
    SHAPE ABUTMENT ;
    PORT
      LAYER M5 ;
      RECT 42.756 0.000 42.780 0.192 ;
    END
  END pma_tx[198]
  PIN pma_tx[199]
    DIRECTION OUTPUT ;
    USE SIGNAL ;
    SHAPE ABUTMENT ;
    PORT
      LAYER M5 ;
      RECT 42.948 0.000 42.972 0.192 ;
    END
  END pma_tx[199]
  PIN pma_tx[200]
    DIRECTION OUTPUT ;
    USE SIGNAL ;
    SHAPE ABUTMENT ;
    PORT
      LAYER M5 ;
      RECT 43.140 0.000 43.164 0.192 ;
    END
  END pma_tx[200]
  PIN pma_tx[201]
    DIRECTION OUTPUT ;
    USE SIGNAL ;
    SHAPE ABUTMENT ;
    PORT
      LAYER M5 ;
      RECT 43.332 0.000 43.356 0.192 ;
    END
  END pma_tx[201]
  PIN pma_tx[202]
    DIRECTION OUTPUT ;
    USE SIGNAL ;
    SHAPE ABUTMENT ;
    PORT
      LAYER M5 ;
      RECT 43.524 0.000 43.548 0.192 ;
    END
  END pma_tx[202]
  PIN pma_tx[203]
    DIRECTION OUTPUT ;
    USE SIGNAL ;
    SHAPE ABUTMENT ;
    PORT
      LAYER M5 ;
      RECT 43.716 0.000 43.740 0.192 ;
    END
  END pma_tx[203]
  PIN pma_tx[204]
    DIRECTION OUTPUT ;
    USE SIGNAL ;
    SHAPE ABUTMENT ;
    PORT
      LAYER M5 ;
      RECT 43.908 0.000 43.932 0.192 ;
    END
  END pma_tx[204]
  PIN pma_tx[205]
    DIRECTION OUTPUT ;
    USE SIGNAL ;
    SHAPE ABUTMENT ;
    PORT
      LAYER M5 ;
      RECT 44.100 0.000 44.124 0.192 ;
    END
  END pma_tx[205]
  PIN pma_tx[206]
    DIRECTION OUTPUT ;
    USE SIGNAL ;
    SHAPE ABUTMENT ;
    PORT
      LAYER M5 ;
      RECT 44.292 0.000 44.316 0.192 ;
    END
  END pma_tx[206]
  PIN pma_tx[207]
    DIRECTION OUTPUT ;
    USE SIGNAL ;
    SHAPE ABUTMENT ;
    PORT
      LAYER M5 ;
      RECT 44.484 0.000 44.508 0.192 ;
    END
  END pma_tx[207]
  PIN pma_tx[208]
    DIRECTION OUTPUT ;
    USE SIGNAL ;
    SHAPE ABUTMENT ;
    PORT
      LAYER M5 ;
      RECT 44.676 0.000 44.700 0.192 ;
    END
  END pma_tx[208]
  PIN pma_tx[209]
    DIRECTION OUTPUT ;
    USE SIGNAL ;
    SHAPE ABUTMENT ;
    PORT
      LAYER M5 ;
      RECT 44.868 0.000 44.892 0.192 ;
    END
  END pma_tx[209]
  PIN pma_tx[210]
    DIRECTION OUTPUT ;
    USE SIGNAL ;
    SHAPE ABUTMENT ;
    PORT
      LAYER M5 ;
      RECT 45.060 0.000 45.084 0.192 ;
    END
  END pma_tx[210]
  PIN pma_tx[211]
    DIRECTION OUTPUT ;
    USE SIGNAL ;
    SHAPE ABUTMENT ;
    PORT
      LAYER M5 ;
      RECT 45.252 0.000 45.276 0.192 ;
    END
  END pma_tx[211]
  PIN pma_tx[212]
    DIRECTION OUTPUT ;
    USE SIGNAL ;
    SHAPE ABUTMENT ;
    PORT
      LAYER M5 ;
      RECT 45.444 0.000 45.468 0.192 ;
    END
  END pma_tx[212]
  PIN pma_tx[213]
    DIRECTION OUTPUT ;
    USE SIGNAL ;
    SHAPE ABUTMENT ;
    PORT
      LAYER M5 ;
      RECT 45.636 0.000 45.660 0.192 ;
    END
  END pma_tx[213]
  PIN pma_tx[214]
    DIRECTION OUTPUT ;
    USE SIGNAL ;
    SHAPE ABUTMENT ;
    PORT
      LAYER M5 ;
      RECT 45.828 0.000 45.852 0.192 ;
    END
  END pma_tx[214]
  PIN pma_tx[215]
    DIRECTION OUTPUT ;
    USE SIGNAL ;
    SHAPE ABUTMENT ;
    PORT
      LAYER M5 ;
      RECT 46.020 0.000 46.044 0.192 ;
    END
  END pma_tx[215]
  PIN pma_tx[216]
    DIRECTION OUTPUT ;
    USE SIGNAL ;
    SHAPE ABUTMENT ;
    PORT
      LAYER M5 ;
      RECT 46.212 0.000 46.236 0.192 ;
    END
  END pma_tx[216]
  PIN pma_tx[217]
    DIRECTION OUTPUT ;
    USE SIGNAL ;
    SHAPE ABUTMENT ;
    PORT
      LAYER M5 ;
      RECT 46.404 0.000 46.428 0.192 ;
    END
  END pma_tx[217]
  PIN pma_tx[218]
    DIRECTION OUTPUT ;
    USE SIGNAL ;
    SHAPE ABUTMENT ;
    PORT
      LAYER M5 ;
      RECT 46.596 0.000 46.620 0.192 ;
    END
  END pma_tx[218]
  PIN pma_tx[219]
    DIRECTION OUTPUT ;
    USE SIGNAL ;
    SHAPE ABUTMENT ;
    PORT
      LAYER M5 ;
      RECT 46.788 0.000 46.812 0.192 ;
    END
  END pma_tx[219]
  PIN pma_tx[220]
    DIRECTION OUTPUT ;
    USE SIGNAL ;
    SHAPE ABUTMENT ;
    PORT
      LAYER M5 ;
      RECT 46.980 0.000 47.004 0.192 ;
    END
  END pma_tx[220]
  PIN pma_tx[221]
    DIRECTION OUTPUT ;
    USE SIGNAL ;
    SHAPE ABUTMENT ;
    PORT
      LAYER M5 ;
      RECT 47.172 0.000 47.196 0.192 ;
    END
  END pma_tx[221]
  PIN pma_tx[222]
    DIRECTION OUTPUT ;
    USE SIGNAL ;
    SHAPE ABUTMENT ;
    PORT
      LAYER M5 ;
      RECT 47.364 0.000 47.388 0.192 ;
    END
  END pma_tx[222]
  PIN pma_tx[223]
    DIRECTION OUTPUT ;
    USE SIGNAL ;
    SHAPE ABUTMENT ;
    PORT
      LAYER M5 ;
      RECT 47.556 0.000 47.580 0.192 ;
    END
  END pma_tx[223]
  PIN pma_tx[224]
    DIRECTION OUTPUT ;
    USE SIGNAL ;
    SHAPE ABUTMENT ;
    PORT
      LAYER M5 ;
      RECT 47.748 0.000 47.772 0.192 ;
    END
  END pma_tx[224]
  PIN pma_tx[225]
    DIRECTION OUTPUT ;
    USE SIGNAL ;
    SHAPE ABUTMENT ;
    PORT
      LAYER M5 ;
      RECT 47.940 0.000 47.964 0.192 ;
    END
  END pma_tx[225]
  PIN pma_tx[226]
    DIRECTION OUTPUT ;
    USE SIGNAL ;
    SHAPE ABUTMENT ;
    PORT
      LAYER M5 ;
      RECT 48.132 0.000 48.156 0.192 ;
    END
  END pma_tx[226]
  PIN pma_tx[227]
    DIRECTION OUTPUT ;
    USE SIGNAL ;
    SHAPE ABUTMENT ;
    PORT
      LAYER M5 ;
      RECT 48.324 0.000 48.348 0.192 ;
    END
  END pma_tx[227]
  PIN pma_tx[228]
    DIRECTION OUTPUT ;
    USE SIGNAL ;
    SHAPE ABUTMENT ;
    PORT
      LAYER M5 ;
      RECT 48.516 0.000 48.540 0.192 ;
    END
  END pma_tx[228]
  PIN pma_tx[229]
    DIRECTION OUTPUT ;
    USE SIGNAL ;
    SHAPE ABUTMENT ;
    PORT
      LAYER M5 ;
      RECT 48.708 0.000 48.732 0.192 ;
    END
  END pma_tx[229]
  PIN pma_tx[230]
    DIRECTION OUTPUT ;
    USE SIGNAL ;
    SHAPE ABUTMENT ;
    PORT
      LAYER M5 ;
      RECT 48.900 0.000 48.924 0.192 ;
    END
  END pma_tx[230]
  PIN pma_tx[231]
    DIRECTION OUTPUT ;
    USE SIGNAL ;
    SHAPE ABUTMENT ;
    PORT
      LAYER M5 ;
      RECT 49.092 0.000 49.116 0.192 ;
    END
  END pma_tx[231]
  PIN pma_tx[232]
    DIRECTION OUTPUT ;
    USE SIGNAL ;
    SHAPE ABUTMENT ;
    PORT
      LAYER M5 ;
      RECT 49.284 0.000 49.308 0.192 ;
    END
  END pma_tx[232]
  PIN pma_tx[233]
    DIRECTION OUTPUT ;
    USE SIGNAL ;
    SHAPE ABUTMENT ;
    PORT
      LAYER M5 ;
      RECT 49.476 0.000 49.500 0.192 ;
    END
  END pma_tx[233]
  PIN pma_tx[234]
    DIRECTION OUTPUT ;
    USE SIGNAL ;
    SHAPE ABUTMENT ;
    PORT
      LAYER M5 ;
      RECT 49.668 0.000 49.692 0.192 ;
    END
  END pma_tx[234]
  PIN pma_tx[235]
    DIRECTION OUTPUT ;
    USE SIGNAL ;
    SHAPE ABUTMENT ;
    PORT
      LAYER M5 ;
      RECT 49.860 0.000 49.884 0.192 ;
    END
  END pma_tx[235]
  PIN pma_tx[236]
    DIRECTION OUTPUT ;
    USE SIGNAL ;
    SHAPE ABUTMENT ;
    PORT
      LAYER M5 ;
      RECT 50.052 0.000 50.076 0.192 ;
    END
  END pma_tx[236]
  PIN pma_tx[237]
    DIRECTION OUTPUT ;
    USE SIGNAL ;
    SHAPE ABUTMENT ;
    PORT
      LAYER M5 ;
      RECT 50.244 0.000 50.268 0.192 ;
    END
  END pma_tx[237]
  PIN pma_tx[238]
    DIRECTION OUTPUT ;
    USE SIGNAL ;
    SHAPE ABUTMENT ;
    PORT
      LAYER M5 ;
      RECT 50.436 0.000 50.460 0.192 ;
    END
  END pma_tx[238]
  PIN pma_tx[239]
    DIRECTION OUTPUT ;
    USE SIGNAL ;
    SHAPE ABUTMENT ;
    PORT
      LAYER M5 ;
      RECT 50.628 0.000 50.652 0.192 ;
    END
  END pma_tx[239]
  PIN pma_tx[240]
    DIRECTION OUTPUT ;
    USE SIGNAL ;
    SHAPE ABUTMENT ;
    PORT
      LAYER M5 ;
      RECT 50.820 0.000 50.844 0.192 ;
    END
  END pma_tx[240]
  PIN pma_tx[241]
    DIRECTION OUTPUT ;
    USE SIGNAL ;
    SHAPE ABUTMENT ;
    PORT
      LAYER M5 ;
      RECT 51.012 0.000 51.036 0.192 ;
    END
  END pma_tx[241]
  PIN pma_tx[242]
    DIRECTION OUTPUT ;
    USE SIGNAL ;
    SHAPE ABUTMENT ;
    PORT
      LAYER M5 ;
      RECT 51.204 0.000 51.228 0.192 ;
    END
  END pma_tx[242]
  PIN pma_tx[243]
    DIRECTION OUTPUT ;
    USE SIGNAL ;
    SHAPE ABUTMENT ;
    PORT
      LAYER M5 ;
      RECT 51.396 0.000 51.420 0.192 ;
    END
  END pma_tx[243]
  PIN pma_tx[244]
    DIRECTION OUTPUT ;
    USE SIGNAL ;
    SHAPE ABUTMENT ;
    PORT
      LAYER M5 ;
      RECT 51.588 0.000 51.612 0.192 ;
    END
  END pma_tx[244]
  PIN pma_tx[245]
    DIRECTION OUTPUT ;
    USE SIGNAL ;
    SHAPE ABUTMENT ;
    PORT
      LAYER M5 ;
      RECT 51.780 0.000 51.804 0.192 ;
    END
  END pma_tx[245]
  PIN pma_tx[246]
    DIRECTION OUTPUT ;
    USE SIGNAL ;
    SHAPE ABUTMENT ;
    PORT
      LAYER M5 ;
      RECT 51.972 0.000 51.996 0.192 ;
    END
  END pma_tx[246]
  PIN pma_tx[247]
    DIRECTION OUTPUT ;
    USE SIGNAL ;
    SHAPE ABUTMENT ;
    PORT
      LAYER M5 ;
      RECT 52.164 0.000 52.188 0.192 ;
    END
  END pma_tx[247]
  PIN pma_tx[248]
    DIRECTION OUTPUT ;
    USE SIGNAL ;
    SHAPE ABUTMENT ;
    PORT
      LAYER M5 ;
      RECT 52.356 0.000 52.380 0.192 ;
    END
  END pma_tx[248]
  PIN pma_tx[249]
    DIRECTION OUTPUT ;
    USE SIGNAL ;
    SHAPE ABUTMENT ;
    PORT
      LAYER M5 ;
      RECT 52.548 0.000 52.572 0.192 ;
    END
  END pma_tx[249]
  PIN pma_tx[250]
    DIRECTION OUTPUT ;
    USE SIGNAL ;
    SHAPE ABUTMENT ;
    PORT
      LAYER M5 ;
      RECT 52.740 0.000 52.764 0.192 ;
    END
  END pma_tx[250]
  PIN pma_tx[251]
    DIRECTION OUTPUT ;
    USE SIGNAL ;
    SHAPE ABUTMENT ;
    PORT
      LAYER M5 ;
      RECT 52.932 0.000 52.956 0.192 ;
    END
  END pma_tx[251]
  PIN pma_tx[252]
    DIRECTION OUTPUT ;
    USE SIGNAL ;
    SHAPE ABUTMENT ;
    PORT
      LAYER M5 ;
      RECT 53.124 0.000 53.148 0.192 ;
    END
  END pma_tx[252]
  PIN pma_tx[253]
    DIRECTION OUTPUT ;
    USE SIGNAL ;
    SHAPE ABUTMENT ;
    PORT
      LAYER M5 ;
      RECT 53.316 0.000 53.340 0.192 ;
    END
  END pma_tx[253]
  PIN pma_tx[254]
    DIRECTION OUTPUT ;
    USE SIGNAL ;
    SHAPE ABUTMENT ;
    PORT
      LAYER M5 ;
      RECT 53.508 0.000 53.532 0.192 ;
    END
  END pma_tx[254]
  PIN pma_tx[255]
    DIRECTION OUTPUT ;
    USE SIGNAL ;
    SHAPE ABUTMENT ;
    PORT
      LAYER M5 ;
      RECT 53.700 0.000 53.724 0.192 ;
    END
  END pma_tx[255]
  PIN pma_tx[256]
    DIRECTION OUTPUT ;
    USE SIGNAL ;
    SHAPE ABUTMENT ;
    PORT
      LAYER M5 ;
      RECT 53.892 0.000 53.916 0.192 ;
    END
  END pma_tx[256]
  PIN pma_tx[257]
    DIRECTION OUTPUT ;
    USE SIGNAL ;
    SHAPE ABUTMENT ;
    PORT
      LAYER M5 ;
      RECT 54.084 0.000 54.108 0.192 ;
    END
  END pma_tx[257]
  PIN pma_tx[258]
    DIRECTION OUTPUT ;
    USE SIGNAL ;
    SHAPE ABUTMENT ;
    PORT
      LAYER M5 ;
      RECT 54.276 0.000 54.300 0.192 ;
    END
  END pma_tx[258]
  PIN pma_tx[259]
    DIRECTION OUTPUT ;
    USE SIGNAL ;
    SHAPE ABUTMENT ;
    PORT
      LAYER M5 ;
      RECT 54.468 0.000 54.492 0.192 ;
    END
  END pma_tx[259]
  PIN pma_tx[260]
    DIRECTION OUTPUT ;
    USE SIGNAL ;
    SHAPE ABUTMENT ;
    PORT
      LAYER M5 ;
      RECT 54.660 0.000 54.684 0.192 ;
    END
  END pma_tx[260]
  PIN pma_tx[261]
    DIRECTION OUTPUT ;
    USE SIGNAL ;
    SHAPE ABUTMENT ;
    PORT
      LAYER M5 ;
      RECT 54.852 0.000 54.876 0.192 ;
    END
  END pma_tx[261]
  PIN pma_tx[262]
    DIRECTION OUTPUT ;
    USE SIGNAL ;
    SHAPE ABUTMENT ;
    PORT
      LAYER M5 ;
      RECT 55.044 0.000 55.068 0.192 ;
    END
  END pma_tx[262]
  PIN pma_tx[263]
    DIRECTION OUTPUT ;
    USE SIGNAL ;
    SHAPE ABUTMENT ;
    PORT
      LAYER M5 ;
      RECT 55.236 0.000 55.260 0.192 ;
    END
  END pma_tx[263]
  PIN pma_tx[264]
    DIRECTION OUTPUT ;
    USE SIGNAL ;
    SHAPE ABUTMENT ;
    PORT
      LAYER M5 ;
      RECT 55.428 0.000 55.452 0.192 ;
    END
  END pma_tx[264]
  PIN pma_tx[265]
    DIRECTION OUTPUT ;
    USE SIGNAL ;
    SHAPE ABUTMENT ;
    PORT
      LAYER M5 ;
      RECT 55.620 0.000 55.644 0.192 ;
    END
  END pma_tx[265]
  PIN pma_tx[266]
    DIRECTION OUTPUT ;
    USE SIGNAL ;
    SHAPE ABUTMENT ;
    PORT
      LAYER M5 ;
      RECT 55.812 0.000 55.836 0.192 ;
    END
  END pma_tx[266]
  PIN pma_tx[267]
    DIRECTION OUTPUT ;
    USE SIGNAL ;
    SHAPE ABUTMENT ;
    PORT
      LAYER M5 ;
      RECT 56.004 0.000 56.028 0.192 ;
    END
  END pma_tx[267]
  PIN pma_tx[268]
    DIRECTION OUTPUT ;
    USE SIGNAL ;
    SHAPE ABUTMENT ;
    PORT
      LAYER M5 ;
      RECT 56.196 0.000 56.220 0.192 ;
    END
  END pma_tx[268]
  PIN pma_tx[269]
    DIRECTION OUTPUT ;
    USE SIGNAL ;
    SHAPE ABUTMENT ;
    PORT
      LAYER M5 ;
      RECT 56.388 0.000 56.412 0.192 ;
    END
  END pma_tx[269]
  PIN pma_tx[270]
    DIRECTION OUTPUT ;
    USE SIGNAL ;
    SHAPE ABUTMENT ;
    PORT
      LAYER M5 ;
      RECT 56.580 0.000 56.604 0.192 ;
    END
  END pma_tx[270]
  PIN pma_tx[271]
    DIRECTION OUTPUT ;
    USE SIGNAL ;
    SHAPE ABUTMENT ;
    PORT
      LAYER M5 ;
      RECT 56.772 0.000 56.796 0.192 ;
    END
  END pma_tx[271]
  PIN pma_tx[272]
    DIRECTION OUTPUT ;
    USE SIGNAL ;
    SHAPE ABUTMENT ;
    PORT
      LAYER M5 ;
      RECT 56.964 0.000 56.988 0.192 ;
    END
  END pma_tx[272]
  PIN pma_tx[273]
    DIRECTION OUTPUT ;
    USE SIGNAL ;
    SHAPE ABUTMENT ;
    PORT
      LAYER M5 ;
      RECT 57.156 0.000 57.180 0.192 ;
    END
  END pma_tx[273]
  PIN pma_tx[274]
    DIRECTION OUTPUT ;
    USE SIGNAL ;
    SHAPE ABUTMENT ;
    PORT
      LAYER M5 ;
      RECT 57.348 0.000 57.372 0.192 ;
    END
  END pma_tx[274]
  PIN pma_tx[275]
    DIRECTION OUTPUT ;
    USE SIGNAL ;
    SHAPE ABUTMENT ;
    PORT
      LAYER M5 ;
      RECT 57.540 0.000 57.564 0.192 ;
    END
  END pma_tx[275]
  PIN pma_tx[276]
    DIRECTION OUTPUT ;
    USE SIGNAL ;
    SHAPE ABUTMENT ;
    PORT
      LAYER M5 ;
      RECT 57.732 0.000 57.756 0.192 ;
    END
  END pma_tx[276]
  PIN pma_tx[277]
    DIRECTION OUTPUT ;
    USE SIGNAL ;
    SHAPE ABUTMENT ;
    PORT
      LAYER M5 ;
      RECT 57.924 0.000 57.948 0.192 ;
    END
  END pma_tx[277]
  PIN pma_tx[278]
    DIRECTION OUTPUT ;
    USE SIGNAL ;
    SHAPE ABUTMENT ;
    PORT
      LAYER M5 ;
      RECT 58.116 0.000 58.140 0.192 ;
    END
  END pma_tx[278]
  PIN pma_tx[279]
    DIRECTION OUTPUT ;
    USE SIGNAL ;
    SHAPE ABUTMENT ;
    PORT
      LAYER M5 ;
      RECT 58.308 0.000 58.332 0.192 ;
    END
  END pma_tx[279]
  PIN pma_tx[280]
    DIRECTION OUTPUT ;
    USE SIGNAL ;
    SHAPE ABUTMENT ;
    PORT
      LAYER M5 ;
      RECT 58.500 0.000 58.524 0.192 ;
    END
  END pma_tx[280]
  PIN pma_tx[281]
    DIRECTION OUTPUT ;
    USE SIGNAL ;
    SHAPE ABUTMENT ;
    PORT
      LAYER M5 ;
      RECT 58.692 0.000 58.716 0.192 ;
    END
  END pma_tx[281]
  PIN pma_tx[282]
    DIRECTION OUTPUT ;
    USE SIGNAL ;
    SHAPE ABUTMENT ;
    PORT
      LAYER M5 ;
      RECT 58.884 0.000 58.908 0.192 ;
    END
  END pma_tx[282]
  PIN pma_tx[283]
    DIRECTION OUTPUT ;
    USE SIGNAL ;
    SHAPE ABUTMENT ;
    PORT
      LAYER M5 ;
      RECT 59.076 0.000 59.100 0.192 ;
    END
  END pma_tx[283]
  PIN pma_tx[284]
    DIRECTION OUTPUT ;
    USE SIGNAL ;
    SHAPE ABUTMENT ;
    PORT
      LAYER M5 ;
      RECT 59.268 0.000 59.292 0.192 ;
    END
  END pma_tx[284]
  PIN pma_tx[285]
    DIRECTION OUTPUT ;
    USE SIGNAL ;
    SHAPE ABUTMENT ;
    PORT
      LAYER M5 ;
      RECT 59.460 0.000 59.484 0.192 ;
    END
  END pma_tx[285]
  PIN pma_tx[286]
    DIRECTION OUTPUT ;
    USE SIGNAL ;
    SHAPE ABUTMENT ;
    PORT
      LAYER M5 ;
      RECT 59.652 0.000 59.676 0.192 ;
    END
  END pma_tx[286]
  PIN pma_tx[287]
    DIRECTION OUTPUT ;
    USE SIGNAL ;
    SHAPE ABUTMENT ;
    PORT
      LAYER M5 ;
      RECT 59.844 0.000 59.868 0.192 ;
    END
  END pma_tx[287]
  PIN pma_tx[288]
    DIRECTION OUTPUT ;
    USE SIGNAL ;
    SHAPE ABUTMENT ;
    PORT
      LAYER M5 ;
      RECT 60.036 0.000 60.060 0.192 ;
    END
  END pma_tx[288]
  PIN pma_tx[289]
    DIRECTION OUTPUT ;
    USE SIGNAL ;
    SHAPE ABUTMENT ;
    PORT
      LAYER M5 ;
      RECT 60.228 0.000 60.252 0.192 ;
    END
  END pma_tx[289]
  PIN pma_tx[290]
    DIRECTION OUTPUT ;
    USE SIGNAL ;
    SHAPE ABUTMENT ;
    PORT
      LAYER M5 ;
      RECT 60.420 0.000 60.444 0.192 ;
    END
  END pma_tx[290]
  PIN pma_tx[291]
    DIRECTION OUTPUT ;
    USE SIGNAL ;
    SHAPE ABUTMENT ;
    PORT
      LAYER M5 ;
      RECT 60.612 0.000 60.636 0.192 ;
    END
  END pma_tx[291]
  PIN pma_tx[292]
    DIRECTION OUTPUT ;
    USE SIGNAL ;
    SHAPE ABUTMENT ;
    PORT
      LAYER M5 ;
      RECT 60.804 0.000 60.828 0.192 ;
    END
  END pma_tx[292]
  PIN pma_tx[293]
    DIRECTION OUTPUT ;
    USE SIGNAL ;
    SHAPE ABUTMENT ;
    PORT
      LAYER M5 ;
      RECT 60.996 0.000 61.020 0.192 ;
    END
  END pma_tx[293]
  PIN pma_tx[294]
    DIRECTION OUTPUT ;
    USE SIGNAL ;
    SHAPE ABUTMENT ;
    PORT
      LAYER M5 ;
      RECT 61.188 0.000 61.212 0.192 ;
    END
  END pma_tx[294]
  PIN pma_tx[295]
    DIRECTION OUTPUT ;
    USE SIGNAL ;
    SHAPE ABUTMENT ;
    PORT
      LAYER M5 ;
      RECT 61.380 0.000 61.404 0.192 ;
    END
  END pma_tx[295]
  PIN pma_tx[296]
    DIRECTION OUTPUT ;
    USE SIGNAL ;
    SHAPE ABUTMENT ;
    PORT
      LAYER M5 ;
      RECT 61.572 0.000 61.596 0.192 ;
    END
  END pma_tx[296]
  PIN pma_tx[297]
    DIRECTION OUTPUT ;
    USE SIGNAL ;
    SHAPE ABUTMENT ;
    PORT
      LAYER M5 ;
      RECT 61.764 0.000 61.788 0.192 ;
    END
  END pma_tx[297]
  PIN pma_tx[298]
    DIRECTION OUTPUT ;
    USE SIGNAL ;
    SHAPE ABUTMENT ;
    PORT
      LAYER M5 ;
      RECT 61.956 0.000 61.980 0.192 ;
    END
  END pma_tx[298]
  PIN pma_tx[299]
    DIRECTION OUTPUT ;
    USE SIGNAL ;
    SHAPE ABUTMENT ;
    PORT
      LAYER M5 ;
      RECT 62.148 0.000 62.172 0.192 ;
    END
  END pma_tx[299]
  PIN pma_tx[300]
    DIRECTION OUTPUT ;
    USE SIGNAL ;
    SHAPE ABUTMENT ;
    PORT
      LAYER M5 ;
      RECT 62.340 0.000 62.364 0.192 ;
    END
  END pma_tx[300]
  PIN pma_tx[301]
    DIRECTION OUTPUT ;
    USE SIGNAL ;
    SHAPE ABUTMENT ;
    PORT
      LAYER M5 ;
      RECT 62.532 0.000 62.556 0.192 ;
    END
  END pma_tx[301]
  PIN pma_tx[302]
    DIRECTION OUTPUT ;
    USE SIGNAL ;
    SHAPE ABUTMENT ;
    PORT
      LAYER M5 ;
      RECT 62.724 0.000 62.748 0.192 ;
    END
  END pma_tx[302]
  PIN pma_tx[303]
    DIRECTION OUTPUT ;
    USE SIGNAL ;
    SHAPE ABUTMENT ;
    PORT
      LAYER M5 ;
      RECT 62.916 0.000 62.940 0.192 ;
    END
  END pma_tx[303]
  PIN pma_tx[304]
    DIRECTION OUTPUT ;
    USE SIGNAL ;
    SHAPE ABUTMENT ;
    PORT
      LAYER M5 ;
      RECT 63.108 0.000 63.132 0.192 ;
    END
  END pma_tx[304]
  PIN pma_tx[305]
    DIRECTION OUTPUT ;
    USE SIGNAL ;
    SHAPE ABUTMENT ;
    PORT
      LAYER M5 ;
      RECT 63.300 0.000 63.324 0.192 ;
    END
  END pma_tx[305]
  PIN pma_tx[306]
    DIRECTION OUTPUT ;
    USE SIGNAL ;
    SHAPE ABUTMENT ;
    PORT
      LAYER M5 ;
      RECT 63.492 0.000 63.516 0.192 ;
    END
  END pma_tx[306]
  PIN pma_tx[307]
    DIRECTION OUTPUT ;
    USE SIGNAL ;
    SHAPE ABUTMENT ;
    PORT
      LAYER M5 ;
      RECT 63.684 0.000 63.708 0.192 ;
    END
  END pma_tx[307]
  PIN pma_tx[308]
    DIRECTION OUTPUT ;
    USE SIGNAL ;
    SHAPE ABUTMENT ;
    PORT
      LAYER M5 ;
      RECT 63.876 0.000 63.900 0.192 ;
    END
  END pma_tx[308]
  PIN pma_tx[309]
    DIRECTION OUTPUT ;
    USE SIGNAL ;
    SHAPE ABUTMENT ;
    PORT
      LAYER M5 ;
      RECT 64.068 0.000 64.092 0.192 ;
    END
  END pma_tx[309]
  PIN pma_tx[310]
    DIRECTION OUTPUT ;
    USE SIGNAL ;
    SHAPE ABUTMENT ;
    PORT
      LAYER M5 ;
      RECT 64.260 0.000 64.284 0.192 ;
    END
  END pma_tx[310]
  PIN pma_tx[311]
    DIRECTION OUTPUT ;
    USE SIGNAL ;
    SHAPE ABUTMENT ;
    PORT
      LAYER M5 ;
      RECT 64.452 0.000 64.476 0.192 ;
    END
  END pma_tx[311]
  PIN pma_tx[312]
    DIRECTION OUTPUT ;
    USE SIGNAL ;
    SHAPE ABUTMENT ;
    PORT
      LAYER M5 ;
      RECT 64.644 0.000 64.668 0.192 ;
    END
  END pma_tx[312]
  PIN pma_tx[313]
    DIRECTION OUTPUT ;
    USE SIGNAL ;
    SHAPE ABUTMENT ;
    PORT
      LAYER M5 ;
      RECT 64.836 0.000 64.860 0.192 ;
    END
  END pma_tx[313]
  PIN pma_tx[314]
    DIRECTION OUTPUT ;
    USE SIGNAL ;
    SHAPE ABUTMENT ;
    PORT
      LAYER M5 ;
      RECT 65.028 0.000 65.052 0.192 ;
    END
  END pma_tx[314]
  PIN pma_tx[315]
    DIRECTION OUTPUT ;
    USE SIGNAL ;
    SHAPE ABUTMENT ;
    PORT
      LAYER M5 ;
      RECT 65.220 0.000 65.244 0.192 ;
    END
  END pma_tx[315]
  PIN pma_tx[316]
    DIRECTION OUTPUT ;
    USE SIGNAL ;
    SHAPE ABUTMENT ;
    PORT
      LAYER M5 ;
      RECT 65.412 0.000 65.436 0.192 ;
    END
  END pma_tx[316]
  PIN pma_tx[317]
    DIRECTION OUTPUT ;
    USE SIGNAL ;
    SHAPE ABUTMENT ;
    PORT
      LAYER M5 ;
      RECT 65.604 0.000 65.628 0.192 ;
    END
  END pma_tx[317]
  PIN pma_tx[318]
    DIRECTION OUTPUT ;
    USE SIGNAL ;
    SHAPE ABUTMENT ;
    PORT
      LAYER M5 ;
      RECT 65.796 0.000 65.820 0.192 ;
    END
  END pma_tx[318]
  PIN pma_tx[319]
    DIRECTION OUTPUT ;
    USE SIGNAL ;
    SHAPE ABUTMENT ;
    PORT
      LAYER M5 ;
      RECT 65.988 0.000 66.012 0.192 ;
    END
  END pma_tx[319]
  PIN pma_tx[320]
    DIRECTION OUTPUT ;
    USE SIGNAL ;
    SHAPE ABUTMENT ;
    PORT
      LAYER M5 ;
      RECT 66.180 0.000 66.204 0.192 ;
    END
  END pma_tx[320]
  PIN pma_tx[321]
    DIRECTION OUTPUT ;
    USE SIGNAL ;
    SHAPE ABUTMENT ;
    PORT
      LAYER M5 ;
      RECT 66.372 0.000 66.396 0.192 ;
    END
  END pma_tx[321]
  PIN pma_tx[322]
    DIRECTION OUTPUT ;
    USE SIGNAL ;
    SHAPE ABUTMENT ;
    PORT
      LAYER M5 ;
      RECT 66.564 0.000 66.588 0.192 ;
    END
  END pma_tx[322]
  PIN pma_tx[323]
    DIRECTION OUTPUT ;
    USE SIGNAL ;
    SHAPE ABUTMENT ;
    PORT
      LAYER M5 ;
      RECT 66.756 0.000 66.780 0.192 ;
    END
  END pma_tx[323]
  PIN pma_tx[324]
    DIRECTION OUTPUT ;
    USE SIGNAL ;
    SHAPE ABUTMENT ;
    PORT
      LAYER M5 ;
      RECT 66.948 0.000 66.972 0.192 ;
    END
  END pma_tx[324]
  PIN pma_tx[325]
    DIRECTION OUTPUT ;
    USE SIGNAL ;
    SHAPE ABUTMENT ;
    PORT
      LAYER M5 ;
      RECT 67.140 0.000 67.164 0.192 ;
    END
  END pma_tx[325]
  PIN pma_tx[326]
    DIRECTION OUTPUT ;
    USE SIGNAL ;
    SHAPE ABUTMENT ;
    PORT
      LAYER M5 ;
      RECT 67.332 0.000 67.356 0.192 ;
    END
  END pma_tx[326]
  PIN pma_tx[327]
    DIRECTION OUTPUT ;
    USE SIGNAL ;
    SHAPE ABUTMENT ;
    PORT
      LAYER M5 ;
      RECT 67.524 0.000 67.548 0.192 ;
    END
  END pma_tx[327]
  PIN pma_tx[328]
    DIRECTION OUTPUT ;
    USE SIGNAL ;
    SHAPE ABUTMENT ;
    PORT
      LAYER M5 ;
      RECT 67.716 0.000 67.740 0.192 ;
    END
  END pma_tx[328]
  PIN pma_tx[329]
    DIRECTION OUTPUT ;
    USE SIGNAL ;
    SHAPE ABUTMENT ;
    PORT
      LAYER M5 ;
      RECT 67.908 0.000 67.932 0.192 ;
    END
  END pma_tx[329]
  PIN pma_tx[330]
    DIRECTION OUTPUT ;
    USE SIGNAL ;
    SHAPE ABUTMENT ;
    PORT
      LAYER M5 ;
      RECT 68.100 0.000 68.124 0.192 ;
    END
  END pma_tx[330]
  PIN pma_tx[331]
    DIRECTION OUTPUT ;
    USE SIGNAL ;
    SHAPE ABUTMENT ;
    PORT
      LAYER M5 ;
      RECT 68.292 0.000 68.316 0.192 ;
    END
  END pma_tx[331]
  PIN pma_tx[332]
    DIRECTION OUTPUT ;
    USE SIGNAL ;
    SHAPE ABUTMENT ;
    PORT
      LAYER M5 ;
      RECT 68.484 0.000 68.508 0.192 ;
    END
  END pma_tx[332]
  PIN pma_tx[333]
    DIRECTION OUTPUT ;
    USE SIGNAL ;
    SHAPE ABUTMENT ;
    PORT
      LAYER M5 ;
      RECT 68.676 0.000 68.700 0.192 ;
    END
  END pma_tx[333]
  PIN pma_tx[334]
    DIRECTION OUTPUT ;
    USE SIGNAL ;
    SHAPE ABUTMENT ;
    PORT
      LAYER M5 ;
      RECT 68.868 0.000 68.892 0.192 ;
    END
  END pma_tx[334]
  PIN pma_tx[335]
    DIRECTION OUTPUT ;
    USE SIGNAL ;
    SHAPE ABUTMENT ;
    PORT
      LAYER M5 ;
      RECT 69.060 0.000 69.084 0.192 ;
    END
  END pma_tx[335]
  PIN pma_tx[336]
    DIRECTION OUTPUT ;
    USE SIGNAL ;
    SHAPE ABUTMENT ;
    PORT
      LAYER M5 ;
      RECT 69.252 0.000 69.276 0.192 ;
    END
  END pma_tx[336]
  PIN pma_tx[337]
    DIRECTION OUTPUT ;
    USE SIGNAL ;
    SHAPE ABUTMENT ;
    PORT
      LAYER M5 ;
      RECT 69.444 0.000 69.468 0.192 ;
    END
  END pma_tx[337]
  PIN pma_tx[338]
    DIRECTION OUTPUT ;
    USE SIGNAL ;
    SHAPE ABUTMENT ;
    PORT
      LAYER M5 ;
      RECT 69.636 0.000 69.660 0.192 ;
    END
  END pma_tx[338]
  PIN pma_tx[339]
    DIRECTION OUTPUT ;
    USE SIGNAL ;
    SHAPE ABUTMENT ;
    PORT
      LAYER M5 ;
      RECT 69.828 0.000 69.852 0.192 ;
    END
  END pma_tx[339]
  PIN pma_tx[340]
    DIRECTION OUTPUT ;
    USE SIGNAL ;
    SHAPE ABUTMENT ;
    PORT
      LAYER M5 ;
      RECT 70.020 0.000 70.044 0.192 ;
    END
  END pma_tx[340]
  PIN pma_tx[341]
    DIRECTION OUTPUT ;
    USE SIGNAL ;
    SHAPE ABUTMENT ;
    PORT
      LAYER M5 ;
      RECT 70.212 0.000 70.236 0.192 ;
    END
  END pma_tx[341]
  PIN pma_tx[342]
    DIRECTION OUTPUT ;
    USE SIGNAL ;
    SHAPE ABUTMENT ;
    PORT
      LAYER M5 ;
      RECT 70.404 0.000 70.428 0.192 ;
    END
  END pma_tx[342]
  PIN pma_tx[343]
    DIRECTION OUTPUT ;
    USE SIGNAL ;
    SHAPE ABUTMENT ;
    PORT
      LAYER M5 ;
      RECT 70.596 0.000 70.620 0.192 ;
    END
  END pma_tx[343]
  PIN pma_tx[344]
    DIRECTION OUTPUT ;
    USE SIGNAL ;
    SHAPE ABUTMENT ;
    PORT
      LAYER M5 ;
      RECT 70.788 0.000 70.812 0.192 ;
    END
  END pma_tx[344]
  PIN pma_tx[345]
    DIRECTION OUTPUT ;
    USE SIGNAL ;
    SHAPE ABUTMENT ;
    PORT
      LAYER M5 ;
      RECT 70.980 0.000 71.004 0.192 ;
    END
  END pma_tx[345]
  PIN pma_tx[346]
    DIRECTION OUTPUT ;
    USE SIGNAL ;
    SHAPE ABUTMENT ;
    PORT
      LAYER M5 ;
      RECT 71.172 0.000 71.196 0.192 ;
    END
  END pma_tx[346]
  PIN pma_tx[347]
    DIRECTION OUTPUT ;
    USE SIGNAL ;
    SHAPE ABUTMENT ;
    PORT
      LAYER M5 ;
      RECT 71.364 0.000 71.388 0.192 ;
    END
  END pma_tx[347]
  PIN pma_tx[348]
    DIRECTION OUTPUT ;
    USE SIGNAL ;
    SHAPE ABUTMENT ;
    PORT
      LAYER M5 ;
      RECT 71.556 0.000 71.580 0.192 ;
    END
  END pma_tx[348]
  PIN pma_tx[349]
    DIRECTION OUTPUT ;
    USE SIGNAL ;
    SHAPE ABUTMENT ;
    PORT
      LAYER M5 ;
      RECT 71.748 0.000 71.772 0.192 ;
    END
  END pma_tx[349]
  PIN pma_tx[350]
    DIRECTION OUTPUT ;
    USE SIGNAL ;
    SHAPE ABUTMENT ;
    PORT
      LAYER M5 ;
      RECT 71.940 0.000 71.964 0.192 ;
    END
  END pma_tx[350]
  PIN pma_tx[351]
    DIRECTION OUTPUT ;
    USE SIGNAL ;
    SHAPE ABUTMENT ;
    PORT
      LAYER M5 ;
      RECT 72.132 0.000 72.156 0.192 ;
    END
  END pma_tx[351]
  PIN pma_tx[352]
    DIRECTION OUTPUT ;
    USE SIGNAL ;
    SHAPE ABUTMENT ;
    PORT
      LAYER M5 ;
      RECT 72.324 0.000 72.348 0.192 ;
    END
  END pma_tx[352]
  PIN pma_tx[353]
    DIRECTION OUTPUT ;
    USE SIGNAL ;
    SHAPE ABUTMENT ;
    PORT
      LAYER M5 ;
      RECT 72.516 0.000 72.540 0.192 ;
    END
  END pma_tx[353]
  PIN pma_tx[354]
    DIRECTION OUTPUT ;
    USE SIGNAL ;
    SHAPE ABUTMENT ;
    PORT
      LAYER M5 ;
      RECT 72.708 0.000 72.732 0.192 ;
    END
  END pma_tx[354]
  PIN pma_tx[355]
    DIRECTION OUTPUT ;
    USE SIGNAL ;
    SHAPE ABUTMENT ;
    PORT
      LAYER M5 ;
      RECT 72.900 0.000 72.924 0.192 ;
    END
  END pma_tx[355]
  PIN pma_tx[356]
    DIRECTION OUTPUT ;
    USE SIGNAL ;
    SHAPE ABUTMENT ;
    PORT
      LAYER M5 ;
      RECT 73.092 0.000 73.116 0.192 ;
    END
  END pma_tx[356]
  PIN pma_tx[357]
    DIRECTION OUTPUT ;
    USE SIGNAL ;
    SHAPE ABUTMENT ;
    PORT
      LAYER M5 ;
      RECT 73.284 0.000 73.308 0.192 ;
    END
  END pma_tx[357]
  PIN pma_tx[358]
    DIRECTION OUTPUT ;
    USE SIGNAL ;
    SHAPE ABUTMENT ;
    PORT
      LAYER M5 ;
      RECT 73.476 0.000 73.500 0.192 ;
    END
  END pma_tx[358]
  PIN pma_tx[359]
    DIRECTION OUTPUT ;
    USE SIGNAL ;
    SHAPE ABUTMENT ;
    PORT
      LAYER M5 ;
      RECT 73.668 0.000 73.692 0.192 ;
    END
  END pma_tx[359]
  PIN pma_tx[360]
    DIRECTION OUTPUT ;
    USE SIGNAL ;
    SHAPE ABUTMENT ;
    PORT
      LAYER M5 ;
      RECT 73.860 0.000 73.884 0.192 ;
    END
  END pma_tx[360]
  PIN pma_tx[361]
    DIRECTION OUTPUT ;
    USE SIGNAL ;
    SHAPE ABUTMENT ;
    PORT
      LAYER M5 ;
      RECT 74.052 0.000 74.076 0.192 ;
    END
  END pma_tx[361]
  PIN pma_tx[362]
    DIRECTION OUTPUT ;
    USE SIGNAL ;
    SHAPE ABUTMENT ;
    PORT
      LAYER M5 ;
      RECT 74.244 0.000 74.268 0.192 ;
    END
  END pma_tx[362]
  PIN pma_tx[363]
    DIRECTION OUTPUT ;
    USE SIGNAL ;
    SHAPE ABUTMENT ;
    PORT
      LAYER M5 ;
      RECT 74.436 0.000 74.460 0.192 ;
    END
  END pma_tx[363]
  PIN pma_tx[364]
    DIRECTION OUTPUT ;
    USE SIGNAL ;
    SHAPE ABUTMENT ;
    PORT
      LAYER M5 ;
      RECT 74.628 0.000 74.652 0.192 ;
    END
  END pma_tx[364]
  PIN pma_tx[365]
    DIRECTION OUTPUT ;
    USE SIGNAL ;
    SHAPE ABUTMENT ;
    PORT
      LAYER M5 ;
      RECT 74.820 0.000 74.844 0.192 ;
    END
  END pma_tx[365]
  PIN pma_tx[366]
    DIRECTION OUTPUT ;
    USE SIGNAL ;
    SHAPE ABUTMENT ;
    PORT
      LAYER M5 ;
      RECT 75.012 0.000 75.036 0.192 ;
    END
  END pma_tx[366]
  PIN pma_tx[367]
    DIRECTION OUTPUT ;
    USE SIGNAL ;
    SHAPE ABUTMENT ;
    PORT
      LAYER M5 ;
      RECT 75.204 0.000 75.228 0.192 ;
    END
  END pma_tx[367]
  PIN pma_tx[368]
    DIRECTION OUTPUT ;
    USE SIGNAL ;
    SHAPE ABUTMENT ;
    PORT
      LAYER M5 ;
      RECT 75.396 0.000 75.420 0.192 ;
    END
  END pma_tx[368]
  PIN pma_tx[369]
    DIRECTION OUTPUT ;
    USE SIGNAL ;
    SHAPE ABUTMENT ;
    PORT
      LAYER M5 ;
      RECT 75.588 0.000 75.612 0.192 ;
    END
  END pma_tx[369]
  PIN pma_tx[370]
    DIRECTION OUTPUT ;
    USE SIGNAL ;
    SHAPE ABUTMENT ;
    PORT
      LAYER M5 ;
      RECT 75.780 0.000 75.804 0.192 ;
    END
  END pma_tx[370]
  PIN pma_tx[371]
    DIRECTION OUTPUT ;
    USE SIGNAL ;
    SHAPE ABUTMENT ;
    PORT
      LAYER M5 ;
      RECT 75.972 0.000 75.996 0.192 ;
    END
  END pma_tx[371]
  PIN pma_tx[372]
    DIRECTION OUTPUT ;
    USE SIGNAL ;
    SHAPE ABUTMENT ;
    PORT
      LAYER M5 ;
      RECT 76.164 0.000 76.188 0.192 ;
    END
  END pma_tx[372]
  PIN pma_tx[373]
    DIRECTION OUTPUT ;
    USE SIGNAL ;
    SHAPE ABUTMENT ;
    PORT
      LAYER M5 ;
      RECT 76.356 0.000 76.380 0.192 ;
    END
  END pma_tx[373]
  PIN pma_tx[374]
    DIRECTION OUTPUT ;
    USE SIGNAL ;
    SHAPE ABUTMENT ;
    PORT
      LAYER M5 ;
      RECT 76.548 0.000 76.572 0.192 ;
    END
  END pma_tx[374]
  PIN pma_tx[375]
    DIRECTION OUTPUT ;
    USE SIGNAL ;
    SHAPE ABUTMENT ;
    PORT
      LAYER M5 ;
      RECT 76.740 0.000 76.764 0.192 ;
    END
  END pma_tx[375]
  PIN pma_tx[376]
    DIRECTION OUTPUT ;
    USE SIGNAL ;
    SHAPE ABUTMENT ;
    PORT
      LAYER M5 ;
      RECT 76.932 0.000 76.956 0.192 ;
    END
  END pma_tx[376]
  PIN pma_tx[377]
    DIRECTION OUTPUT ;
    USE SIGNAL ;
    SHAPE ABUTMENT ;
    PORT
      LAYER M5 ;
      RECT 77.124 0.000 77.148 0.192 ;
    END
  END pma_tx[377]
  PIN pma_tx[378]
    DIRECTION OUTPUT ;
    USE SIGNAL ;
    SHAPE ABUTMENT ;
    PORT
      LAYER M5 ;
      RECT 77.316 0.000 77.340 0.192 ;
    END
  END pma_tx[378]
  PIN pma_tx[379]
    DIRECTION OUTPUT ;
    USE SIGNAL ;
    SHAPE ABUTMENT ;
    PORT
      LAYER M5 ;
      RECT 77.508 0.000 77.532 0.192 ;
    END
  END pma_tx[379]
  PIN pma_tx[380]
    DIRECTION OUTPUT ;
    USE SIGNAL ;
    SHAPE ABUTMENT ;
    PORT
      LAYER M5 ;
      RECT 77.700 0.000 77.724 0.192 ;
    END
  END pma_tx[380]
  PIN pma_tx[381]
    DIRECTION OUTPUT ;
    USE SIGNAL ;
    SHAPE ABUTMENT ;
    PORT
      LAYER M5 ;
      RECT 77.892 0.000 77.916 0.192 ;
    END
  END pma_tx[381]
  PIN pma_tx[382]
    DIRECTION OUTPUT ;
    USE SIGNAL ;
    SHAPE ABUTMENT ;
    PORT
      LAYER M5 ;
      RECT 78.084 0.000 78.108 0.192 ;
    END
  END pma_tx[382]
  PIN pma_tx[383]
    DIRECTION OUTPUT ;
    USE SIGNAL ;
    SHAPE ABUTMENT ;
    PORT
      LAYER M5 ;
      RECT 78.276 0.000 78.300 0.192 ;
    END
  END pma_tx[383]
  PIN pma_tx[384]
    DIRECTION OUTPUT ;
    USE SIGNAL ;
    SHAPE ABUTMENT ;
    PORT
      LAYER M5 ;
      RECT 78.468 0.000 78.492 0.192 ;
    END
  END pma_tx[384]
  PIN pma_tx[385]
    DIRECTION OUTPUT ;
    USE SIGNAL ;
    SHAPE ABUTMENT ;
    PORT
      LAYER M5 ;
      RECT 78.660 0.000 78.684 0.192 ;
    END
  END pma_tx[385]
  PIN pma_tx[386]
    DIRECTION OUTPUT ;
    USE SIGNAL ;
    SHAPE ABUTMENT ;
    PORT
      LAYER M5 ;
      RECT 78.852 0.000 78.876 0.192 ;
    END
  END pma_tx[386]
  PIN pma_tx[387]
    DIRECTION OUTPUT ;
    USE SIGNAL ;
    SHAPE ABUTMENT ;
    PORT
      LAYER M5 ;
      RECT 79.044 0.000 79.068 0.192 ;
    END
  END pma_tx[387]
  PIN pma_tx[388]
    DIRECTION OUTPUT ;
    USE SIGNAL ;
    SHAPE ABUTMENT ;
    PORT
      LAYER M5 ;
      RECT 79.236 0.000 79.260 0.192 ;
    END
  END pma_tx[388]
  PIN pma_tx[389]
    DIRECTION OUTPUT ;
    USE SIGNAL ;
    SHAPE ABUTMENT ;
    PORT
      LAYER M5 ;
      RECT 79.428 0.000 79.452 0.192 ;
    END
  END pma_tx[389]
  PIN pma_tx[390]
    DIRECTION OUTPUT ;
    USE SIGNAL ;
    SHAPE ABUTMENT ;
    PORT
      LAYER M5 ;
      RECT 79.620 0.000 79.644 0.192 ;
    END
  END pma_tx[390]
  PIN pma_tx[391]
    DIRECTION OUTPUT ;
    USE SIGNAL ;
    SHAPE ABUTMENT ;
    PORT
      LAYER M5 ;
      RECT 79.812 0.000 79.836 0.192 ;
    END
  END pma_tx[391]
  PIN pma_tx[392]
    DIRECTION OUTPUT ;
    USE SIGNAL ;
    SHAPE ABUTMENT ;
    PORT
      LAYER M5 ;
      RECT 80.004 0.000 80.028 0.192 ;
    END
  END pma_tx[392]
  PIN pma_tx[393]
    DIRECTION OUTPUT ;
    USE SIGNAL ;
    SHAPE ABUTMENT ;
    PORT
      LAYER M5 ;
      RECT 80.196 0.000 80.220 0.192 ;
    END
  END pma_tx[393]
  PIN pma_tx[394]
    DIRECTION OUTPUT ;
    USE SIGNAL ;
    SHAPE ABUTMENT ;
    PORT
      LAYER M5 ;
      RECT 80.388 0.000 80.412 0.192 ;
    END
  END pma_tx[394]
  PIN pma_tx[395]
    DIRECTION OUTPUT ;
    USE SIGNAL ;
    SHAPE ABUTMENT ;
    PORT
      LAYER M5 ;
      RECT 80.580 0.000 80.604 0.192 ;
    END
  END pma_tx[395]
  PIN pma_tx[396]
    DIRECTION OUTPUT ;
    USE SIGNAL ;
    SHAPE ABUTMENT ;
    PORT
      LAYER M5 ;
      RECT 80.772 0.000 80.796 0.192 ;
    END
  END pma_tx[396]
  PIN pma_tx[397]
    DIRECTION OUTPUT ;
    USE SIGNAL ;
    SHAPE ABUTMENT ;
    PORT
      LAYER M5 ;
      RECT 80.964 0.000 80.988 0.192 ;
    END
  END pma_tx[397]
  PIN pma_tx[398]
    DIRECTION OUTPUT ;
    USE SIGNAL ;
    SHAPE ABUTMENT ;
    PORT
      LAYER M5 ;
      RECT 81.156 0.000 81.180 0.192 ;
    END
  END pma_tx[398]
  PIN pma_tx[399]
    DIRECTION OUTPUT ;
    USE SIGNAL ;
    SHAPE ABUTMENT ;
    PORT
      LAYER M5 ;
      RECT 81.348 0.000 81.372 0.192 ;
    END
  END pma_tx[399]
  PIN pma_tx[400]
    DIRECTION OUTPUT ;
    USE SIGNAL ;
    SHAPE ABUTMENT ;
    PORT
      LAYER M5 ;
      RECT 81.540 0.000 81.564 0.192 ;
    END
  END pma_tx[400]
  PIN pma_tx[401]
    DIRECTION OUTPUT ;
    USE SIGNAL ;
    SHAPE ABUTMENT ;
    PORT
      LAYER M5 ;
      RECT 81.732 0.000 81.756 0.192 ;
    END
  END pma_tx[401]
  PIN pma_tx[402]
    DIRECTION OUTPUT ;
    USE SIGNAL ;
    SHAPE ABUTMENT ;
    PORT
      LAYER M5 ;
      RECT 81.924 0.000 81.948 0.192 ;
    END
  END pma_tx[402]
  PIN pma_tx[403]
    DIRECTION OUTPUT ;
    USE SIGNAL ;
    SHAPE ABUTMENT ;
    PORT
      LAYER M5 ;
      RECT 82.116 0.000 82.140 0.192 ;
    END
  END pma_tx[403]
  PIN pma_tx[404]
    DIRECTION OUTPUT ;
    USE SIGNAL ;
    SHAPE ABUTMENT ;
    PORT
      LAYER M5 ;
      RECT 82.308 0.000 82.332 0.192 ;
    END
  END pma_tx[404]
  PIN pma_tx[405]
    DIRECTION OUTPUT ;
    USE SIGNAL ;
    SHAPE ABUTMENT ;
    PORT
      LAYER M5 ;
      RECT 82.500 0.000 82.524 0.192 ;
    END
  END pma_tx[405]
  PIN pma_tx[406]
    DIRECTION OUTPUT ;
    USE SIGNAL ;
    SHAPE ABUTMENT ;
    PORT
      LAYER M5 ;
      RECT 82.692 0.000 82.716 0.192 ;
    END
  END pma_tx[406]
  PIN pma_tx[407]
    DIRECTION OUTPUT ;
    USE SIGNAL ;
    SHAPE ABUTMENT ;
    PORT
      LAYER M5 ;
      RECT 82.884 0.000 82.908 0.192 ;
    END
  END pma_tx[407]
  PIN pma_tx[408]
    DIRECTION OUTPUT ;
    USE SIGNAL ;
    SHAPE ABUTMENT ;
    PORT
      LAYER M5 ;
      RECT 83.076 0.000 83.100 0.192 ;
    END
  END pma_tx[408]
  PIN pma_tx[409]
    DIRECTION OUTPUT ;
    USE SIGNAL ;
    SHAPE ABUTMENT ;
    PORT
      LAYER M5 ;
      RECT 83.268 0.000 83.292 0.192 ;
    END
  END pma_tx[409]
  PIN pma_tx[410]
    DIRECTION OUTPUT ;
    USE SIGNAL ;
    SHAPE ABUTMENT ;
    PORT
      LAYER M5 ;
      RECT 83.460 0.000 83.484 0.192 ;
    END
  END pma_tx[410]
  PIN pma_tx[411]
    DIRECTION OUTPUT ;
    USE SIGNAL ;
    SHAPE ABUTMENT ;
    PORT
      LAYER M5 ;
      RECT 83.652 0.000 83.676 0.192 ;
    END
  END pma_tx[411]
  PIN pma_tx[412]
    DIRECTION OUTPUT ;
    USE SIGNAL ;
    SHAPE ABUTMENT ;
    PORT
      LAYER M5 ;
      RECT 83.844 0.000 83.868 0.192 ;
    END
  END pma_tx[412]
  PIN pma_tx[413]
    DIRECTION OUTPUT ;
    USE SIGNAL ;
    SHAPE ABUTMENT ;
    PORT
      LAYER M5 ;
      RECT 84.036 0.000 84.060 0.192 ;
    END
  END pma_tx[413]
  PIN pma_tx[414]
    DIRECTION OUTPUT ;
    USE SIGNAL ;
    SHAPE ABUTMENT ;
    PORT
      LAYER M5 ;
      RECT 84.228 0.000 84.252 0.192 ;
    END
  END pma_tx[414]
  PIN pma_tx[415]
    DIRECTION OUTPUT ;
    USE SIGNAL ;
    SHAPE ABUTMENT ;
    PORT
      LAYER M5 ;
      RECT 84.420 0.000 84.444 0.192 ;
    END
  END pma_tx[415]
  PIN pma_tx[416]
    DIRECTION OUTPUT ;
    USE SIGNAL ;
    SHAPE ABUTMENT ;
    PORT
      LAYER M5 ;
      RECT 84.612 0.000 84.636 0.192 ;
    END
  END pma_tx[416]
  PIN pma_tx[417]
    DIRECTION OUTPUT ;
    USE SIGNAL ;
    SHAPE ABUTMENT ;
    PORT
      LAYER M5 ;
      RECT 84.804 0.000 84.828 0.192 ;
    END
  END pma_tx[417]
  PIN pma_tx[418]
    DIRECTION OUTPUT ;
    USE SIGNAL ;
    SHAPE ABUTMENT ;
    PORT
      LAYER M5 ;
      RECT 84.996 0.000 85.020 0.192 ;
    END
  END pma_tx[418]
  PIN pma_tx[419]
    DIRECTION OUTPUT ;
    USE SIGNAL ;
    SHAPE ABUTMENT ;
    PORT
      LAYER M5 ;
      RECT 85.188 0.000 85.212 0.192 ;
    END
  END pma_tx[419]
  PIN pma_tx[420]
    DIRECTION OUTPUT ;
    USE SIGNAL ;
    SHAPE ABUTMENT ;
    PORT
      LAYER M5 ;
      RECT 85.380 0.000 85.404 0.192 ;
    END
  END pma_tx[420]
  PIN pma_tx[421]
    DIRECTION OUTPUT ;
    USE SIGNAL ;
    SHAPE ABUTMENT ;
    PORT
      LAYER M5 ;
      RECT 85.572 0.000 85.596 0.192 ;
    END
  END pma_tx[421]
  PIN pma_tx[422]
    DIRECTION OUTPUT ;
    USE SIGNAL ;
    SHAPE ABUTMENT ;
    PORT
      LAYER M5 ;
      RECT 85.764 0.000 85.788 0.192 ;
    END
  END pma_tx[422]
  PIN pma_tx[423]
    DIRECTION OUTPUT ;
    USE SIGNAL ;
    SHAPE ABUTMENT ;
    PORT
      LAYER M5 ;
      RECT 85.956 0.000 85.980 0.192 ;
    END
  END pma_tx[423]
  PIN pma_tx[424]
    DIRECTION OUTPUT ;
    USE SIGNAL ;
    SHAPE ABUTMENT ;
    PORT
      LAYER M5 ;
      RECT 86.148 0.000 86.172 0.192 ;
    END
  END pma_tx[424]
  PIN pma_tx[425]
    DIRECTION OUTPUT ;
    USE SIGNAL ;
    SHAPE ABUTMENT ;
    PORT
      LAYER M5 ;
      RECT 86.340 0.000 86.364 0.192 ;
    END
  END pma_tx[425]
  PIN pma_tx[426]
    DIRECTION OUTPUT ;
    USE SIGNAL ;
    SHAPE ABUTMENT ;
    PORT
      LAYER M5 ;
      RECT 86.532 0.000 86.556 0.192 ;
    END
  END pma_tx[426]
  PIN pma_tx[427]
    DIRECTION OUTPUT ;
    USE SIGNAL ;
    SHAPE ABUTMENT ;
    PORT
      LAYER M5 ;
      RECT 86.724 0.000 86.748 0.192 ;
    END
  END pma_tx[427]
  PIN pma_tx[428]
    DIRECTION OUTPUT ;
    USE SIGNAL ;
    SHAPE ABUTMENT ;
    PORT
      LAYER M5 ;
      RECT 86.916 0.000 86.940 0.192 ;
    END
  END pma_tx[428]
  PIN pma_tx[429]
    DIRECTION OUTPUT ;
    USE SIGNAL ;
    SHAPE ABUTMENT ;
    PORT
      LAYER M5 ;
      RECT 87.108 0.000 87.132 0.192 ;
    END
  END pma_tx[429]
  PIN pma_tx[430]
    DIRECTION OUTPUT ;
    USE SIGNAL ;
    SHAPE ABUTMENT ;
    PORT
      LAYER M5 ;
      RECT 87.300 0.000 87.324 0.192 ;
    END
  END pma_tx[430]
  PIN pma_tx[431]
    DIRECTION OUTPUT ;
    USE SIGNAL ;
    SHAPE ABUTMENT ;
    PORT
      LAYER M5 ;
      RECT 87.492 0.000 87.516 0.192 ;
    END
  END pma_tx[431]
  PIN pma_tx[432]
    DIRECTION OUTPUT ;
    USE SIGNAL ;
    SHAPE ABUTMENT ;
    PORT
      LAYER M5 ;
      RECT 87.684 0.000 87.708 0.192 ;
    END
  END pma_tx[432]
  PIN pma_tx[433]
    DIRECTION OUTPUT ;
    USE SIGNAL ;
    SHAPE ABUTMENT ;
    PORT
      LAYER M5 ;
      RECT 87.876 0.000 87.900 0.192 ;
    END
  END pma_tx[433]
  PIN pma_tx[434]
    DIRECTION OUTPUT ;
    USE SIGNAL ;
    SHAPE ABUTMENT ;
    PORT
      LAYER M5 ;
      RECT 88.068 0.000 88.092 0.192 ;
    END
  END pma_tx[434]
  PIN pma_tx[435]
    DIRECTION OUTPUT ;
    USE SIGNAL ;
    SHAPE ABUTMENT ;
    PORT
      LAYER M5 ;
      RECT 88.260 0.000 88.284 0.192 ;
    END
  END pma_tx[435]
  PIN pma_tx[436]
    DIRECTION OUTPUT ;
    USE SIGNAL ;
    SHAPE ABUTMENT ;
    PORT
      LAYER M5 ;
      RECT 88.452 0.000 88.476 0.192 ;
    END
  END pma_tx[436]
  PIN pma_tx[437]
    DIRECTION OUTPUT ;
    USE SIGNAL ;
    SHAPE ABUTMENT ;
    PORT
      LAYER M5 ;
      RECT 88.644 0.000 88.668 0.192 ;
    END
  END pma_tx[437]
  PIN pma_tx[438]
    DIRECTION OUTPUT ;
    USE SIGNAL ;
    SHAPE ABUTMENT ;
    PORT
      LAYER M5 ;
      RECT 88.836 0.000 88.860 0.192 ;
    END
  END pma_tx[438]
  PIN pma_tx[439]
    DIRECTION OUTPUT ;
    USE SIGNAL ;
    SHAPE ABUTMENT ;
    PORT
      LAYER M5 ;
      RECT 89.028 0.000 89.052 0.192 ;
    END
  END pma_tx[439]
  PIN pma_tx[440]
    DIRECTION OUTPUT ;
    USE SIGNAL ;
    SHAPE ABUTMENT ;
    PORT
      LAYER M5 ;
      RECT 89.220 0.000 89.244 0.192 ;
    END
  END pma_tx[440]
  PIN pma_tx[441]
    DIRECTION OUTPUT ;
    USE SIGNAL ;
    SHAPE ABUTMENT ;
    PORT
      LAYER M5 ;
      RECT 89.412 0.000 89.436 0.192 ;
    END
  END pma_tx[441]
  PIN pma_tx[442]
    DIRECTION OUTPUT ;
    USE SIGNAL ;
    SHAPE ABUTMENT ;
    PORT
      LAYER M5 ;
      RECT 89.604 0.000 89.628 0.192 ;
    END
  END pma_tx[442]
  PIN pma_tx[443]
    DIRECTION OUTPUT ;
    USE SIGNAL ;
    SHAPE ABUTMENT ;
    PORT
      LAYER M5 ;
      RECT 89.796 0.000 89.820 0.192 ;
    END
  END pma_tx[443]
  PIN pma_tx[444]
    DIRECTION OUTPUT ;
    USE SIGNAL ;
    SHAPE ABUTMENT ;
    PORT
      LAYER M5 ;
      RECT 89.988 0.000 90.012 0.192 ;
    END
  END pma_tx[444]
  PIN pma_tx[445]
    DIRECTION OUTPUT ;
    USE SIGNAL ;
    SHAPE ABUTMENT ;
    PORT
      LAYER M5 ;
      RECT 90.180 0.000 90.204 0.192 ;
    END
  END pma_tx[445]
  PIN pma_tx[446]
    DIRECTION OUTPUT ;
    USE SIGNAL ;
    SHAPE ABUTMENT ;
    PORT
      LAYER M5 ;
      RECT 90.372 0.000 90.396 0.192 ;
    END
  END pma_tx[446]
  PIN pma_tx[447]
    DIRECTION OUTPUT ;
    USE SIGNAL ;
    SHAPE ABUTMENT ;
    PORT
      LAYER M5 ;
      RECT 90.564 0.000 90.588 0.192 ;
    END
  END pma_tx[447]
  PIN pma_tx[448]
    DIRECTION OUTPUT ;
    USE SIGNAL ;
    SHAPE ABUTMENT ;
    PORT
      LAYER M5 ;
      RECT 90.756 0.000 90.780 0.192 ;
    END
  END pma_tx[448]
  PIN pma_tx[449]
    DIRECTION OUTPUT ;
    USE SIGNAL ;
    SHAPE ABUTMENT ;
    PORT
      LAYER M5 ;
      RECT 90.948 0.000 90.972 0.192 ;
    END
  END pma_tx[449]
  PIN pma_tx[450]
    DIRECTION OUTPUT ;
    USE SIGNAL ;
    SHAPE ABUTMENT ;
    PORT
      LAYER M5 ;
      RECT 91.140 0.000 91.164 0.192 ;
    END
  END pma_tx[450]
  PIN pma_tx[451]
    DIRECTION OUTPUT ;
    USE SIGNAL ;
    SHAPE ABUTMENT ;
    PORT
      LAYER M5 ;
      RECT 91.332 0.000 91.356 0.192 ;
    END
  END pma_tx[451]
  PIN pma_tx[452]
    DIRECTION OUTPUT ;
    USE SIGNAL ;
    SHAPE ABUTMENT ;
    PORT
      LAYER M5 ;
      RECT 91.524 0.000 91.548 0.192 ;
    END
  END pma_tx[452]
  PIN pma_tx[453]
    DIRECTION OUTPUT ;
    USE SIGNAL ;
    SHAPE ABUTMENT ;
    PORT
      LAYER M5 ;
      RECT 91.716 0.000 91.740 0.192 ;
    END
  END pma_tx[453]
  PIN pma_tx[454]
    DIRECTION OUTPUT ;
    USE SIGNAL ;
    SHAPE ABUTMENT ;
    PORT
      LAYER M5 ;
      RECT 91.908 0.000 91.932 0.192 ;
    END
  END pma_tx[454]
  PIN pma_tx[455]
    DIRECTION OUTPUT ;
    USE SIGNAL ;
    SHAPE ABUTMENT ;
    PORT
      LAYER M5 ;
      RECT 92.100 0.000 92.124 0.192 ;
    END
  END pma_tx[455]
  PIN pma_tx[456]
    DIRECTION OUTPUT ;
    USE SIGNAL ;
    SHAPE ABUTMENT ;
    PORT
      LAYER M5 ;
      RECT 92.292 0.000 92.316 0.192 ;
    END
  END pma_tx[456]
  PIN pma_tx[457]
    DIRECTION OUTPUT ;
    USE SIGNAL ;
    SHAPE ABUTMENT ;
    PORT
      LAYER M5 ;
      RECT 92.484 0.000 92.508 0.192 ;
    END
  END pma_tx[457]
  PIN pma_tx[458]
    DIRECTION OUTPUT ;
    USE SIGNAL ;
    SHAPE ABUTMENT ;
    PORT
      LAYER M5 ;
      RECT 92.676 0.000 92.700 0.192 ;
    END
  END pma_tx[458]
  PIN pma_tx[459]
    DIRECTION OUTPUT ;
    USE SIGNAL ;
    SHAPE ABUTMENT ;
    PORT
      LAYER M5 ;
      RECT 92.868 0.000 92.892 0.192 ;
    END
  END pma_tx[459]
  PIN pma_tx[460]
    DIRECTION OUTPUT ;
    USE SIGNAL ;
    SHAPE ABUTMENT ;
    PORT
      LAYER M5 ;
      RECT 93.060 0.000 93.084 0.192 ;
    END
  END pma_tx[460]
  PIN pma_tx[461]
    DIRECTION OUTPUT ;
    USE SIGNAL ;
    SHAPE ABUTMENT ;
    PORT
      LAYER M5 ;
      RECT 93.252 0.000 93.276 0.192 ;
    END
  END pma_tx[461]
  PIN pma_tx[462]
    DIRECTION OUTPUT ;
    USE SIGNAL ;
    SHAPE ABUTMENT ;
    PORT
      LAYER M5 ;
      RECT 93.444 0.000 93.468 0.192 ;
    END
  END pma_tx[462]
  PIN pma_tx[463]
    DIRECTION OUTPUT ;
    USE SIGNAL ;
    SHAPE ABUTMENT ;
    PORT
      LAYER M5 ;
      RECT 93.636 0.000 93.660 0.192 ;
    END
  END pma_tx[463]
  PIN pma_tx[464]
    DIRECTION OUTPUT ;
    USE SIGNAL ;
    SHAPE ABUTMENT ;
    PORT
      LAYER M5 ;
      RECT 93.828 0.000 93.852 0.192 ;
    END
  END pma_tx[464]
  PIN pma_tx[465]
    DIRECTION OUTPUT ;
    USE SIGNAL ;
    SHAPE ABUTMENT ;
    PORT
      LAYER M5 ;
      RECT 94.020 0.000 94.044 0.192 ;
    END
  END pma_tx[465]
  PIN pma_tx[466]
    DIRECTION OUTPUT ;
    USE SIGNAL ;
    SHAPE ABUTMENT ;
    PORT
      LAYER M5 ;
      RECT 94.212 0.000 94.236 0.192 ;
    END
  END pma_tx[466]
  PIN pma_tx[467]
    DIRECTION OUTPUT ;
    USE SIGNAL ;
    SHAPE ABUTMENT ;
    PORT
      LAYER M5 ;
      RECT 94.404 0.000 94.428 0.192 ;
    END
  END pma_tx[467]
  PIN pma_tx[468]
    DIRECTION OUTPUT ;
    USE SIGNAL ;
    SHAPE ABUTMENT ;
    PORT
      LAYER M5 ;
      RECT 94.596 0.000 94.620 0.192 ;
    END
  END pma_tx[468]
  PIN pma_tx[469]
    DIRECTION OUTPUT ;
    USE SIGNAL ;
    SHAPE ABUTMENT ;
    PORT
      LAYER M5 ;
      RECT 94.788 0.000 94.812 0.192 ;
    END
  END pma_tx[469]
  PIN pma_tx[470]
    DIRECTION OUTPUT ;
    USE SIGNAL ;
    SHAPE ABUTMENT ;
    PORT
      LAYER M5 ;
      RECT 94.980 0.000 95.004 0.192 ;
    END
  END pma_tx[470]
  PIN pma_tx[471]
    DIRECTION OUTPUT ;
    USE SIGNAL ;
    SHAPE ABUTMENT ;
    PORT
      LAYER M5 ;
      RECT 95.172 0.000 95.196 0.192 ;
    END
  END pma_tx[471]
  PIN pma_tx[472]
    DIRECTION OUTPUT ;
    USE SIGNAL ;
    SHAPE ABUTMENT ;
    PORT
      LAYER M5 ;
      RECT 95.364 0.000 95.388 0.192 ;
    END
  END pma_tx[472]
  PIN pma_tx[473]
    DIRECTION OUTPUT ;
    USE SIGNAL ;
    SHAPE ABUTMENT ;
    PORT
      LAYER M5 ;
      RECT 95.556 0.000 95.580 0.192 ;
    END
  END pma_tx[473]
  PIN pma_tx[474]
    DIRECTION OUTPUT ;
    USE SIGNAL ;
    SHAPE ABUTMENT ;
    PORT
      LAYER M5 ;
      RECT 95.748 0.000 95.772 0.192 ;
    END
  END pma_tx[474]
  PIN pma_tx[475]
    DIRECTION OUTPUT ;
    USE SIGNAL ;
    SHAPE ABUTMENT ;
    PORT
      LAYER M5 ;
      RECT 95.940 0.000 95.964 0.192 ;
    END
  END pma_tx[475]
  PIN pma_tx[476]
    DIRECTION OUTPUT ;
    USE SIGNAL ;
    SHAPE ABUTMENT ;
    PORT
      LAYER M5 ;
      RECT 96.132 0.000 96.156 0.192 ;
    END
  END pma_tx[476]
  PIN pma_tx[477]
    DIRECTION OUTPUT ;
    USE SIGNAL ;
    SHAPE ABUTMENT ;
    PORT
      LAYER M5 ;
      RECT 96.324 0.000 96.348 0.192 ;
    END
  END pma_tx[477]
  PIN pma_tx[478]
    DIRECTION OUTPUT ;
    USE SIGNAL ;
    SHAPE ABUTMENT ;
    PORT
      LAYER M5 ;
      RECT 96.516 0.000 96.540 0.192 ;
    END
  END pma_tx[478]
  PIN pma_tx[479]
    DIRECTION OUTPUT ;
    USE SIGNAL ;
    SHAPE ABUTMENT ;
    PORT
      LAYER M5 ;
      RECT 96.708 0.000 96.732 0.192 ;
    END
  END pma_tx[479]
  PIN pma_tx[480]
    DIRECTION OUTPUT ;
    USE SIGNAL ;
    SHAPE ABUTMENT ;
    PORT
      LAYER M5 ;
      RECT 96.900 0.000 96.924 0.192 ;
    END
  END pma_tx[480]
  PIN pma_tx[481]
    DIRECTION OUTPUT ;
    USE SIGNAL ;
    SHAPE ABUTMENT ;
    PORT
      LAYER M5 ;
      RECT 97.092 0.000 97.116 0.192 ;
    END
  END pma_tx[481]
  PIN pma_tx[482]
    DIRECTION OUTPUT ;
    USE SIGNAL ;
    SHAPE ABUTMENT ;
    PORT
      LAYER M5 ;
      RECT 97.284 0.000 97.308 0.192 ;
    END
  END pma_tx[482]
  PIN pma_tx[483]
    DIRECTION OUTPUT ;
    USE SIGNAL ;
    SHAPE ABUTMENT ;
    PORT
      LAYER M5 ;
      RECT 97.476 0.000 97.500 0.192 ;
    END
  END pma_tx[483]
  PIN pma_tx[484]
    DIRECTION OUTPUT ;
    USE SIGNAL ;
    SHAPE ABUTMENT ;
    PORT
      LAYER M5 ;
      RECT 97.668 0.000 97.692 0.192 ;
    END
  END pma_tx[484]
  PIN pma_tx[485]
    DIRECTION OUTPUT ;
    USE SIGNAL ;
    SHAPE ABUTMENT ;
    PORT
      LAYER M5 ;
      RECT 97.860 0.000 97.884 0.192 ;
    END
  END pma_tx[485]
  PIN pma_tx[486]
    DIRECTION OUTPUT ;
    USE SIGNAL ;
    SHAPE ABUTMENT ;
    PORT
      LAYER M5 ;
      RECT 98.052 0.000 98.076 0.192 ;
    END
  END pma_tx[486]
  PIN pma_tx[487]
    DIRECTION OUTPUT ;
    USE SIGNAL ;
    SHAPE ABUTMENT ;
    PORT
      LAYER M5 ;
      RECT 98.244 0.000 98.268 0.192 ;
    END
  END pma_tx[487]
  PIN pma_tx[488]
    DIRECTION OUTPUT ;
    USE SIGNAL ;
    SHAPE ABUTMENT ;
    PORT
      LAYER M5 ;
      RECT 98.436 0.000 98.460 0.192 ;
    END
  END pma_tx[488]
  PIN pma_tx[489]
    DIRECTION OUTPUT ;
    USE SIGNAL ;
    SHAPE ABUTMENT ;
    PORT
      LAYER M5 ;
      RECT 98.628 0.000 98.652 0.192 ;
    END
  END pma_tx[489]
  PIN pma_tx[490]
    DIRECTION OUTPUT ;
    USE SIGNAL ;
    SHAPE ABUTMENT ;
    PORT
      LAYER M5 ;
      RECT 98.820 0.000 98.844 0.192 ;
    END
  END pma_tx[490]
  PIN pma_tx[491]
    DIRECTION OUTPUT ;
    USE SIGNAL ;
    SHAPE ABUTMENT ;
    PORT
      LAYER M5 ;
      RECT 99.012 0.000 99.036 0.192 ;
    END
  END pma_tx[491]
  PIN pma_tx[492]
    DIRECTION OUTPUT ;
    USE SIGNAL ;
    SHAPE ABUTMENT ;
    PORT
      LAYER M5 ;
      RECT 99.204 0.000 99.228 0.192 ;
    END
  END pma_tx[492]
  PIN pma_tx[493]
    DIRECTION OUTPUT ;
    USE SIGNAL ;
    SHAPE ABUTMENT ;
    PORT
      LAYER M5 ;
      RECT 99.396 0.000 99.420 0.192 ;
    END
  END pma_tx[493]
  PIN pma_tx[494]
    DIRECTION OUTPUT ;
    USE SIGNAL ;
    SHAPE ABUTMENT ;
    PORT
      LAYER M5 ;
      RECT 99.588 0.000 99.612 0.192 ;
    END
  END pma_tx[494]
  PIN pma_tx[495]
    DIRECTION OUTPUT ;
    USE SIGNAL ;
    SHAPE ABUTMENT ;
    PORT
      LAYER M5 ;
      RECT 99.780 0.000 99.804 0.192 ;
    END
  END pma_tx[495]
  PIN pma_tx[496]
    DIRECTION OUTPUT ;
    USE SIGNAL ;
    SHAPE ABUTMENT ;
    PORT
      LAYER M5 ;
      RECT 99.972 0.000 99.996 0.192 ;
    END
  END pma_tx[496]
  PIN pma_tx[497]
    DIRECTION OUTPUT ;
    USE SIGNAL ;
    SHAPE ABUTMENT ;
    PORT
      LAYER M5 ;
      RECT 100.164 0.000 100.188 0.192 ;
    END
  END pma_tx[497]
  PIN pma_tx[498]
    DIRECTION OUTPUT ;
    USE SIGNAL ;
    SHAPE ABUTMENT ;
    PORT
      LAYER M5 ;
      RECT 100.356 0.000 100.380 0.192 ;
    END
  END pma_tx[498]
  PIN pma_tx[499]
    DIRECTION OUTPUT ;
    USE SIGNAL ;
    SHAPE ABUTMENT ;
    PORT
      LAYER M5 ;
      RECT 100.548 0.000 100.572 0.192 ;
    END
  END pma_tx[499]
  PIN pma_tx[500]
    DIRECTION OUTPUT ;
    USE SIGNAL ;
    SHAPE ABUTMENT ;
    PORT
      LAYER M5 ;
      RECT 100.740 0.000 100.764 0.192 ;
    END
  END pma_tx[500]
  PIN pma_tx[501]
    DIRECTION OUTPUT ;
    USE SIGNAL ;
    SHAPE ABUTMENT ;
    PORT
      LAYER M5 ;
      RECT 100.932 0.000 100.956 0.192 ;
    END
  END pma_tx[501]
  PIN pma_tx[502]
    DIRECTION OUTPUT ;
    USE SIGNAL ;
    SHAPE ABUTMENT ;
    PORT
      LAYER M5 ;
      RECT 101.124 0.000 101.148 0.192 ;
    END
  END pma_tx[502]
  PIN pma_tx[503]
    DIRECTION OUTPUT ;
    USE SIGNAL ;
    SHAPE ABUTMENT ;
    PORT
      LAYER M5 ;
      RECT 101.316 0.000 101.340 0.192 ;
    END
  END pma_tx[503]
  PIN pma_tx[504]
    DIRECTION OUTPUT ;
    USE SIGNAL ;
    SHAPE ABUTMENT ;
    PORT
      LAYER M5 ;
      RECT 101.508 0.000 101.532 0.192 ;
    END
  END pma_tx[504]
  PIN pma_tx[505]
    DIRECTION OUTPUT ;
    USE SIGNAL ;
    SHAPE ABUTMENT ;
    PORT
      LAYER M5 ;
      RECT 101.700 0.000 101.724 0.192 ;
    END
  END pma_tx[505]
  PIN pma_tx[506]
    DIRECTION OUTPUT ;
    USE SIGNAL ;
    SHAPE ABUTMENT ;
    PORT
      LAYER M5 ;
      RECT 101.892 0.000 101.916 0.192 ;
    END
  END pma_tx[506]
  PIN pma_tx[507]
    DIRECTION OUTPUT ;
    USE SIGNAL ;
    SHAPE ABUTMENT ;
    PORT
      LAYER M5 ;
      RECT 102.084 0.000 102.108 0.192 ;
    END
  END pma_tx[507]
  PIN pma_tx[508]
    DIRECTION OUTPUT ;
    USE SIGNAL ;
    SHAPE ABUTMENT ;
    PORT
      LAYER M5 ;
      RECT 102.276 0.000 102.300 0.192 ;
    END
  END pma_tx[508]
  PIN pma_tx[509]
    DIRECTION OUTPUT ;
    USE SIGNAL ;
    SHAPE ABUTMENT ;
    PORT
      LAYER M5 ;
      RECT 102.468 0.000 102.492 0.192 ;
    END
  END pma_tx[509]
  PIN pma_tx[510]
    DIRECTION OUTPUT ;
    USE SIGNAL ;
    SHAPE ABUTMENT ;
    PORT
      LAYER M5 ;
      RECT 102.660 0.000 102.684 0.192 ;
    END
  END pma_tx[510]
  PIN pma_tx[511]
    DIRECTION OUTPUT ;
    USE SIGNAL ;
    SHAPE ABUTMENT ;
    PORT
      LAYER M5 ;
      RECT 102.852 0.000 102.876 0.192 ;
    END
  END pma_tx[511]
  PIN pma_tx[512]
    DIRECTION OUTPUT ;
    USE SIGNAL ;
    SHAPE ABUTMENT ;
    PORT
      LAYER M5 ;
      RECT 103.044 0.000 103.068 0.192 ;
    END
  END pma_tx[512]
  PIN pma_tck
    DIRECTION OUTPUT ;
    USE SIGNAL ;
    SHAPE ABUTMENT ;
    PORT
      LAYER M5 ;
      RECT 103.236 0.000 103.260 0.192 ;
    END
  END pma_tck
  PIN VDD
    DIRECTION INOUT ;
    USE POWER ;
    PORT
      LAYER M5 ;
      RECT 0.300 2.000 0.420 1250.800 ;
      RECT 5.700 2.000 5.820 1250.800 ;
      RECT 11.100 2.000 11.220 1250.800 ;
      RECT 16.500 2.000 16.620 1250.800 ;
      RECT 21.900 2.000 22.020 1250.800 ;
      RECT 27.300 2.000 27.420 1250.800 ;
      RECT 32.700 2.000 32.820 1250.800 ;
      RECT 38.100 2.000 38.220 1250.800 ;
      RECT 43.500 2.000 43.620 1250.800 ;
      RECT 48.900 2.000 49.020 1250.800 ;
      RECT 54.300 2.000 54.420 1250.800 ;
      RECT 59.700 2.000 59.820 1250.800 ;
      RECT 65.100 2.000 65.220 1250.800 ;
      RECT 70.500 2.000 70.620 1250.800 ;
      RECT 75.900 2.000 76.020 1250.800 ;
      RECT 81.300 2.000 81.420 1250.800 ;
      RECT 86.700 2.000 86.820 1250.800 ;
      RECT 92.100 2.000 92.220 1250.800 ;
      RECT 97.500 2.000 97.620 1250.800 ;
      RECT 102.900 2.000 103.020 1250.800 ;
    END
  END VDD
  PIN VSS
    DIRECTION INOUT ;
    USE GROUND ;
    PORT
      LAYER M5 ;
      RECT 0.492 2.000 0.612 1250.800 ;
      RECT 5.892 2.000 6.012 1250.800 ;
      RECT 11.292 2.000 11.412 1250.800 ;
      RECT 16.692 2.000 16.812 1250.800 ;
      RECT 22.092 2.000 22.212 1250.800 ;
      RECT 27.492 2.000 27.612 1250.800 ;
      RECT 32.892 2.000 33.012 1250.800 ;
      RECT 38.292 2.000 38.412 1250.800 ;
      RECT 43.692 2.000 43.812 1250.800 ;
      RECT 49.092 2.000 49.212 1250.800 ;
      RECT 54.492 2.000 54.612 1250.800 ;
      RECT 59.892 2.000 60.012 1250.800 ;
      RECT 65.292 2.000 65.412 1250.800 ;
      RECT 70.692 2.000 70.812 1250.800 ;
      RECT 76.092 2.000 76.212 1250.800 ;
      RECT 81.492 2.000 81.612 1250.800 ;
      RECT 86.892 2.000 87.012 1250.800 ;
      RECT 92.292 2.000 92.412 1250.800 ;
      RECT 97.692 2.000 97.812 1250.800 ;
      RECT 103.092 2.000 103.212 1250.800 ;
    END
  END VSS
  OBS
    LAYER M1 ;
    RECT 0 0 108.000 1252.800 ;
    LAYER M2 ;
    RECT 0 0 108.000 1252.800 ;
    LAYER M3 ;
    RECT 0 0 108.000 1252.800 ;
    LAYER M4 ;
    RECT 0 0 108.000 1252.800 ;
    LAYER M5 ;
    RECT 0.000 0.600 0.228 1252.200 ;
    RECT 0.684 0.600 5.628 1252.200 ;
    RECT 6.084 0.600 11.028 1252.200 ;
    RECT 11.484 0.600 16.428 1252.200 ;
    RECT 16.884 0.600 21.828 1252.200 ;
    RECT 22.284 0.600 27.228 1252.200 ;
    RECT 27.684 0.600 32.628 1252.200 ;
    RECT 33.084 0.600 38.028 1252.200 ;
    RECT 38.484 0.600 43.428 1252.200 ;
    RECT 43.884 0.600 48.828 1252.200 ;
    RECT 49.284 0.600 54.228 1252.200 ;
    RECT 54.684 0.600 59.628 1252.200 ;
    RECT 60.084 0.600 65.028 1252.200 ;
    RECT 65.484 0.600 70.428 1252.200 ;
    RECT 70.884 0.600 75.828 1252.200 ;
    RECT 76.284 0.600 81.228 1252.200 ;
    RECT 81.684 0.600 86.628 1252.200 ;
    RECT 87.084 0.600 92.028 1252.200 ;
    RECT 92.484 0.600 97.428 1252.200 ;
    RECT 97.884 0.600 102.828 1252.200 ;
    RECT 103.284 0.600 108.000 1252.200 ;
    RECT 0.300 0.600 0.420 1.928 ;
    RECT 0.300 1250.872 0.420 1252.200 ;
    RECT 0.492 0.600 0.612 1.928 ;
    RECT 0.492 1250.872 0.612 1252.200 ;
    RECT 5.700 0.600 5.820 1.928 ;
    RECT 5.700 1250.872 5.820 1252.200 ;
    RECT 5.892 0.600 6.012 1.928 ;
    RECT 5.892 1250.872 6.012 1252.200 ;
    RECT 11.100 0.600 11.220 1.928 ;
    RECT 11.100 1250.872 11.220 1252.200 ;
    RECT 11.292 0.600 11.412 1.928 ;
    RECT 11.292 1250.872 11.412 1252.200 ;
    RECT 16.500 0.600 16.620 1.928 ;
    RECT 16.500 1250.872 16.620 1252.200 ;
    RECT 16.692 0.600 16.812 1.928 ;
    RECT 16.692 1250.872 16.812 1252.200 ;
    RECT 21.900 0.600 22.020 1.928 ;
    RECT 21.900 1250.872 22.020 1252.200 ;
    RECT 22.092 0.600 22.212 1.928 ;
    RECT 22.092 1250.872 22.212 1252.200 ;
    RECT 27.300 0.600 27.420 1.928 ;
    RECT 27.300 1250.872 27.420 1252.200 ;
    RECT 27.492 0.600 27.612 1.928 ;
    RECT 27.492 1250.872 27.612 1252.200 ;
    RECT 32.700 0.600 32.820 1.928 ;
    RECT 32.700 1250.872 32.820 1252.200 ;
    RECT 32.892 0.600 33.012 1.928 ;
    RECT 32.892 1250.872 33.012 1252.200 ;
    RECT 38.100 0.600 38.220 1.928 ;
    RECT 38.100 1250.872 38.220 1252.200 ;
    RECT 38.292 0.600 38.412 1.928 ;
    RECT 38.292 1250.872 38.412 1252.200 ;
    RECT 43.500 0.600 43.620 1.928 ;
    RECT 43.500 1250.872 43.620 1252.200 ;
    RECT 43.692 0.600 43.812 1.928 ;
    RECT 43.692 1250.872 43.812 1252.200 ;
    RECT 48.900 0.600 49.020 1.928 ;
    RECT 48.900 1250.872 49.020 1252.200 ;
    RECT 49.092 0.600 49.212 1.928 ;
    RECT 49.092 1250.872 49.212 1252.200 ;
    RECT 54.300 0.600 54.420 1.928 ;
    RECT 54.300 1250.872 54.420 1252.200 ;
    RECT 54.492 0.600 54.612 1.928 ;
    RECT 54.492 1250.872 54.612 1252.200 ;
    RECT 59.700 0.600 59.820 1.928 ;
    RECT 59.700 1250.872 59.820 1252.200 ;
    RECT 59.892 0.600 60.012 1.928 ;
    RECT 59.892 1250.872 60.012 1252.200 ;
    RECT 65.100 0.600 65.220 1.928 ;
    RECT 65.100 1250.872 65.220 1252.200 ;
    RECT 65.292 0.600 65.412 1.928 ;
    RECT 65.292 1250.872 65.412 1252.200 ;
    RECT 70.500 0.600 70.620 1.928 ;
    RECT 70.500 1250.872 70.620 1252.200 ;
    RECT 70.692 0.600 70.812 1.928 ;
    RECT 70.692 1250.872 70.812 1252.200 ;
    RECT 75.900 0.600 76.020 1.928 ;
    RECT 75.900 1250.872 76.020 1252.200 ;
    RECT 76.092 0.600 76.212 1.928 ;
    RECT 76.092 1250.872 76.212 1252.200 ;
    RECT 81.300 0.600 81.420 1.928 ;
    RECT 81.300 1250.872 81.420 1252.200 ;
    RECT 81.492 0.600 81.612 1.928 ;
    RECT 81.492 1250.872 81.612 1252.200 ;
    RECT 86.700 0.600 86.820 1.928 ;
    RECT 86.700 1250.872 86.820 1252.200 ;
    RECT 86.892 0.600 87.012 1.928 ;
    RECT 86.892 1250.872 87.012 1252.200 ;
    RECT 92.100 0.600 92.220 1.928 ;
    RECT 92.100 1250.872 92.220 1252.200 ;
    RECT 92.292 0.600 92.412 1.928 ;
    RECT 92.292 1250.872 92.412 1252.200 ;
    RECT 97.500 0.600 97.620 1.928 ;
    RECT 97.500 1250.872 97.620 1252.200 ;
    RECT 97.692 0.600 97.812 1.928 ;
    RECT 97.692 1250.872 97.812 1252.200 ;
    RECT 102.900 0.600 103.020 1.928 ;
    RECT 102.900 1250.872 103.020 1252.200 ;
    RECT 103.092 0.600 103.212 1.928 ;
    RECT 103.092 1250.872 103.212 1252.200 ;
  END
END ot_ucie_pma_txm

END LIBRARY
